VERSION 5.7 ;
  NOWIREEXTENSIONATPIN ON ;
  DIVIDERCHAR "/" ;
  BUSBITCHARS "[]" ;
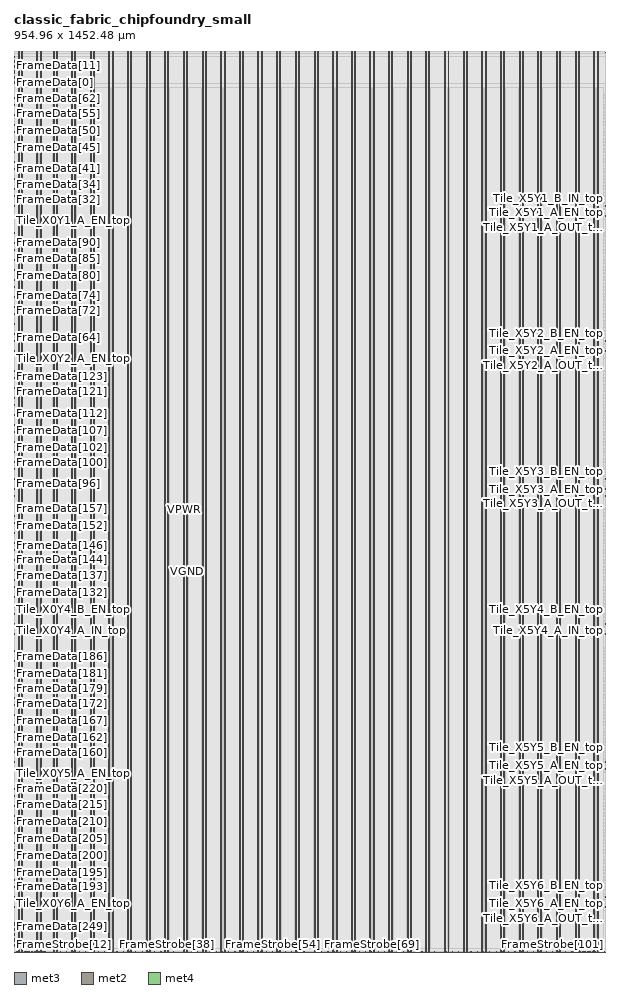
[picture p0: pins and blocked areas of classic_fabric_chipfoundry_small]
MACRO classic_fabric_chipfoundry_small
  CLASS BLOCK ;
  FOREIGN classic_fabric_chipfoundry_small ;
  ORIGIN 0.000 0.000 ;
  SIZE 954.960 BY 1452.480 ;
  PIN FrameData[0]
    DIRECTION INPUT ;
    USE SIGNAL ;
    ANTENNAGATEAREA 0.593700 ;
    ANTENNADIFFAREA 0.434700 ;
    PORT
      LAYER met3 ;
        RECT 0.000 1402.200 0.600 1402.800 ;
    END
  END FrameData[0]
  PIN FrameData[100]
    DIRECTION INPUT ;
    USE SIGNAL ;
    ANTENNAGATEAREA 0.795000 ;
    PORT
      LAYER met3 ;
        RECT 0.000 790.200 0.600 790.800 ;
    END
  END FrameData[100]
  PIN FrameData[101]
    DIRECTION INPUT ;
    USE SIGNAL ;
    ANTENNAGATEAREA 0.795000 ;
    PORT
      LAYER met3 ;
        RECT 0.000 795.640 0.600 796.240 ;
    END
  END FrameData[101]
  PIN FrameData[102]
    DIRECTION INPUT ;
    USE SIGNAL ;
    ANTENNAGATEAREA 0.795000 ;
    PORT
      LAYER met3 ;
        RECT 0.000 801.080 0.600 801.680 ;
    END
  END FrameData[102]
  PIN FrameData[103]
    DIRECTION INPUT ;
    USE SIGNAL ;
    ANTENNAGATEAREA 0.795000 ;
    PORT
      LAYER met3 ;
        RECT 0.000 806.520 0.600 807.120 ;
    END
  END FrameData[103]
  PIN FrameData[104]
    DIRECTION INPUT ;
    USE SIGNAL ;
    ANTENNAGATEAREA 0.795000 ;
    PORT
      LAYER met3 ;
        RECT 0.000 811.960 0.600 812.560 ;
    END
  END FrameData[104]
  PIN FrameData[105]
    DIRECTION INPUT ;
    USE SIGNAL ;
    ANTENNAGATEAREA 0.795000 ;
    PORT
      LAYER met3 ;
        RECT 0.000 817.400 0.600 818.000 ;
    END
  END FrameData[105]
  PIN FrameData[106]
    DIRECTION INPUT ;
    USE SIGNAL ;
    ANTENNAGATEAREA 0.795000 ;
    PORT
      LAYER met3 ;
        RECT 0.000 822.840 0.600 823.440 ;
    END
  END FrameData[106]
  PIN FrameData[107]
    DIRECTION INPUT ;
    USE SIGNAL ;
    ANTENNAGATEAREA 0.795000 ;
    PORT
      LAYER met3 ;
        RECT 0.000 828.280 0.600 828.880 ;
    END
  END FrameData[107]
  PIN FrameData[108]
    DIRECTION INPUT ;
    USE SIGNAL ;
    ANTENNAGATEAREA 0.795000 ;
    PORT
      LAYER met3 ;
        RECT 0.000 833.720 0.600 834.320 ;
    END
  END FrameData[108]
  PIN FrameData[109]
    DIRECTION INPUT ;
    USE SIGNAL ;
    ANTENNAGATEAREA 0.795000 ;
    PORT
      LAYER met3 ;
        RECT 0.000 839.160 0.600 839.760 ;
    END
  END FrameData[109]
  PIN FrameData[10]
    DIRECTION INPUT ;
    USE SIGNAL ;
    ANTENNAGATEAREA 0.159000 ;
    PORT
      LAYER met3 ;
        RECT 0.000 1415.800 0.600 1416.400 ;
    END
  END FrameData[10]
  PIN FrameData[110]
    DIRECTION INPUT ;
    USE SIGNAL ;
    ANTENNAGATEAREA 0.795000 ;
    PORT
      LAYER met3 ;
        RECT 0.000 844.600 0.600 845.200 ;
    END
  END FrameData[110]
  PIN FrameData[111]
    DIRECTION INPUT ;
    USE SIGNAL ;
    ANTENNAGATEAREA 0.795000 ;
    PORT
      LAYER met3 ;
        RECT 0.000 850.040 0.600 850.640 ;
    END
  END FrameData[111]
  PIN FrameData[112]
    DIRECTION INPUT ;
    USE SIGNAL ;
    ANTENNAGATEAREA 0.795000 ;
    PORT
      LAYER met3 ;
        RECT 0.000 855.480 0.600 856.080 ;
    END
  END FrameData[112]
  PIN FrameData[113]
    DIRECTION INPUT ;
    USE SIGNAL ;
    ANTENNAGATEAREA 0.795000 ;
    PORT
      LAYER met3 ;
        RECT 0.000 860.920 0.600 861.520 ;
    END
  END FrameData[113]
  PIN FrameData[114]
    DIRECTION INPUT ;
    USE SIGNAL ;
    ANTENNAGATEAREA 1.229700 ;
    ANTENNADIFFAREA 0.434700 ;
    PORT
      LAYER met3 ;
        RECT 0.000 866.360 0.600 866.960 ;
    END
  END FrameData[114]
  PIN FrameData[115]
    DIRECTION INPUT ;
    USE SIGNAL ;
    ANTENNAGATEAREA 0.795000 ;
    PORT
      LAYER met3 ;
        RECT 0.000 871.800 0.600 872.400 ;
    END
  END FrameData[115]
  PIN FrameData[116]
    DIRECTION INPUT ;
    USE SIGNAL ;
    ANTENNAGATEAREA 0.795000 ;
    PORT
      LAYER met3 ;
        RECT 0.000 877.240 0.600 877.840 ;
    END
  END FrameData[116]
  PIN FrameData[117]
    DIRECTION INPUT ;
    USE SIGNAL ;
    ANTENNAGATEAREA 0.795000 ;
    PORT
      LAYER met3 ;
        RECT 0.000 882.680 0.600 883.280 ;
    END
  END FrameData[117]
  PIN FrameData[118]
    DIRECTION INPUT ;
    USE SIGNAL ;
    ANTENNAGATEAREA 1.229700 ;
    ANTENNADIFFAREA 0.434700 ;
    PORT
      LAYER met3 ;
        RECT 0.000 888.120 0.600 888.720 ;
    END
  END FrameData[118]
  PIN FrameData[119]
    DIRECTION INPUT ;
    USE SIGNAL ;
    ANTENNAGATEAREA 0.795000 ;
    PORT
      LAYER met3 ;
        RECT 0.000 893.560 0.600 894.160 ;
    END
  END FrameData[119]
  PIN FrameData[11]
    DIRECTION INPUT ;
    USE SIGNAL ;
    ANTENNAGATEAREA 0.159000 ;
    PORT
      LAYER met3 ;
        RECT 0.000 1417.160 0.600 1417.760 ;
    END
  END FrameData[11]
  PIN FrameData[120]
    DIRECTION INPUT ;
    USE SIGNAL ;
    ANTENNAGATEAREA 0.795000 ;
    PORT
      LAYER met3 ;
        RECT 0.000 899.000 0.600 899.600 ;
    END
  END FrameData[120]
  PIN FrameData[121]
    DIRECTION INPUT ;
    USE SIGNAL ;
    ANTENNAGATEAREA 0.795000 ;
    PORT
      LAYER met3 ;
        RECT 0.000 904.440 0.600 905.040 ;
    END
  END FrameData[121]
  PIN FrameData[122]
    DIRECTION INPUT ;
    USE SIGNAL ;
    ANTENNAGATEAREA 0.795000 ;
    PORT
      LAYER met3 ;
        RECT 0.000 909.880 0.600 910.480 ;
    END
  END FrameData[122]
  PIN FrameData[123]
    DIRECTION INPUT ;
    USE SIGNAL ;
    ANTENNAGATEAREA 0.795000 ;
    PORT
      LAYER met3 ;
        RECT 0.000 915.320 0.600 915.920 ;
    END
  END FrameData[123]
  PIN FrameData[124]
    DIRECTION INPUT ;
    USE SIGNAL ;
    ANTENNAGATEAREA 0.795000 ;
    PORT
      LAYER met3 ;
        RECT 0.000 920.760 0.600 921.360 ;
    END
  END FrameData[124]
  PIN FrameData[125]
    DIRECTION INPUT ;
    USE SIGNAL ;
    ANTENNAGATEAREA 0.795000 ;
    PORT
      LAYER met3 ;
        RECT 0.000 926.200 0.600 926.800 ;
    END
  END FrameData[125]
  PIN FrameData[126]
    DIRECTION INPUT ;
    USE SIGNAL ;
    ANTENNAGATEAREA 0.795000 ;
    PORT
      LAYER met3 ;
        RECT 0.000 931.640 0.600 932.240 ;
    END
  END FrameData[126]
  PIN FrameData[127]
    DIRECTION INPUT ;
    USE SIGNAL ;
    ANTENNAGATEAREA 0.795000 ;
    PORT
      LAYER met3 ;
        RECT 0.000 937.080 0.600 937.680 ;
    END
  END FrameData[127]
  PIN FrameData[128]
    DIRECTION INPUT ;
    USE SIGNAL ;
    ANTENNAGATEAREA 0.636000 ;
    PORT
      LAYER met3 ;
        RECT 0.000 545.400 0.600 546.000 ;
    END
  END FrameData[128]
  PIN FrameData[129]
    DIRECTION INPUT ;
    USE SIGNAL ;
    ANTENNAGATEAREA 0.636000 ;
    PORT
      LAYER met3 ;
        RECT 0.000 550.840 0.600 551.440 ;
    END
  END FrameData[129]
  PIN FrameData[12]
    DIRECTION INPUT ;
    USE SIGNAL ;
    ANTENNAGATEAREA 0.593700 ;
    ANTENNADIFFAREA 0.434700 ;
    PORT
      LAYER met3 ;
        RECT 0.000 1418.520 0.600 1419.120 ;
    END
  END FrameData[12]
  PIN FrameData[130]
    DIRECTION INPUT ;
    USE SIGNAL ;
    ANTENNAGATEAREA 0.795000 ;
    PORT
      LAYER met3 ;
        RECT 0.000 556.280 0.600 556.880 ;
    END
  END FrameData[130]
  PIN FrameData[131]
    DIRECTION INPUT ;
    USE SIGNAL ;
    ANTENNAGATEAREA 0.795000 ;
    PORT
      LAYER met3 ;
        RECT 0.000 561.720 0.600 562.320 ;
    END
  END FrameData[131]
  PIN FrameData[132]
    DIRECTION INPUT ;
    USE SIGNAL ;
    ANTENNAGATEAREA 0.795000 ;
    PORT
      LAYER met3 ;
        RECT 0.000 567.160 0.600 567.760 ;
    END
  END FrameData[132]
  PIN FrameData[133]
    DIRECTION INPUT ;
    USE SIGNAL ;
    ANTENNAGATEAREA 0.795000 ;
    PORT
      LAYER met3 ;
        RECT 0.000 572.600 0.600 573.200 ;
    END
  END FrameData[133]
  PIN FrameData[134]
    DIRECTION INPUT ;
    USE SIGNAL ;
    ANTENNAGATEAREA 0.795000 ;
    PORT
      LAYER met3 ;
        RECT 0.000 578.040 0.600 578.640 ;
    END
  END FrameData[134]
  PIN FrameData[135]
    DIRECTION INPUT ;
    USE SIGNAL ;
    ANTENNAGATEAREA 0.795000 ;
    PORT
      LAYER met3 ;
        RECT 0.000 583.480 0.600 584.080 ;
    END
  END FrameData[135]
  PIN FrameData[136]
    DIRECTION INPUT ;
    USE SIGNAL ;
    ANTENNAGATEAREA 0.795000 ;
    PORT
      LAYER met3 ;
        RECT 0.000 588.920 0.600 589.520 ;
    END
  END FrameData[136]
  PIN FrameData[137]
    DIRECTION INPUT ;
    USE SIGNAL ;
    ANTENNAGATEAREA 0.795000 ;
    PORT
      LAYER met3 ;
        RECT 0.000 594.360 0.600 594.960 ;
    END
  END FrameData[137]
  PIN FrameData[138]
    DIRECTION INPUT ;
    USE SIGNAL ;
    ANTENNAGATEAREA 0.795000 ;
    PORT
      LAYER met3 ;
        RECT 0.000 599.800 0.600 600.400 ;
    END
  END FrameData[138]
  PIN FrameData[139]
    DIRECTION INPUT ;
    USE SIGNAL ;
    ANTENNAGATEAREA 0.795000 ;
    PORT
      LAYER met3 ;
        RECT 0.000 605.240 0.600 605.840 ;
    END
  END FrameData[139]
  PIN FrameData[13]
    DIRECTION INPUT ;
    USE SIGNAL ;
    ANTENNAGATEAREA 0.593700 ;
    ANTENNADIFFAREA 0.434700 ;
    PORT
      LAYER met3 ;
        RECT 0.000 1419.880 0.600 1420.480 ;
    END
  END FrameData[13]
  PIN FrameData[140]
    DIRECTION INPUT ;
    USE SIGNAL ;
    ANTENNAGATEAREA 0.795000 ;
    PORT
      LAYER met3 ;
        RECT 0.000 610.680 0.600 611.280 ;
    END
  END FrameData[140]
  PIN FrameData[141]
    DIRECTION INPUT ;
    USE SIGNAL ;
    ANTENNAGATEAREA 0.795000 ;
    PORT
      LAYER met3 ;
        RECT 0.000 616.120 0.600 616.720 ;
    END
  END FrameData[141]
  PIN FrameData[142]
    DIRECTION INPUT ;
    USE SIGNAL ;
    ANTENNAGATEAREA 0.795000 ;
    PORT
      LAYER met3 ;
        RECT 0.000 621.560 0.600 622.160 ;
    END
  END FrameData[142]
  PIN FrameData[143]
    DIRECTION INPUT ;
    USE SIGNAL ;
    ANTENNAGATEAREA 0.795000 ;
    PORT
      LAYER met3 ;
        RECT 0.000 627.000 0.600 627.600 ;
    END
  END FrameData[143]
  PIN FrameData[144]
    DIRECTION INPUT ;
    USE SIGNAL ;
    ANTENNAGATEAREA 0.795000 ;
    PORT
      LAYER met3 ;
        RECT 0.000 632.440 0.600 633.040 ;
    END
  END FrameData[144]
  PIN FrameData[145]
    DIRECTION INPUT ;
    USE SIGNAL ;
    ANTENNAGATEAREA 0.795000 ;
    PORT
      LAYER met3 ;
        RECT 0.000 637.880 0.600 638.480 ;
    END
  END FrameData[145]
  PIN FrameData[146]
    DIRECTION INPUT ;
    USE SIGNAL ;
    ANTENNAGATEAREA 1.229700 ;
    ANTENNADIFFAREA 0.434700 ;
    PORT
      LAYER met3 ;
        RECT 0.000 643.320 0.600 643.920 ;
    END
  END FrameData[146]
  PIN FrameData[147]
    DIRECTION INPUT ;
    USE SIGNAL ;
    ANTENNAGATEAREA 0.795000 ;
    PORT
      LAYER met3 ;
        RECT 0.000 648.760 0.600 649.360 ;
    END
  END FrameData[147]
  PIN FrameData[148]
    DIRECTION INPUT ;
    USE SIGNAL ;
    ANTENNAGATEAREA 0.795000 ;
    PORT
      LAYER met3 ;
        RECT 0.000 654.200 0.600 654.800 ;
    END
  END FrameData[148]
  PIN FrameData[149]
    DIRECTION INPUT ;
    USE SIGNAL ;
    ANTENNAGATEAREA 0.795000 ;
    PORT
      LAYER met3 ;
        RECT 0.000 659.640 0.600 660.240 ;
    END
  END FrameData[149]
  PIN FrameData[14]
    DIRECTION INPUT ;
    USE SIGNAL ;
    ANTENNAGATEAREA 0.593700 ;
    ANTENNADIFFAREA 0.434700 ;
    PORT
      LAYER met3 ;
        RECT 0.000 1421.240 0.600 1421.840 ;
    END
  END FrameData[14]
  PIN FrameData[150]
    DIRECTION INPUT ;
    USE SIGNAL ;
    ANTENNAGATEAREA 1.229700 ;
    ANTENNADIFFAREA 0.434700 ;
    PORT
      LAYER met3 ;
        RECT 0.000 665.080 0.600 665.680 ;
    END
  END FrameData[150]
  PIN FrameData[151]
    DIRECTION INPUT ;
    USE SIGNAL ;
    ANTENNAGATEAREA 0.795000 ;
    PORT
      LAYER met3 ;
        RECT 0.000 670.520 0.600 671.120 ;
    END
  END FrameData[151]
  PIN FrameData[152]
    DIRECTION INPUT ;
    USE SIGNAL ;
    ANTENNAGATEAREA 0.795000 ;
    PORT
      LAYER met3 ;
        RECT 0.000 675.960 0.600 676.560 ;
    END
  END FrameData[152]
  PIN FrameData[153]
    DIRECTION INPUT ;
    USE SIGNAL ;
    ANTENNAGATEAREA 0.795000 ;
    PORT
      LAYER met3 ;
        RECT 0.000 681.400 0.600 682.000 ;
    END
  END FrameData[153]
  PIN FrameData[154]
    DIRECTION INPUT ;
    USE SIGNAL ;
    ANTENNAGATEAREA 0.795000 ;
    PORT
      LAYER met3 ;
        RECT 0.000 686.840 0.600 687.440 ;
    END
  END FrameData[154]
  PIN FrameData[155]
    DIRECTION INPUT ;
    USE SIGNAL ;
    ANTENNAGATEAREA 0.795000 ;
    PORT
      LAYER met3 ;
        RECT 0.000 692.280 0.600 692.880 ;
    END
  END FrameData[155]
  PIN FrameData[156]
    DIRECTION INPUT ;
    USE SIGNAL ;
    ANTENNAGATEAREA 0.795000 ;
    PORT
      LAYER met3 ;
        RECT 0.000 697.720 0.600 698.320 ;
    END
  END FrameData[156]
  PIN FrameData[157]
    DIRECTION INPUT ;
    USE SIGNAL ;
    ANTENNAGATEAREA 0.795000 ;
    PORT
      LAYER met3 ;
        RECT 0.000 703.160 0.600 703.760 ;
    END
  END FrameData[157]
  PIN FrameData[158]
    DIRECTION INPUT ;
    USE SIGNAL ;
    ANTENNAGATEAREA 0.795000 ;
    PORT
      LAYER met3 ;
        RECT 0.000 708.600 0.600 709.200 ;
    END
  END FrameData[158]
  PIN FrameData[159]
    DIRECTION INPUT ;
    USE SIGNAL ;
    ANTENNAGATEAREA 0.795000 ;
    PORT
      LAYER met3 ;
        RECT 0.000 714.040 0.600 714.640 ;
    END
  END FrameData[159]
  PIN FrameData[15]
    DIRECTION INPUT ;
    USE SIGNAL ;
    ANTENNAGATEAREA 0.159000 ;
    PORT
      LAYER met3 ;
        RECT 0.000 1422.600 0.600 1423.200 ;
    END
  END FrameData[15]
  PIN FrameData[160]
    DIRECTION INPUT ;
    USE SIGNAL ;
    ANTENNAGATEAREA 0.636000 ;
    PORT
      LAYER met3 ;
        RECT 0.000 322.360 0.600 322.960 ;
    END
  END FrameData[160]
  PIN FrameData[161]
    DIRECTION INPUT ;
    USE SIGNAL ;
    ANTENNAGATEAREA 0.636000 ;
    PORT
      LAYER met3 ;
        RECT 0.000 327.800 0.600 328.400 ;
    END
  END FrameData[161]
  PIN FrameData[162]
    DIRECTION INPUT ;
    USE SIGNAL ;
    ANTENNAGATEAREA 0.795000 ;
    PORT
      LAYER met3 ;
        RECT 0.000 333.240 0.600 333.840 ;
    END
  END FrameData[162]
  PIN FrameData[163]
    DIRECTION INPUT ;
    USE SIGNAL ;
    ANTENNAGATEAREA 0.795000 ;
    PORT
      LAYER met3 ;
        RECT 0.000 338.680 0.600 339.280 ;
    END
  END FrameData[163]
  PIN FrameData[164]
    DIRECTION INPUT ;
    USE SIGNAL ;
    ANTENNAGATEAREA 0.795000 ;
    PORT
      LAYER met3 ;
        RECT 0.000 344.120 0.600 344.720 ;
    END
  END FrameData[164]
  PIN FrameData[165]
    DIRECTION INPUT ;
    USE SIGNAL ;
    ANTENNAGATEAREA 0.795000 ;
    PORT
      LAYER met3 ;
        RECT 0.000 349.560 0.600 350.160 ;
    END
  END FrameData[165]
  PIN FrameData[166]
    DIRECTION INPUT ;
    USE SIGNAL ;
    ANTENNAGATEAREA 0.795000 ;
    PORT
      LAYER met3 ;
        RECT 0.000 355.000 0.600 355.600 ;
    END
  END FrameData[166]
  PIN FrameData[167]
    DIRECTION INPUT ;
    USE SIGNAL ;
    ANTENNAGATEAREA 0.795000 ;
    PORT
      LAYER met3 ;
        RECT 0.000 360.440 0.600 361.040 ;
    END
  END FrameData[167]
  PIN FrameData[168]
    DIRECTION INPUT ;
    USE SIGNAL ;
    ANTENNAGATEAREA 0.795000 ;
    PORT
      LAYER met3 ;
        RECT 0.000 365.880 0.600 366.480 ;
    END
  END FrameData[168]
  PIN FrameData[169]
    DIRECTION INPUT ;
    USE SIGNAL ;
    ANTENNAGATEAREA 0.795000 ;
    PORT
      LAYER met3 ;
        RECT 0.000 371.320 0.600 371.920 ;
    END
  END FrameData[169]
  PIN FrameData[16]
    DIRECTION INPUT ;
    USE SIGNAL ;
    ANTENNAGATEAREA 0.159000 ;
    PORT
      LAYER met3 ;
        RECT 0.000 1423.960 0.600 1424.560 ;
    END
  END FrameData[16]
  PIN FrameData[170]
    DIRECTION INPUT ;
    USE SIGNAL ;
    ANTENNAGATEAREA 0.795000 ;
    PORT
      LAYER met3 ;
        RECT 0.000 376.760 0.600 377.360 ;
    END
  END FrameData[170]
  PIN FrameData[171]
    DIRECTION INPUT ;
    USE SIGNAL ;
    ANTENNAGATEAREA 0.795000 ;
    PORT
      LAYER met3 ;
        RECT 0.000 382.200 0.600 382.800 ;
    END
  END FrameData[171]
  PIN FrameData[172]
    DIRECTION INPUT ;
    USE SIGNAL ;
    ANTENNAGATEAREA 0.795000 ;
    PORT
      LAYER met3 ;
        RECT 0.000 387.640 0.600 388.240 ;
    END
  END FrameData[172]
  PIN FrameData[173]
    DIRECTION INPUT ;
    USE SIGNAL ;
    ANTENNAGATEAREA 0.795000 ;
    PORT
      LAYER met3 ;
        RECT 0.000 393.080 0.600 393.680 ;
    END
  END FrameData[173]
  PIN FrameData[174]
    DIRECTION INPUT ;
    USE SIGNAL ;
    ANTENNAGATEAREA 0.795000 ;
    PORT
      LAYER met3 ;
        RECT 0.000 398.520 0.600 399.120 ;
    END
  END FrameData[174]
  PIN FrameData[175]
    DIRECTION INPUT ;
    USE SIGNAL ;
    ANTENNAGATEAREA 0.795000 ;
    PORT
      LAYER met3 ;
        RECT 0.000 403.960 0.600 404.560 ;
    END
  END FrameData[175]
  PIN FrameData[176]
    DIRECTION INPUT ;
    USE SIGNAL ;
    ANTENNAGATEAREA 0.795000 ;
    PORT
      LAYER met3 ;
        RECT 0.000 409.400 0.600 410.000 ;
    END
  END FrameData[176]
  PIN FrameData[177]
    DIRECTION INPUT ;
    USE SIGNAL ;
    ANTENNAGATEAREA 0.795000 ;
    PORT
      LAYER met3 ;
        RECT 0.000 414.840 0.600 415.440 ;
    END
  END FrameData[177]
  PIN FrameData[178]
    DIRECTION INPUT ;
    USE SIGNAL ;
    ANTENNAGATEAREA 1.229700 ;
    ANTENNADIFFAREA 0.434700 ;
    PORT
      LAYER met3 ;
        RECT 0.000 420.280 0.600 420.880 ;
    END
  END FrameData[178]
  PIN FrameData[179]
    DIRECTION INPUT ;
    USE SIGNAL ;
    ANTENNAGATEAREA 0.795000 ;
    PORT
      LAYER met3 ;
        RECT 0.000 425.720 0.600 426.320 ;
    END
  END FrameData[179]
  PIN FrameData[17]
    DIRECTION INPUT ;
    USE SIGNAL ;
    ANTENNAGATEAREA 0.159000 ;
    PORT
      LAYER met3 ;
        RECT 0.000 1425.320 0.600 1425.920 ;
    END
  END FrameData[17]
  PIN FrameData[180]
    DIRECTION INPUT ;
    USE SIGNAL ;
    ANTENNAGATEAREA 0.795000 ;
    PORT
      LAYER met3 ;
        RECT 0.000 431.160 0.600 431.760 ;
    END
  END FrameData[180]
  PIN FrameData[181]
    DIRECTION INPUT ;
    USE SIGNAL ;
    ANTENNAGATEAREA 0.795000 ;
    PORT
      LAYER met3 ;
        RECT 0.000 436.600 0.600 437.200 ;
    END
  END FrameData[181]
  PIN FrameData[182]
    DIRECTION INPUT ;
    USE SIGNAL ;
    ANTENNAGATEAREA 1.229700 ;
    ANTENNADIFFAREA 0.434700 ;
    PORT
      LAYER met3 ;
        RECT 0.000 442.040 0.600 442.640 ;
    END
  END FrameData[182]
  PIN FrameData[183]
    DIRECTION INPUT ;
    USE SIGNAL ;
    ANTENNAGATEAREA 0.795000 ;
    PORT
      LAYER met3 ;
        RECT 0.000 447.480 0.600 448.080 ;
    END
  END FrameData[183]
  PIN FrameData[184]
    DIRECTION INPUT ;
    USE SIGNAL ;
    ANTENNAGATEAREA 0.795000 ;
    PORT
      LAYER met3 ;
        RECT 0.000 452.920 0.600 453.520 ;
    END
  END FrameData[184]
  PIN FrameData[185]
    DIRECTION INPUT ;
    USE SIGNAL ;
    ANTENNAGATEAREA 0.795000 ;
    PORT
      LAYER met3 ;
        RECT 0.000 458.360 0.600 458.960 ;
    END
  END FrameData[185]
  PIN FrameData[186]
    DIRECTION INPUT ;
    USE SIGNAL ;
    ANTENNAGATEAREA 0.795000 ;
    PORT
      LAYER met3 ;
        RECT 0.000 463.800 0.600 464.400 ;
    END
  END FrameData[186]
  PIN FrameData[187]
    DIRECTION INPUT ;
    USE SIGNAL ;
    ANTENNAGATEAREA 0.795000 ;
    PORT
      LAYER met3 ;
        RECT 0.000 469.240 0.600 469.840 ;
    END
  END FrameData[187]
  PIN FrameData[188]
    DIRECTION INPUT ;
    USE SIGNAL ;
    ANTENNAGATEAREA 0.795000 ;
    PORT
      LAYER met3 ;
        RECT 0.000 474.680 0.600 475.280 ;
    END
  END FrameData[188]
  PIN FrameData[189]
    DIRECTION INPUT ;
    USE SIGNAL ;
    ANTENNAGATEAREA 0.795000 ;
    PORT
      LAYER met3 ;
        RECT 0.000 480.120 0.600 480.720 ;
    END
  END FrameData[189]
  PIN FrameData[18]
    DIRECTION INPUT ;
    USE SIGNAL ;
    ANTENNAGATEAREA 0.159000 ;
    PORT
      LAYER met3 ;
        RECT 0.000 1426.680 0.600 1427.280 ;
    END
  END FrameData[18]
  PIN FrameData[190]
    DIRECTION INPUT ;
    USE SIGNAL ;
    ANTENNAGATEAREA 0.795000 ;
    PORT
      LAYER met3 ;
        RECT 0.000 485.560 0.600 486.160 ;
    END
  END FrameData[190]
  PIN FrameData[191]
    DIRECTION INPUT ;
    USE SIGNAL ;
    ANTENNAGATEAREA 0.795000 ;
    PORT
      LAYER met3 ;
        RECT 0.000 491.000 0.600 491.600 ;
    END
  END FrameData[191]
  PIN FrameData[192]
    DIRECTION INPUT ;
    USE SIGNAL ;
    ANTENNAGATEAREA 0.636000 ;
    PORT
      LAYER met3 ;
        RECT 0.000 99.320 0.600 99.920 ;
    END
  END FrameData[192]
  PIN FrameData[193]
    DIRECTION INPUT ;
    USE SIGNAL ;
    ANTENNAGATEAREA 0.636000 ;
    PORT
      LAYER met3 ;
        RECT 0.000 104.760 0.600 105.360 ;
    END
  END FrameData[193]
  PIN FrameData[194]
    DIRECTION INPUT ;
    USE SIGNAL ;
    ANTENNAGATEAREA 0.795000 ;
    PORT
      LAYER met3 ;
        RECT 0.000 110.200 0.600 110.800 ;
    END
  END FrameData[194]
  PIN FrameData[195]
    DIRECTION INPUT ;
    USE SIGNAL ;
    ANTENNAGATEAREA 0.795000 ;
    PORT
      LAYER met3 ;
        RECT 0.000 115.640 0.600 116.240 ;
    END
  END FrameData[195]
  PIN FrameData[196]
    DIRECTION INPUT ;
    USE SIGNAL ;
    ANTENNAGATEAREA 0.795000 ;
    PORT
      LAYER met3 ;
        RECT 0.000 121.080 0.600 121.680 ;
    END
  END FrameData[196]
  PIN FrameData[197]
    DIRECTION INPUT ;
    USE SIGNAL ;
    ANTENNAGATEAREA 0.795000 ;
    PORT
      LAYER met3 ;
        RECT 0.000 126.520 0.600 127.120 ;
    END
  END FrameData[197]
  PIN FrameData[198]
    DIRECTION INPUT ;
    USE SIGNAL ;
    ANTENNAGATEAREA 0.795000 ;
    PORT
      LAYER met3 ;
        RECT 0.000 131.960 0.600 132.560 ;
    END
  END FrameData[198]
  PIN FrameData[199]
    DIRECTION INPUT ;
    USE SIGNAL ;
    ANTENNAGATEAREA 0.795000 ;
    PORT
      LAYER met3 ;
        RECT 0.000 137.400 0.600 138.000 ;
    END
  END FrameData[199]
  PIN FrameData[19]
    DIRECTION INPUT ;
    USE SIGNAL ;
    ANTENNAGATEAREA 0.159000 ;
    PORT
      LAYER met3 ;
        RECT 0.000 1428.040 0.600 1428.640 ;
    END
  END FrameData[19]
  PIN FrameData[1]
    DIRECTION INPUT ;
    USE SIGNAL ;
    ANTENNAGATEAREA 0.593700 ;
    ANTENNADIFFAREA 0.434700 ;
    PORT
      LAYER met3 ;
        RECT 0.000 1403.560 0.600 1404.160 ;
    END
  END FrameData[1]
  PIN FrameData[200]
    DIRECTION INPUT ;
    USE SIGNAL ;
    ANTENNAGATEAREA 0.795000 ;
    PORT
      LAYER met3 ;
        RECT 0.000 142.840 0.600 143.440 ;
    END
  END FrameData[200]
  PIN FrameData[201]
    DIRECTION INPUT ;
    USE SIGNAL ;
    ANTENNAGATEAREA 0.795000 ;
    PORT
      LAYER met3 ;
        RECT 0.000 148.280 0.600 148.880 ;
    END
  END FrameData[201]
  PIN FrameData[202]
    DIRECTION INPUT ;
    USE SIGNAL ;
    ANTENNAGATEAREA 0.795000 ;
    PORT
      LAYER met3 ;
        RECT 0.000 153.720 0.600 154.320 ;
    END
  END FrameData[202]
  PIN FrameData[203]
    DIRECTION INPUT ;
    USE SIGNAL ;
    ANTENNAGATEAREA 0.795000 ;
    PORT
      LAYER met3 ;
        RECT 0.000 159.160 0.600 159.760 ;
    END
  END FrameData[203]
  PIN FrameData[204]
    DIRECTION INPUT ;
    USE SIGNAL ;
    ANTENNAGATEAREA 0.795000 ;
    PORT
      LAYER met3 ;
        RECT 0.000 164.600 0.600 165.200 ;
    END
  END FrameData[204]
  PIN FrameData[205]
    DIRECTION INPUT ;
    USE SIGNAL ;
    ANTENNAGATEAREA 0.795000 ;
    PORT
      LAYER met3 ;
        RECT 0.000 170.040 0.600 170.640 ;
    END
  END FrameData[205]
  PIN FrameData[206]
    DIRECTION INPUT ;
    USE SIGNAL ;
    ANTENNAGATEAREA 0.795000 ;
    PORT
      LAYER met3 ;
        RECT 0.000 175.480 0.600 176.080 ;
    END
  END FrameData[206]
  PIN FrameData[207]
    DIRECTION INPUT ;
    USE SIGNAL ;
    ANTENNAGATEAREA 0.795000 ;
    PORT
      LAYER met3 ;
        RECT 0.000 180.920 0.600 181.520 ;
    END
  END FrameData[207]
  PIN FrameData[208]
    DIRECTION INPUT ;
    USE SIGNAL ;
    ANTENNAGATEAREA 0.795000 ;
    PORT
      LAYER met3 ;
        RECT 0.000 186.360 0.600 186.960 ;
    END
  END FrameData[208]
  PIN FrameData[209]
    DIRECTION INPUT ;
    USE SIGNAL ;
    ANTENNAGATEAREA 0.795000 ;
    PORT
      LAYER met3 ;
        RECT 0.000 191.800 0.600 192.400 ;
    END
  END FrameData[209]
  PIN FrameData[20]
    DIRECTION INPUT ;
    USE SIGNAL ;
    ANTENNAGATEAREA 0.159000 ;
    PORT
      LAYER met3 ;
        RECT 0.000 1429.400 0.600 1430.000 ;
    END
  END FrameData[20]
  PIN FrameData[210]
    DIRECTION INPUT ;
    USE SIGNAL ;
    ANTENNAGATEAREA 1.229700 ;
    ANTENNADIFFAREA 0.434700 ;
    PORT
      LAYER met3 ;
        RECT 0.000 197.240 0.600 197.840 ;
    END
  END FrameData[210]
  PIN FrameData[211]
    DIRECTION INPUT ;
    USE SIGNAL ;
    ANTENNAGATEAREA 0.795000 ;
    PORT
      LAYER met3 ;
        RECT 0.000 202.680 0.600 203.280 ;
    END
  END FrameData[211]
  PIN FrameData[212]
    DIRECTION INPUT ;
    USE SIGNAL ;
    ANTENNAGATEAREA 0.795000 ;
    PORT
      LAYER met3 ;
        RECT 0.000 208.120 0.600 208.720 ;
    END
  END FrameData[212]
  PIN FrameData[213]
    DIRECTION INPUT ;
    USE SIGNAL ;
    ANTENNAGATEAREA 0.795000 ;
    PORT
      LAYER met3 ;
        RECT 0.000 213.560 0.600 214.160 ;
    END
  END FrameData[213]
  PIN FrameData[214]
    DIRECTION INPUT ;
    USE SIGNAL ;
    ANTENNAGATEAREA 1.229700 ;
    ANTENNADIFFAREA 0.434700 ;
    PORT
      LAYER met3 ;
        RECT 0.000 219.000 0.600 219.600 ;
    END
  END FrameData[214]
  PIN FrameData[215]
    DIRECTION INPUT ;
    USE SIGNAL ;
    ANTENNAGATEAREA 0.795000 ;
    PORT
      LAYER met3 ;
        RECT 0.000 224.440 0.600 225.040 ;
    END
  END FrameData[215]
  PIN FrameData[216]
    DIRECTION INPUT ;
    USE SIGNAL ;
    ANTENNAGATEAREA 0.795000 ;
    PORT
      LAYER met3 ;
        RECT 0.000 229.880 0.600 230.480 ;
    END
  END FrameData[216]
  PIN FrameData[217]
    DIRECTION INPUT ;
    USE SIGNAL ;
    ANTENNAGATEAREA 0.795000 ;
    PORT
      LAYER met3 ;
        RECT 0.000 235.320 0.600 235.920 ;
    END
  END FrameData[217]
  PIN FrameData[218]
    DIRECTION INPUT ;
    USE SIGNAL ;
    ANTENNAGATEAREA 0.795000 ;
    PORT
      LAYER met3 ;
        RECT 0.000 240.760 0.600 241.360 ;
    END
  END FrameData[218]
  PIN FrameData[219]
    DIRECTION INPUT ;
    USE SIGNAL ;
    ANTENNAGATEAREA 0.795000 ;
    PORT
      LAYER met3 ;
        RECT 0.000 246.200 0.600 246.800 ;
    END
  END FrameData[219]
  PIN FrameData[21]
    DIRECTION INPUT ;
    USE SIGNAL ;
    ANTENNAGATEAREA 0.159000 ;
    PORT
      LAYER met3 ;
        RECT 0.000 1430.760 0.600 1431.360 ;
    END
  END FrameData[21]
  PIN FrameData[220]
    DIRECTION INPUT ;
    USE SIGNAL ;
    ANTENNAGATEAREA 0.795000 ;
    PORT
      LAYER met3 ;
        RECT 0.000 251.640 0.600 252.240 ;
    END
  END FrameData[220]
  PIN FrameData[221]
    DIRECTION INPUT ;
    USE SIGNAL ;
    ANTENNAGATEAREA 0.795000 ;
    PORT
      LAYER met3 ;
        RECT 0.000 257.080 0.600 257.680 ;
    END
  END FrameData[221]
  PIN FrameData[222]
    DIRECTION INPUT ;
    USE SIGNAL ;
    ANTENNAGATEAREA 0.795000 ;
    PORT
      LAYER met3 ;
        RECT 0.000 262.520 0.600 263.120 ;
    END
  END FrameData[222]
  PIN FrameData[223]
    DIRECTION INPUT ;
    USE SIGNAL ;
    ANTENNAGATEAREA 0.795000 ;
    PORT
      LAYER met3 ;
        RECT 0.000 267.960 0.600 268.560 ;
    END
  END FrameData[223]
  PIN FrameData[224]
    DIRECTION INPUT ;
    USE SIGNAL ;
    ANTENNAGATEAREA 0.159000 ;
    PORT
      LAYER met3 ;
        RECT 0.000 6.840 0.600 7.440 ;
    END
  END FrameData[224]
  PIN FrameData[225]
    DIRECTION INPUT ;
    USE SIGNAL ;
    ANTENNAGATEAREA 0.159000 ;
    PORT
      LAYER met3 ;
        RECT 0.000 8.200 0.600 8.800 ;
    END
  END FrameData[225]
  PIN FrameData[226]
    DIRECTION INPUT ;
    USE SIGNAL ;
    ANTENNAGATEAREA 0.159000 ;
    PORT
      LAYER met3 ;
        RECT 0.000 9.560 0.600 10.160 ;
    END
  END FrameData[226]
  PIN FrameData[227]
    DIRECTION INPUT ;
    USE SIGNAL ;
    ANTENNAGATEAREA 0.159000 ;
    PORT
      LAYER met3 ;
        RECT 0.000 10.920 0.600 11.520 ;
    END
  END FrameData[227]
  PIN FrameData[228]
    DIRECTION INPUT ;
    USE SIGNAL ;
    ANTENNAGATEAREA 0.159000 ;
    PORT
      LAYER met3 ;
        RECT 0.000 12.280 0.600 12.880 ;
    END
  END FrameData[228]
  PIN FrameData[229]
    DIRECTION INPUT ;
    USE SIGNAL ;
    ANTENNAGATEAREA 0.159000 ;
    PORT
      LAYER met3 ;
        RECT 0.000 13.640 0.600 14.240 ;
    END
  END FrameData[229]
  PIN FrameData[22]
    DIRECTION INPUT ;
    USE SIGNAL ;
    ANTENNAGATEAREA 0.159000 ;
    PORT
      LAYER met3 ;
        RECT 0.000 1432.120 0.600 1432.720 ;
    END
  END FrameData[22]
  PIN FrameData[230]
    DIRECTION INPUT ;
    USE SIGNAL ;
    ANTENNAGATEAREA 0.159000 ;
    PORT
      LAYER met3 ;
        RECT 0.000 15.000 0.600 15.600 ;
    END
  END FrameData[230]
  PIN FrameData[231]
    DIRECTION INPUT ;
    USE SIGNAL ;
    ANTENNAGATEAREA 0.159000 ;
    PORT
      LAYER met3 ;
        RECT 0.000 16.360 0.600 16.960 ;
    END
  END FrameData[231]
  PIN FrameData[232]
    DIRECTION INPUT ;
    USE SIGNAL ;
    ANTENNAGATEAREA 0.159000 ;
    PORT
      LAYER met3 ;
        RECT 0.000 17.720 0.600 18.320 ;
    END
  END FrameData[232]
  PIN FrameData[233]
    DIRECTION INPUT ;
    USE SIGNAL ;
    ANTENNAGATEAREA 0.159000 ;
    PORT
      LAYER met3 ;
        RECT 0.000 19.080 0.600 19.680 ;
    END
  END FrameData[233]
  PIN FrameData[234]
    DIRECTION INPUT ;
    USE SIGNAL ;
    ANTENNAGATEAREA 0.159000 ;
    PORT
      LAYER met3 ;
        RECT 0.000 20.440 0.600 21.040 ;
    END
  END FrameData[234]
  PIN FrameData[235]
    DIRECTION INPUT ;
    USE SIGNAL ;
    ANTENNAGATEAREA 0.159000 ;
    PORT
      LAYER met3 ;
        RECT 0.000 21.800 0.600 22.400 ;
    END
  END FrameData[235]
  PIN FrameData[236]
    DIRECTION INPUT ;
    USE SIGNAL ;
    ANTENNAGATEAREA 0.318000 ;
    PORT
      LAYER met3 ;
        RECT 0.000 23.160 0.600 23.760 ;
    END
  END FrameData[236]
  PIN FrameData[237]
    DIRECTION INPUT ;
    USE SIGNAL ;
    ANTENNAGATEAREA 0.318000 ;
    PORT
      LAYER met3 ;
        RECT 0.000 24.520 0.600 25.120 ;
    END
  END FrameData[237]
  PIN FrameData[238]
    DIRECTION INPUT ;
    USE SIGNAL ;
    ANTENNAGATEAREA 0.318000 ;
    PORT
      LAYER met3 ;
        RECT 0.000 25.880 0.600 26.480 ;
    END
  END FrameData[238]
  PIN FrameData[239]
    DIRECTION INPUT ;
    USE SIGNAL ;
    ANTENNAGATEAREA 0.318000 ;
    PORT
      LAYER met3 ;
        RECT 0.000 27.240 0.600 27.840 ;
    END
  END FrameData[239]
  PIN FrameData[23]
    DIRECTION INPUT ;
    USE SIGNAL ;
    ANTENNAGATEAREA 0.159000 ;
    PORT
      LAYER met3 ;
        RECT 0.000 1433.480 0.600 1434.080 ;
    END
  END FrameData[23]
  PIN FrameData[240]
    DIRECTION INPUT ;
    USE SIGNAL ;
    ANTENNAGATEAREA 0.318000 ;
    PORT
      LAYER met3 ;
        RECT 0.000 28.600 0.600 29.200 ;
    END
  END FrameData[240]
  PIN FrameData[241]
    DIRECTION INPUT ;
    USE SIGNAL ;
    ANTENNAGATEAREA 0.318000 ;
    PORT
      LAYER met3 ;
        RECT 0.000 29.960 0.600 30.560 ;
    END
  END FrameData[241]
  PIN FrameData[242]
    DIRECTION INPUT ;
    USE SIGNAL ;
    ANTENNAGATEAREA 0.318000 ;
    PORT
      LAYER met3 ;
        RECT 0.000 31.320 0.600 31.920 ;
    END
  END FrameData[242]
  PIN FrameData[243]
    DIRECTION INPUT ;
    USE SIGNAL ;
    ANTENNAGATEAREA 0.318000 ;
    PORT
      LAYER met3 ;
        RECT 0.000 32.680 0.600 33.280 ;
    END
  END FrameData[243]
  PIN FrameData[244]
    DIRECTION INPUT ;
    USE SIGNAL ;
    ANTENNAGATEAREA 0.318000 ;
    PORT
      LAYER met3 ;
        RECT 0.000 34.040 0.600 34.640 ;
    END
  END FrameData[244]
  PIN FrameData[245]
    DIRECTION INPUT ;
    USE SIGNAL ;
    ANTENNAGATEAREA 0.318000 ;
    PORT
      LAYER met3 ;
        RECT 0.000 35.400 0.600 36.000 ;
    END
  END FrameData[245]
  PIN FrameData[246]
    DIRECTION INPUT ;
    USE SIGNAL ;
    ANTENNAGATEAREA 0.318000 ;
    PORT
      LAYER met3 ;
        RECT 0.000 36.760 0.600 37.360 ;
    END
  END FrameData[246]
  PIN FrameData[247]
    DIRECTION INPUT ;
    USE SIGNAL ;
    ANTENNAGATEAREA 0.318000 ;
    PORT
      LAYER met3 ;
        RECT 0.000 38.120 0.600 38.720 ;
    END
  END FrameData[247]
  PIN FrameData[248]
    DIRECTION INPUT ;
    USE SIGNAL ;
    ANTENNAGATEAREA 0.318000 ;
    PORT
      LAYER met3 ;
        RECT 0.000 39.480 0.600 40.080 ;
    END
  END FrameData[248]
  PIN FrameData[249]
    DIRECTION INPUT ;
    USE SIGNAL ;
    ANTENNAGATEAREA 0.318000 ;
    PORT
      LAYER met3 ;
        RECT 0.000 40.840 0.600 41.440 ;
    END
  END FrameData[249]
  PIN FrameData[24]
    DIRECTION INPUT ;
    USE SIGNAL ;
    ANTENNAGATEAREA 0.159000 ;
    PORT
      LAYER met3 ;
        RECT 0.000 1434.840 0.600 1435.440 ;
    END
  END FrameData[24]
  PIN FrameData[250]
    DIRECTION INPUT ;
    USE SIGNAL ;
    ANTENNAGATEAREA 0.318000 ;
    PORT
      LAYER met3 ;
        RECT 0.000 42.200 0.600 42.800 ;
    END
  END FrameData[250]
  PIN FrameData[251]
    DIRECTION INPUT ;
    USE SIGNAL ;
    ANTENNAGATEAREA 0.318000 ;
    PORT
      LAYER met3 ;
        RECT 0.000 43.560 0.600 44.160 ;
    END
  END FrameData[251]
  PIN FrameData[252]
    DIRECTION INPUT ;
    USE SIGNAL ;
    ANTENNAGATEAREA 0.318000 ;
    PORT
      LAYER met3 ;
        RECT 0.000 44.920 0.600 45.520 ;
    END
  END FrameData[252]
  PIN FrameData[253]
    DIRECTION INPUT ;
    USE SIGNAL ;
    ANTENNAGATEAREA 0.318000 ;
    PORT
      LAYER met3 ;
        RECT 0.000 46.280 0.600 46.880 ;
    END
  END FrameData[253]
  PIN FrameData[254]
    DIRECTION INPUT ;
    USE SIGNAL ;
    ANTENNAGATEAREA 0.318000 ;
    PORT
      LAYER met3 ;
        RECT 0.000 47.640 0.600 48.240 ;
    END
  END FrameData[254]
  PIN FrameData[255]
    DIRECTION INPUT ;
    USE SIGNAL ;
    ANTENNAGATEAREA 0.318000 ;
    PORT
      LAYER met3 ;
        RECT 0.000 49.000 0.600 49.600 ;
    END
  END FrameData[255]
  PIN FrameData[25]
    DIRECTION INPUT ;
    USE SIGNAL ;
    ANTENNAGATEAREA 0.159000 ;
    PORT
      LAYER met3 ;
        RECT 0.000 1436.200 0.600 1436.800 ;
    END
  END FrameData[25]
  PIN FrameData[26]
    DIRECTION INPUT ;
    USE SIGNAL ;
    ANTENNAGATEAREA 0.159000 ;
    PORT
      LAYER met3 ;
        RECT 0.000 1437.560 0.600 1438.160 ;
    END
  END FrameData[26]
  PIN FrameData[27]
    DIRECTION INPUT ;
    USE SIGNAL ;
    ANTENNAGATEAREA 0.159000 ;
    PORT
      LAYER met3 ;
        RECT 0.000 1438.920 0.600 1439.520 ;
    END
  END FrameData[27]
  PIN FrameData[28]
    DIRECTION INPUT ;
    USE SIGNAL ;
    ANTENNAGATEAREA 0.318000 ;
    PORT
      LAYER met3 ;
        RECT 0.000 1440.280 0.600 1440.880 ;
    END
  END FrameData[28]
  PIN FrameData[29]
    DIRECTION INPUT ;
    USE SIGNAL ;
    ANTENNAGATEAREA 0.318000 ;
    PORT
      LAYER met3 ;
        RECT 0.000 1441.640 0.600 1442.240 ;
    END
  END FrameData[29]
  PIN FrameData[2]
    DIRECTION INPUT ;
    USE SIGNAL ;
    ANTENNAGATEAREA 0.593700 ;
    ANTENNADIFFAREA 0.434700 ;
    PORT
      LAYER met3 ;
        RECT 0.000 1404.920 0.600 1405.520 ;
    END
  END FrameData[2]
  PIN FrameData[30]
    DIRECTION INPUT ;
    USE SIGNAL ;
    ANTENNAGATEAREA 0.318000 ;
    PORT
      LAYER met3 ;
        RECT 0.000 1443.000 0.600 1443.600 ;
    END
  END FrameData[30]
  PIN FrameData[31]
    DIRECTION INPUT ;
    USE SIGNAL ;
    ANTENNAGATEAREA 0.318000 ;
    PORT
      LAYER met3 ;
        RECT 0.000 1444.360 0.600 1444.960 ;
    END
  END FrameData[31]
  PIN FrameData[32]
    DIRECTION INPUT ;
    USE SIGNAL ;
    ANTENNAGATEAREA 0.636000 ;
    PORT
      LAYER met3 ;
        RECT 0.000 1214.520 0.600 1215.120 ;
    END
  END FrameData[32]
  PIN FrameData[33]
    DIRECTION INPUT ;
    USE SIGNAL ;
    ANTENNAGATEAREA 0.636000 ;
    PORT
      LAYER met3 ;
        RECT 0.000 1219.960 0.600 1220.560 ;
    END
  END FrameData[33]
  PIN FrameData[34]
    DIRECTION INPUT ;
    USE SIGNAL ;
    ANTENNAGATEAREA 0.795000 ;
    PORT
      LAYER met3 ;
        RECT 0.000 1225.400 0.600 1226.000 ;
    END
  END FrameData[34]
  PIN FrameData[35]
    DIRECTION INPUT ;
    USE SIGNAL ;
    ANTENNAGATEAREA 0.795000 ;
    PORT
      LAYER met3 ;
        RECT 0.000 1230.840 0.600 1231.440 ;
    END
  END FrameData[35]
  PIN FrameData[36]
    DIRECTION INPUT ;
    USE SIGNAL ;
    ANTENNAGATEAREA 0.795000 ;
    PORT
      LAYER met3 ;
        RECT 0.000 1236.280 0.600 1236.880 ;
    END
  END FrameData[36]
  PIN FrameData[37]
    DIRECTION INPUT ;
    USE SIGNAL ;
    ANTENNAGATEAREA 0.795000 ;
    PORT
      LAYER met3 ;
        RECT 0.000 1241.720 0.600 1242.320 ;
    END
  END FrameData[37]
  PIN FrameData[38]
    DIRECTION INPUT ;
    USE SIGNAL ;
    ANTENNAGATEAREA 0.795000 ;
    PORT
      LAYER met3 ;
        RECT 0.000 1247.160 0.600 1247.760 ;
    END
  END FrameData[38]
  PIN FrameData[39]
    DIRECTION INPUT ;
    USE SIGNAL ;
    ANTENNAGATEAREA 0.795000 ;
    PORT
      LAYER met3 ;
        RECT 0.000 1252.600 0.600 1253.200 ;
    END
  END FrameData[39]
  PIN FrameData[3]
    DIRECTION INPUT ;
    USE SIGNAL ;
    ANTENNAGATEAREA 0.593700 ;
    ANTENNADIFFAREA 0.434700 ;
    PORT
      LAYER met3 ;
        RECT 0.000 1406.280 0.600 1406.880 ;
    END
  END FrameData[3]
  PIN FrameData[40]
    DIRECTION INPUT ;
    USE SIGNAL ;
    ANTENNAGATEAREA 0.795000 ;
    PORT
      LAYER met3 ;
        RECT 0.000 1258.040 0.600 1258.640 ;
    END
  END FrameData[40]
  PIN FrameData[41]
    DIRECTION INPUT ;
    USE SIGNAL ;
    ANTENNAGATEAREA 0.795000 ;
    PORT
      LAYER met3 ;
        RECT 0.000 1263.480 0.600 1264.080 ;
    END
  END FrameData[41]
  PIN FrameData[42]
    DIRECTION INPUT ;
    USE SIGNAL ;
    ANTENNAGATEAREA 0.795000 ;
    PORT
      LAYER met3 ;
        RECT 0.000 1268.920 0.600 1269.520 ;
    END
  END FrameData[42]
  PIN FrameData[43]
    DIRECTION INPUT ;
    USE SIGNAL ;
    ANTENNAGATEAREA 0.795000 ;
    PORT
      LAYER met3 ;
        RECT 0.000 1274.360 0.600 1274.960 ;
    END
  END FrameData[43]
  PIN FrameData[44]
    DIRECTION INPUT ;
    USE SIGNAL ;
    ANTENNAGATEAREA 0.795000 ;
    PORT
      LAYER met3 ;
        RECT 0.000 1279.800 0.600 1280.400 ;
    END
  END FrameData[44]
  PIN FrameData[45]
    DIRECTION INPUT ;
    USE SIGNAL ;
    ANTENNAGATEAREA 0.795000 ;
    PORT
      LAYER met3 ;
        RECT 0.000 1285.240 0.600 1285.840 ;
    END
  END FrameData[45]
  PIN FrameData[46]
    DIRECTION INPUT ;
    USE SIGNAL ;
    ANTENNAGATEAREA 0.795000 ;
    PORT
      LAYER met3 ;
        RECT 0.000 1290.680 0.600 1291.280 ;
    END
  END FrameData[46]
  PIN FrameData[47]
    DIRECTION INPUT ;
    USE SIGNAL ;
    ANTENNAGATEAREA 0.795000 ;
    PORT
      LAYER met3 ;
        RECT 0.000 1296.120 0.600 1296.720 ;
    END
  END FrameData[47]
  PIN FrameData[48]
    DIRECTION INPUT ;
    USE SIGNAL ;
    ANTENNAGATEAREA 0.795000 ;
    PORT
      LAYER met3 ;
        RECT 0.000 1301.560 0.600 1302.160 ;
    END
  END FrameData[48]
  PIN FrameData[49]
    DIRECTION INPUT ;
    USE SIGNAL ;
    ANTENNAGATEAREA 0.795000 ;
    PORT
      LAYER met3 ;
        RECT 0.000 1307.000 0.600 1307.600 ;
    END
  END FrameData[49]
  PIN FrameData[4]
    DIRECTION INPUT ;
    USE SIGNAL ;
    ANTENNAGATEAREA 0.159000 ;
    PORT
      LAYER met3 ;
        RECT 0.000 1407.640 0.600 1408.240 ;
    END
  END FrameData[4]
  PIN FrameData[50]
    DIRECTION INPUT ;
    USE SIGNAL ;
    ANTENNAGATEAREA 1.229700 ;
    ANTENNADIFFAREA 0.434700 ;
    PORT
      LAYER met3 ;
        RECT 0.000 1312.440 0.600 1313.040 ;
    END
  END FrameData[50]
  PIN FrameData[51]
    DIRECTION INPUT ;
    USE SIGNAL ;
    ANTENNAGATEAREA 0.795000 ;
    PORT
      LAYER met3 ;
        RECT 0.000 1317.880 0.600 1318.480 ;
    END
  END FrameData[51]
  PIN FrameData[52]
    DIRECTION INPUT ;
    USE SIGNAL ;
    ANTENNAGATEAREA 0.795000 ;
    PORT
      LAYER met3 ;
        RECT 0.000 1323.320 0.600 1323.920 ;
    END
  END FrameData[52]
  PIN FrameData[53]
    DIRECTION INPUT ;
    USE SIGNAL ;
    ANTENNAGATEAREA 0.795000 ;
    PORT
      LAYER met3 ;
        RECT 0.000 1328.760 0.600 1329.360 ;
    END
  END FrameData[53]
  PIN FrameData[54]
    DIRECTION INPUT ;
    USE SIGNAL ;
    ANTENNAGATEAREA 1.229700 ;
    ANTENNADIFFAREA 0.434700 ;
    PORT
      LAYER met3 ;
        RECT 0.000 1334.200 0.600 1334.800 ;
    END
  END FrameData[54]
  PIN FrameData[55]
    DIRECTION INPUT ;
    USE SIGNAL ;
    ANTENNAGATEAREA 0.795000 ;
    PORT
      LAYER met3 ;
        RECT 0.000 1339.640 0.600 1340.240 ;
    END
  END FrameData[55]
  PIN FrameData[56]
    DIRECTION INPUT ;
    USE SIGNAL ;
    ANTENNAGATEAREA 0.795000 ;
    PORT
      LAYER met3 ;
        RECT 0.000 1345.080 0.600 1345.680 ;
    END
  END FrameData[56]
  PIN FrameData[57]
    DIRECTION INPUT ;
    USE SIGNAL ;
    ANTENNAGATEAREA 0.795000 ;
    PORT
      LAYER met3 ;
        RECT 0.000 1350.520 0.600 1351.120 ;
    END
  END FrameData[57]
  PIN FrameData[58]
    DIRECTION INPUT ;
    USE SIGNAL ;
    ANTENNAGATEAREA 0.795000 ;
    PORT
      LAYER met3 ;
        RECT 0.000 1355.960 0.600 1356.560 ;
    END
  END FrameData[58]
  PIN FrameData[59]
    DIRECTION INPUT ;
    USE SIGNAL ;
    ANTENNAGATEAREA 0.795000 ;
    PORT
      LAYER met3 ;
        RECT 0.000 1361.400 0.600 1362.000 ;
    END
  END FrameData[59]
  PIN FrameData[5]
    DIRECTION INPUT ;
    USE SIGNAL ;
    ANTENNAGATEAREA 0.593700 ;
    ANTENNADIFFAREA 0.434700 ;
    PORT
      LAYER met3 ;
        RECT 0.000 1409.000 0.600 1409.600 ;
    END
  END FrameData[5]
  PIN FrameData[60]
    DIRECTION INPUT ;
    USE SIGNAL ;
    ANTENNAGATEAREA 0.795000 ;
    PORT
      LAYER met3 ;
        RECT 0.000 1366.840 0.600 1367.440 ;
    END
  END FrameData[60]
  PIN FrameData[61]
    DIRECTION INPUT ;
    USE SIGNAL ;
    ANTENNAGATEAREA 0.795000 ;
    PORT
      LAYER met3 ;
        RECT 0.000 1372.280 0.600 1372.880 ;
    END
  END FrameData[61]
  PIN FrameData[62]
    DIRECTION INPUT ;
    USE SIGNAL ;
    ANTENNAGATEAREA 0.795000 ;
    PORT
      LAYER met3 ;
        RECT 0.000 1377.720 0.600 1378.320 ;
    END
  END FrameData[62]
  PIN FrameData[63]
    DIRECTION INPUT ;
    USE SIGNAL ;
    ANTENNAGATEAREA 0.795000 ;
    PORT
      LAYER met3 ;
        RECT 0.000 1383.160 0.600 1383.760 ;
    END
  END FrameData[63]
  PIN FrameData[64]
    DIRECTION INPUT ;
    USE SIGNAL ;
    ANTENNAGATEAREA 0.636000 ;
    PORT
      LAYER met3 ;
        RECT 0.000 991.480 0.600 992.080 ;
    END
  END FrameData[64]
  PIN FrameData[65]
    DIRECTION INPUT ;
    USE SIGNAL ;
    ANTENNAGATEAREA 0.636000 ;
    PORT
      LAYER met3 ;
        RECT 0.000 996.920 0.600 997.520 ;
    END
  END FrameData[65]
  PIN FrameData[66]
    DIRECTION INPUT ;
    USE SIGNAL ;
    ANTENNAGATEAREA 0.795000 ;
    PORT
      LAYER met3 ;
        RECT 0.000 1002.360 0.600 1002.960 ;
    END
  END FrameData[66]
  PIN FrameData[67]
    DIRECTION INPUT ;
    USE SIGNAL ;
    ANTENNAGATEAREA 0.795000 ;
    PORT
      LAYER met3 ;
        RECT 0.000 1007.800 0.600 1008.400 ;
    END
  END FrameData[67]
  PIN FrameData[68]
    DIRECTION INPUT ;
    USE SIGNAL ;
    ANTENNAGATEAREA 0.795000 ;
    PORT
      LAYER met3 ;
        RECT 0.000 1013.240 0.600 1013.840 ;
    END
  END FrameData[68]
  PIN FrameData[69]
    DIRECTION INPUT ;
    USE SIGNAL ;
    ANTENNAGATEAREA 0.795000 ;
    PORT
      LAYER met3 ;
        RECT 0.000 1018.680 0.600 1019.280 ;
    END
  END FrameData[69]
  PIN FrameData[6]
    DIRECTION INPUT ;
    USE SIGNAL ;
    ANTENNAGATEAREA 0.159000 ;
    PORT
      LAYER met3 ;
        RECT 0.000 1410.360 0.600 1410.960 ;
    END
  END FrameData[6]
  PIN FrameData[70]
    DIRECTION INPUT ;
    USE SIGNAL ;
    ANTENNAGATEAREA 0.795000 ;
    PORT
      LAYER met3 ;
        RECT 0.000 1024.120 0.600 1024.720 ;
    END
  END FrameData[70]
  PIN FrameData[71]
    DIRECTION INPUT ;
    USE SIGNAL ;
    ANTENNAGATEAREA 0.795000 ;
    PORT
      LAYER met3 ;
        RECT 0.000 1029.560 0.600 1030.160 ;
    END
  END FrameData[71]
  PIN FrameData[72]
    DIRECTION INPUT ;
    USE SIGNAL ;
    ANTENNAGATEAREA 0.795000 ;
    PORT
      LAYER met3 ;
        RECT 0.000 1035.000 0.600 1035.600 ;
    END
  END FrameData[72]
  PIN FrameData[73]
    DIRECTION INPUT ;
    USE SIGNAL ;
    ANTENNAGATEAREA 0.795000 ;
    PORT
      LAYER met3 ;
        RECT 0.000 1040.440 0.600 1041.040 ;
    END
  END FrameData[73]
  PIN FrameData[74]
    DIRECTION INPUT ;
    USE SIGNAL ;
    ANTENNAGATEAREA 0.795000 ;
    PORT
      LAYER met3 ;
        RECT 0.000 1045.880 0.600 1046.480 ;
    END
  END FrameData[74]
  PIN FrameData[75]
    DIRECTION INPUT ;
    USE SIGNAL ;
    ANTENNAGATEAREA 0.795000 ;
    PORT
      LAYER met3 ;
        RECT 0.000 1051.320 0.600 1051.920 ;
    END
  END FrameData[75]
  PIN FrameData[76]
    DIRECTION INPUT ;
    USE SIGNAL ;
    ANTENNAGATEAREA 0.795000 ;
    PORT
      LAYER met3 ;
        RECT 0.000 1056.760 0.600 1057.360 ;
    END
  END FrameData[76]
  PIN FrameData[77]
    DIRECTION INPUT ;
    USE SIGNAL ;
    ANTENNAGATEAREA 0.795000 ;
    PORT
      LAYER met3 ;
        RECT 0.000 1062.200 0.600 1062.800 ;
    END
  END FrameData[77]
  PIN FrameData[78]
    DIRECTION INPUT ;
    USE SIGNAL ;
    ANTENNAGATEAREA 0.795000 ;
    PORT
      LAYER met3 ;
        RECT 0.000 1067.640 0.600 1068.240 ;
    END
  END FrameData[78]
  PIN FrameData[79]
    DIRECTION INPUT ;
    USE SIGNAL ;
    ANTENNAGATEAREA 0.795000 ;
    PORT
      LAYER met3 ;
        RECT 0.000 1073.080 0.600 1073.680 ;
    END
  END FrameData[79]
  PIN FrameData[7]
    DIRECTION INPUT ;
    USE SIGNAL ;
    ANTENNAGATEAREA 0.159000 ;
    PORT
      LAYER met3 ;
        RECT 0.000 1411.720 0.600 1412.320 ;
    END
  END FrameData[7]
  PIN FrameData[80]
    DIRECTION INPUT ;
    USE SIGNAL ;
    ANTENNAGATEAREA 0.795000 ;
    PORT
      LAYER met3 ;
        RECT 0.000 1078.520 0.600 1079.120 ;
    END
  END FrameData[80]
  PIN FrameData[81]
    DIRECTION INPUT ;
    USE SIGNAL ;
    ANTENNAGATEAREA 0.795000 ;
    PORT
      LAYER met3 ;
        RECT 0.000 1083.960 0.600 1084.560 ;
    END
  END FrameData[81]
  PIN FrameData[82]
    DIRECTION INPUT ;
    USE SIGNAL ;
    ANTENNAGATEAREA 1.229700 ;
    ANTENNADIFFAREA 0.434700 ;
    PORT
      LAYER met3 ;
        RECT 0.000 1089.400 0.600 1090.000 ;
    END
  END FrameData[82]
  PIN FrameData[83]
    DIRECTION INPUT ;
    USE SIGNAL ;
    ANTENNAGATEAREA 0.795000 ;
    PORT
      LAYER met3 ;
        RECT 0.000 1094.840 0.600 1095.440 ;
    END
  END FrameData[83]
  PIN FrameData[84]
    DIRECTION INPUT ;
    USE SIGNAL ;
    ANTENNAGATEAREA 0.795000 ;
    PORT
      LAYER met3 ;
        RECT 0.000 1100.280 0.600 1100.880 ;
    END
  END FrameData[84]
  PIN FrameData[85]
    DIRECTION INPUT ;
    USE SIGNAL ;
    ANTENNAGATEAREA 0.795000 ;
    PORT
      LAYER met3 ;
        RECT 0.000 1105.720 0.600 1106.320 ;
    END
  END FrameData[85]
  PIN FrameData[86]
    DIRECTION INPUT ;
    USE SIGNAL ;
    ANTENNAGATEAREA 1.229700 ;
    ANTENNADIFFAREA 0.434700 ;
    PORT
      LAYER met3 ;
        RECT 0.000 1111.160 0.600 1111.760 ;
    END
  END FrameData[86]
  PIN FrameData[87]
    DIRECTION INPUT ;
    USE SIGNAL ;
    ANTENNAGATEAREA 0.795000 ;
    PORT
      LAYER met3 ;
        RECT 0.000 1116.600 0.600 1117.200 ;
    END
  END FrameData[87]
  PIN FrameData[88]
    DIRECTION INPUT ;
    USE SIGNAL ;
    ANTENNAGATEAREA 0.795000 ;
    PORT
      LAYER met3 ;
        RECT 0.000 1122.040 0.600 1122.640 ;
    END
  END FrameData[88]
  PIN FrameData[89]
    DIRECTION INPUT ;
    USE SIGNAL ;
    ANTENNAGATEAREA 0.795000 ;
    PORT
      LAYER met3 ;
        RECT 0.000 1127.480 0.600 1128.080 ;
    END
  END FrameData[89]
  PIN FrameData[8]
    DIRECTION INPUT ;
    USE SIGNAL ;
    ANTENNAGATEAREA 0.159000 ;
    PORT
      LAYER met3 ;
        RECT 0.000 1413.080 0.600 1413.680 ;
    END
  END FrameData[8]
  PIN FrameData[90]
    DIRECTION INPUT ;
    USE SIGNAL ;
    ANTENNAGATEAREA 0.795000 ;
    PORT
      LAYER met3 ;
        RECT 0.000 1132.920 0.600 1133.520 ;
    END
  END FrameData[90]
  PIN FrameData[91]
    DIRECTION INPUT ;
    USE SIGNAL ;
    ANTENNAGATEAREA 0.795000 ;
    PORT
      LAYER met3 ;
        RECT 0.000 1138.360 0.600 1138.960 ;
    END
  END FrameData[91]
  PIN FrameData[92]
    DIRECTION INPUT ;
    USE SIGNAL ;
    ANTENNAGATEAREA 0.795000 ;
    PORT
      LAYER met3 ;
        RECT 0.000 1143.800 0.600 1144.400 ;
    END
  END FrameData[92]
  PIN FrameData[93]
    DIRECTION INPUT ;
    USE SIGNAL ;
    ANTENNAGATEAREA 0.795000 ;
    PORT
      LAYER met3 ;
        RECT 0.000 1149.240 0.600 1149.840 ;
    END
  END FrameData[93]
  PIN FrameData[94]
    DIRECTION INPUT ;
    USE SIGNAL ;
    ANTENNAGATEAREA 0.795000 ;
    PORT
      LAYER met3 ;
        RECT 0.000 1154.680 0.600 1155.280 ;
    END
  END FrameData[94]
  PIN FrameData[95]
    DIRECTION INPUT ;
    USE SIGNAL ;
    ANTENNAGATEAREA 0.795000 ;
    PORT
      LAYER met3 ;
        RECT 0.000 1160.120 0.600 1160.720 ;
    END
  END FrameData[95]
  PIN FrameData[96]
    DIRECTION INPUT ;
    USE SIGNAL ;
    ANTENNAGATEAREA 0.636000 ;
    PORT
      LAYER met3 ;
        RECT 0.000 768.440 0.600 769.040 ;
    END
  END FrameData[96]
  PIN FrameData[97]
    DIRECTION INPUT ;
    USE SIGNAL ;
    ANTENNAGATEAREA 0.636000 ;
    PORT
      LAYER met3 ;
        RECT 0.000 773.880 0.600 774.480 ;
    END
  END FrameData[97]
  PIN FrameData[98]
    DIRECTION INPUT ;
    USE SIGNAL ;
    ANTENNAGATEAREA 0.795000 ;
    PORT
      LAYER met3 ;
        RECT 0.000 779.320 0.600 779.920 ;
    END
  END FrameData[98]
  PIN FrameData[99]
    DIRECTION INPUT ;
    USE SIGNAL ;
    ANTENNAGATEAREA 0.795000 ;
    PORT
      LAYER met3 ;
        RECT 0.000 784.760 0.600 785.360 ;
    END
  END FrameData[99]
  PIN FrameData[9]
    DIRECTION INPUT ;
    USE SIGNAL ;
    ANTENNAGATEAREA 0.159000 ;
    PORT
      LAYER met3 ;
        RECT 0.000 1414.440 0.600 1415.040 ;
    END
  END FrameData[9]
  PIN FrameStrobe[0]
    DIRECTION INPUT ;
    USE SIGNAL ;
    ANTENNAGATEAREA 3.339000 ;
    PORT
      LAYER met2 ;
        RECT 6.990 0.000 7.270 0.280 ;
    END
  END FrameStrobe[0]
  PIN FrameStrobe[100]
    DIRECTION INPUT ;
    USE SIGNAL ;
    ANTENNAGATEAREA 0.795000 ;
    PORT
      LAYER met2 ;
        RECT 900.310 0.000 900.590 0.280 ;
    END
  END FrameStrobe[100]
  PIN FrameStrobe[101]
    DIRECTION INPUT ;
    USE SIGNAL ;
    ANTENNAGATEAREA 0.159000 ;
    PORT
      LAYER met2 ;
        RECT 903.070 0.000 903.350 0.280 ;
    END
  END FrameStrobe[101]
  PIN FrameStrobe[102]
    DIRECTION INPUT ;
    USE SIGNAL ;
    ANTENNAGATEAREA 0.159000 ;
    PORT
      LAYER met2 ;
        RECT 905.830 0.000 906.110 0.280 ;
    END
  END FrameStrobe[102]
  PIN FrameStrobe[103]
    DIRECTION INPUT ;
    USE SIGNAL ;
    ANTENNAGATEAREA 0.159000 ;
    PORT
      LAYER met2 ;
        RECT 908.590 0.000 908.870 0.280 ;
    END
  END FrameStrobe[103]
  PIN FrameStrobe[104]
    DIRECTION INPUT ;
    USE SIGNAL ;
    ANTENNAGATEAREA 0.159000 ;
    PORT
      LAYER met2 ;
        RECT 911.350 0.000 911.630 0.280 ;
    END
  END FrameStrobe[104]
  PIN FrameStrobe[105]
    DIRECTION INPUT ;
    USE SIGNAL ;
    ANTENNAGATEAREA 0.159000 ;
    PORT
      LAYER met2 ;
        RECT 914.110 0.000 914.390 0.280 ;
    END
  END FrameStrobe[105]
  PIN FrameStrobe[106]
    DIRECTION INPUT ;
    USE SIGNAL ;
    ANTENNAGATEAREA 0.159000 ;
    PORT
      LAYER met2 ;
        RECT 916.870 0.000 917.150 0.280 ;
    END
  END FrameStrobe[106]
  PIN FrameStrobe[107]
    DIRECTION INPUT ;
    USE SIGNAL ;
    ANTENNAGATEAREA 0.159000 ;
    PORT
      LAYER met2 ;
        RECT 919.630 0.000 919.910 0.280 ;
    END
  END FrameStrobe[107]
  PIN FrameStrobe[108]
    DIRECTION INPUT ;
    USE SIGNAL ;
    ANTENNAGATEAREA 0.159000 ;
    PORT
      LAYER met2 ;
        RECT 922.390 0.000 922.670 0.280 ;
    END
  END FrameStrobe[108]
  PIN FrameStrobe[109]
    DIRECTION INPUT ;
    USE SIGNAL ;
    ANTENNAGATEAREA 0.159000 ;
    PORT
      LAYER met2 ;
        RECT 925.150 0.000 925.430 0.280 ;
    END
  END FrameStrobe[109]
  PIN FrameStrobe[10]
    DIRECTION INPUT ;
    USE SIGNAL ;
    ANTENNAGATEAREA 0.159000 ;
    PORT
      LAYER met2 ;
        RECT 29.990 0.000 30.270 0.280 ;
    END
  END FrameStrobe[10]
  PIN FrameStrobe[110]
    DIRECTION INPUT ;
    USE SIGNAL ;
    ANTENNAGATEAREA 0.159000 ;
    PORT
      LAYER met2 ;
        RECT 927.910 0.000 928.190 0.280 ;
    END
  END FrameStrobe[110]
  PIN FrameStrobe[111]
    DIRECTION INPUT ;
    USE SIGNAL ;
    ANTENNAGATEAREA 0.159000 ;
    PORT
      LAYER met2 ;
        RECT 930.670 0.000 930.950 0.280 ;
    END
  END FrameStrobe[111]
  PIN FrameStrobe[112]
    DIRECTION INPUT ;
    USE SIGNAL ;
    ANTENNAGATEAREA 0.159000 ;
    PORT
      LAYER met2 ;
        RECT 933.430 0.000 933.710 0.280 ;
    END
  END FrameStrobe[112]
  PIN FrameStrobe[113]
    DIRECTION INPUT ;
    USE SIGNAL ;
    ANTENNAGATEAREA 0.159000 ;
    PORT
      LAYER met2 ;
        RECT 936.190 0.000 936.470 0.280 ;
    END
  END FrameStrobe[113]
  PIN FrameStrobe[114]
    DIRECTION INPUT ;
    USE SIGNAL ;
    ANTENNAGATEAREA 0.159000 ;
    PORT
      LAYER met2 ;
        RECT 938.950 0.000 939.230 0.280 ;
    END
  END FrameStrobe[114]
  PIN FrameStrobe[115]
    DIRECTION INPUT ;
    USE SIGNAL ;
    ANTENNAGATEAREA 0.159000 ;
    PORT
      LAYER met2 ;
        RECT 941.710 0.000 941.990 0.280 ;
    END
  END FrameStrobe[115]
  PIN FrameStrobe[116]
    DIRECTION INPUT ;
    USE SIGNAL ;
    ANTENNAGATEAREA 0.159000 ;
    PORT
      LAYER met2 ;
        RECT 944.470 0.000 944.750 0.280 ;
    END
  END FrameStrobe[116]
  PIN FrameStrobe[117]
    DIRECTION INPUT ;
    USE SIGNAL ;
    ANTENNAGATEAREA 0.159000 ;
    PORT
      LAYER met2 ;
        RECT 947.230 0.000 947.510 0.280 ;
    END
  END FrameStrobe[117]
  PIN FrameStrobe[118]
    DIRECTION INPUT ;
    USE SIGNAL ;
    ANTENNAGATEAREA 0.159000 ;
    PORT
      LAYER met2 ;
        RECT 949.990 0.000 950.270 0.280 ;
    END
  END FrameStrobe[118]
  PIN FrameStrobe[119]
    DIRECTION INPUT ;
    USE SIGNAL ;
    ANTENNAGATEAREA 0.159000 ;
    PORT
      LAYER met2 ;
        RECT 952.750 0.000 953.030 0.280 ;
    END
  END FrameStrobe[119]
  PIN FrameStrobe[11]
    DIRECTION INPUT ;
    USE SIGNAL ;
    ANTENNAGATEAREA 0.159000 ;
    PORT
      LAYER met2 ;
        RECT 32.290 0.000 32.570 0.280 ;
    END
  END FrameStrobe[11]
  PIN FrameStrobe[12]
    DIRECTION INPUT ;
    USE SIGNAL ;
    ANTENNAGATEAREA 0.159000 ;
    PORT
      LAYER met2 ;
        RECT 34.590 0.000 34.870 0.280 ;
    END
  END FrameStrobe[12]
  PIN FrameStrobe[13]
    DIRECTION INPUT ;
    USE SIGNAL ;
    ANTENNAGATEAREA 0.159000 ;
    PORT
      LAYER met2 ;
        RECT 36.890 0.000 37.170 0.280 ;
    END
  END FrameStrobe[13]
  PIN FrameStrobe[14]
    DIRECTION INPUT ;
    USE SIGNAL ;
    ANTENNAGATEAREA 0.159000 ;
    PORT
      LAYER met2 ;
        RECT 39.190 0.000 39.470 0.280 ;
    END
  END FrameStrobe[14]
  PIN FrameStrobe[15]
    DIRECTION INPUT ;
    USE SIGNAL ;
    ANTENNAGATEAREA 0.159000 ;
    PORT
      LAYER met2 ;
        RECT 41.490 0.000 41.770 0.280 ;
    END
  END FrameStrobe[15]
  PIN FrameStrobe[16]
    DIRECTION INPUT ;
    USE SIGNAL ;
    ANTENNAGATEAREA 0.159000 ;
    PORT
      LAYER met2 ;
        RECT 43.790 0.000 44.070 0.280 ;
    END
  END FrameStrobe[16]
  PIN FrameStrobe[17]
    DIRECTION INPUT ;
    USE SIGNAL ;
    ANTENNAGATEAREA 0.159000 ;
    PORT
      LAYER met2 ;
        RECT 46.090 0.000 46.370 0.280 ;
    END
  END FrameStrobe[17]
  PIN FrameStrobe[18]
    DIRECTION INPUT ;
    USE SIGNAL ;
    ANTENNAGATEAREA 0.159000 ;
    PORT
      LAYER met2 ;
        RECT 48.390 0.000 48.670 0.280 ;
    END
  END FrameStrobe[18]
  PIN FrameStrobe[19]
    DIRECTION INPUT ;
    USE SIGNAL ;
    ANTENNAGATEAREA 0.159000 ;
    PORT
      LAYER met2 ;
        RECT 50.690 0.000 50.970 0.280 ;
    END
  END FrameStrobe[19]
  PIN FrameStrobe[1]
    DIRECTION INPUT ;
    USE SIGNAL ;
    ANTENNAGATEAREA 0.159000 ;
    PORT
      LAYER met2 ;
        RECT 9.290 0.000 9.570 0.280 ;
    END
  END FrameStrobe[1]
  PIN FrameStrobe[20]
    DIRECTION INPUT ;
    USE SIGNAL ;
    ANTENNAGATEAREA 1.431000 ;
    PORT
      LAYER met2 ;
        RECT 64.950 0.000 65.230 0.280 ;
    END
  END FrameStrobe[20]
  PIN FrameStrobe[21]
    DIRECTION INPUT ;
    USE SIGNAL ;
    ANTENNAGATEAREA 0.159000 ;
    PORT
      LAYER met2 ;
        RECT 75.070 0.000 75.350 0.280 ;
    END
  END FrameStrobe[21]
  PIN FrameStrobe[22]
    DIRECTION INPUT ;
    USE SIGNAL ;
    ANTENNAGATEAREA 0.159000 ;
    PORT
      LAYER met2 ;
        RECT 85.190 0.000 85.470 0.280 ;
    END
  END FrameStrobe[22]
  PIN FrameStrobe[23]
    DIRECTION INPUT ;
    USE SIGNAL ;
    ANTENNAGATEAREA 0.159000 ;
    PORT
      LAYER met2 ;
        RECT 95.310 0.000 95.590 0.280 ;
    END
  END FrameStrobe[23]
  PIN FrameStrobe[24]
    DIRECTION INPUT ;
    USE SIGNAL ;
    ANTENNAGATEAREA 0.159000 ;
    PORT
      LAYER met2 ;
        RECT 105.430 0.000 105.710 0.280 ;
    END
  END FrameStrobe[24]
  PIN FrameStrobe[25]
    DIRECTION INPUT ;
    USE SIGNAL ;
    ANTENNAGATEAREA 0.159000 ;
    PORT
      LAYER met2 ;
        RECT 115.550 0.000 115.830 0.280 ;
    END
  END FrameStrobe[25]
  PIN FrameStrobe[26]
    DIRECTION INPUT ;
    USE SIGNAL ;
    ANTENNAGATEAREA 0.159000 ;
    PORT
      LAYER met2 ;
        RECT 125.670 0.000 125.950 0.280 ;
    END
  END FrameStrobe[26]
  PIN FrameStrobe[27]
    DIRECTION INPUT ;
    USE SIGNAL ;
    ANTENNAGATEAREA 0.159000 ;
    PORT
      LAYER met2 ;
        RECT 135.790 0.000 136.070 0.280 ;
    END
  END FrameStrobe[27]
  PIN FrameStrobe[28]
    DIRECTION INPUT ;
    USE SIGNAL ;
    ANTENNAGATEAREA 0.159000 ;
    PORT
      LAYER met2 ;
        RECT 145.910 0.000 146.190 0.280 ;
    END
  END FrameStrobe[28]
  PIN FrameStrobe[29]
    DIRECTION INPUT ;
    USE SIGNAL ;
    ANTENNAGATEAREA 0.159000 ;
    PORT
      LAYER met2 ;
        RECT 156.030 0.000 156.310 0.280 ;
    END
  END FrameStrobe[29]
  PIN FrameStrobe[2]
    DIRECTION INPUT ;
    USE SIGNAL ;
    ANTENNAGATEAREA 0.159000 ;
    PORT
      LAYER met2 ;
        RECT 11.590 0.000 11.870 0.280 ;
    END
  END FrameStrobe[2]
  PIN FrameStrobe[30]
    DIRECTION INPUT ;
    USE SIGNAL ;
    ANTENNAGATEAREA 0.159000 ;
    PORT
      LAYER met2 ;
        RECT 166.150 0.000 166.430 0.280 ;
    END
  END FrameStrobe[30]
  PIN FrameStrobe[31]
    DIRECTION INPUT ;
    USE SIGNAL ;
    ANTENNAGATEAREA 0.159000 ;
    PORT
      LAYER met2 ;
        RECT 176.270 0.000 176.550 0.280 ;
    END
  END FrameStrobe[31]
  PIN FrameStrobe[32]
    DIRECTION INPUT ;
    USE SIGNAL ;
    ANTENNAGATEAREA 0.159000 ;
    PORT
      LAYER met2 ;
        RECT 186.390 0.000 186.670 0.280 ;
    END
  END FrameStrobe[32]
  PIN FrameStrobe[33]
    DIRECTION INPUT ;
    USE SIGNAL ;
    ANTENNAGATEAREA 0.159000 ;
    PORT
      LAYER met2 ;
        RECT 196.510 0.000 196.790 0.280 ;
    END
  END FrameStrobe[33]
  PIN FrameStrobe[34]
    DIRECTION INPUT ;
    USE SIGNAL ;
    ANTENNAGATEAREA 0.159000 ;
    PORT
      LAYER met2 ;
        RECT 206.630 0.000 206.910 0.280 ;
    END
  END FrameStrobe[34]
  PIN FrameStrobe[35]
    DIRECTION INPUT ;
    USE SIGNAL ;
    ANTENNAGATEAREA 0.159000 ;
    PORT
      LAYER met2 ;
        RECT 216.750 0.000 217.030 0.280 ;
    END
  END FrameStrobe[35]
  PIN FrameStrobe[36]
    DIRECTION INPUT ;
    USE SIGNAL ;
    ANTENNAGATEAREA 0.159000 ;
    PORT
      LAYER met2 ;
        RECT 226.870 0.000 227.150 0.280 ;
    END
  END FrameStrobe[36]
  PIN FrameStrobe[37]
    DIRECTION INPUT ;
    USE SIGNAL ;
    ANTENNAGATEAREA 0.159000 ;
    PORT
      LAYER met2 ;
        RECT 236.990 0.000 237.270 0.280 ;
    END
  END FrameStrobe[37]
  PIN FrameStrobe[38]
    DIRECTION INPUT ;
    USE SIGNAL ;
    ANTENNAGATEAREA 0.159000 ;
    PORT
      LAYER met2 ;
        RECT 247.110 0.000 247.390 0.280 ;
    END
  END FrameStrobe[38]
  PIN FrameStrobe[39]
    DIRECTION INPUT ;
    USE SIGNAL ;
    ANTENNAGATEAREA 0.159000 ;
    PORT
      LAYER met2 ;
        RECT 257.230 0.000 257.510 0.280 ;
    END
  END FrameStrobe[39]
  PIN FrameStrobe[3]
    DIRECTION INPUT ;
    USE SIGNAL ;
    ANTENNAGATEAREA 0.159000 ;
    PORT
      LAYER met2 ;
        RECT 13.890 0.000 14.170 0.280 ;
    END
  END FrameStrobe[3]
  PIN FrameStrobe[40]
    DIRECTION INPUT ;
    USE SIGNAL ;
    ANTENNAGATEAREA 1.431000 ;
    PORT
      LAYER met2 ;
        RECT 275.630 0.000 275.910 0.280 ;
    END
  END FrameStrobe[40]
  PIN FrameStrobe[41]
    DIRECTION INPUT ;
    USE SIGNAL ;
    ANTENNAGATEAREA 0.159000 ;
    PORT
      LAYER met2 ;
        RECT 285.750 0.000 286.030 0.280 ;
    END
  END FrameStrobe[41]
  PIN FrameStrobe[42]
    DIRECTION INPUT ;
    USE SIGNAL ;
    ANTENNAGATEAREA 0.159000 ;
    PORT
      LAYER met2 ;
        RECT 295.870 0.000 296.150 0.280 ;
    END
  END FrameStrobe[42]
  PIN FrameStrobe[43]
    DIRECTION INPUT ;
    USE SIGNAL ;
    ANTENNAGATEAREA 0.159000 ;
    PORT
      LAYER met2 ;
        RECT 305.990 0.000 306.270 0.280 ;
    END
  END FrameStrobe[43]
  PIN FrameStrobe[44]
    DIRECTION INPUT ;
    USE SIGNAL ;
    ANTENNAGATEAREA 0.159000 ;
    PORT
      LAYER met2 ;
        RECT 316.110 0.000 316.390 0.280 ;
    END
  END FrameStrobe[44]
  PIN FrameStrobe[45]
    DIRECTION INPUT ;
    USE SIGNAL ;
    ANTENNAGATEAREA 0.159000 ;
    PORT
      LAYER met2 ;
        RECT 326.230 0.000 326.510 0.280 ;
    END
  END FrameStrobe[45]
  PIN FrameStrobe[46]
    DIRECTION INPUT ;
    USE SIGNAL ;
    ANTENNAGATEAREA 0.159000 ;
    PORT
      LAYER met2 ;
        RECT 336.350 0.000 336.630 0.280 ;
    END
  END FrameStrobe[46]
  PIN FrameStrobe[47]
    DIRECTION INPUT ;
    USE SIGNAL ;
    ANTENNAGATEAREA 0.159000 ;
    PORT
      LAYER met2 ;
        RECT 346.470 0.000 346.750 0.280 ;
    END
  END FrameStrobe[47]
  PIN FrameStrobe[48]
    DIRECTION INPUT ;
    USE SIGNAL ;
    ANTENNAGATEAREA 0.159000 ;
    PORT
      LAYER met2 ;
        RECT 356.590 0.000 356.870 0.280 ;
    END
  END FrameStrobe[48]
  PIN FrameStrobe[49]
    DIRECTION INPUT ;
    USE SIGNAL ;
    ANTENNAGATEAREA 0.159000 ;
    PORT
      LAYER met2 ;
        RECT 366.710 0.000 366.990 0.280 ;
    END
  END FrameStrobe[49]
  PIN FrameStrobe[4]
    DIRECTION INPUT ;
    USE SIGNAL ;
    ANTENNAGATEAREA 0.159000 ;
    PORT
      LAYER met2 ;
        RECT 16.190 0.000 16.470 0.280 ;
    END
  END FrameStrobe[4]
  PIN FrameStrobe[50]
    DIRECTION INPUT ;
    USE SIGNAL ;
    ANTENNAGATEAREA 0.159000 ;
    PORT
      LAYER met2 ;
        RECT 376.830 0.000 377.110 0.280 ;
    END
  END FrameStrobe[50]
  PIN FrameStrobe[51]
    DIRECTION INPUT ;
    USE SIGNAL ;
    ANTENNAGATEAREA 0.159000 ;
    PORT
      LAYER met2 ;
        RECT 386.950 0.000 387.230 0.280 ;
    END
  END FrameStrobe[51]
  PIN FrameStrobe[52]
    DIRECTION INPUT ;
    USE SIGNAL ;
    ANTENNAGATEAREA 0.159000 ;
    PORT
      LAYER met2 ;
        RECT 397.070 0.000 397.350 0.280 ;
    END
  END FrameStrobe[52]
  PIN FrameStrobe[53]
    DIRECTION INPUT ;
    USE SIGNAL ;
    ANTENNAGATEAREA 0.159000 ;
    PORT
      LAYER met2 ;
        RECT 407.190 0.000 407.470 0.280 ;
    END
  END FrameStrobe[53]
  PIN FrameStrobe[54]
    DIRECTION INPUT ;
    USE SIGNAL ;
    ANTENNAGATEAREA 0.159000 ;
    PORT
      LAYER met2 ;
        RECT 417.310 0.000 417.590 0.280 ;
    END
  END FrameStrobe[54]
  PIN FrameStrobe[55]
    DIRECTION INPUT ;
    USE SIGNAL ;
    ANTENNAGATEAREA 0.159000 ;
    PORT
      LAYER met2 ;
        RECT 427.430 0.000 427.710 0.280 ;
    END
  END FrameStrobe[55]
  PIN FrameStrobe[56]
    DIRECTION INPUT ;
    USE SIGNAL ;
    ANTENNAGATEAREA 0.159000 ;
    PORT
      LAYER met2 ;
        RECT 437.550 0.000 437.830 0.280 ;
    END
  END FrameStrobe[56]
  PIN FrameStrobe[57]
    DIRECTION INPUT ;
    USE SIGNAL ;
    ANTENNAGATEAREA 0.159000 ;
    PORT
      LAYER met2 ;
        RECT 447.670 0.000 447.950 0.280 ;
    END
  END FrameStrobe[57]
  PIN FrameStrobe[58]
    DIRECTION INPUT ;
    USE SIGNAL ;
    ANTENNAGATEAREA 0.159000 ;
    PORT
      LAYER met2 ;
        RECT 457.790 0.000 458.070 0.280 ;
    END
  END FrameStrobe[58]
  PIN FrameStrobe[59]
    DIRECTION INPUT ;
    USE SIGNAL ;
    ANTENNAGATEAREA 0.159000 ;
    PORT
      LAYER met2 ;
        RECT 467.910 0.000 468.190 0.280 ;
    END
  END FrameStrobe[59]
  PIN FrameStrobe[5]
    DIRECTION INPUT ;
    USE SIGNAL ;
    ANTENNAGATEAREA 0.159000 ;
    PORT
      LAYER met2 ;
        RECT 18.490 0.000 18.770 0.280 ;
    END
  END FrameStrobe[5]
  PIN FrameStrobe[60]
    DIRECTION INPUT ;
    USE SIGNAL ;
    ANTENNAGATEAREA 1.431000 ;
    PORT
      LAYER met2 ;
        RECT 486.310 0.000 486.590 0.280 ;
    END
  END FrameStrobe[60]
  PIN FrameStrobe[61]
    DIRECTION INPUT ;
    USE SIGNAL ;
    ANTENNAGATEAREA 0.159000 ;
    PORT
      LAYER met2 ;
        RECT 496.430 0.000 496.710 0.280 ;
    END
  END FrameStrobe[61]
  PIN FrameStrobe[62]
    DIRECTION INPUT ;
    USE SIGNAL ;
    ANTENNAGATEAREA 0.159000 ;
    PORT
      LAYER met2 ;
        RECT 506.550 0.000 506.830 0.280 ;
    END
  END FrameStrobe[62]
  PIN FrameStrobe[63]
    DIRECTION INPUT ;
    USE SIGNAL ;
    ANTENNAGATEAREA 0.159000 ;
    PORT
      LAYER met2 ;
        RECT 516.670 0.000 516.950 0.280 ;
    END
  END FrameStrobe[63]
  PIN FrameStrobe[64]
    DIRECTION INPUT ;
    USE SIGNAL ;
    ANTENNAGATEAREA 0.159000 ;
    PORT
      LAYER met2 ;
        RECT 526.790 0.000 527.070 0.280 ;
    END
  END FrameStrobe[64]
  PIN FrameStrobe[65]
    DIRECTION INPUT ;
    USE SIGNAL ;
    ANTENNAGATEAREA 0.159000 ;
    PORT
      LAYER met2 ;
        RECT 536.910 0.000 537.190 0.280 ;
    END
  END FrameStrobe[65]
  PIN FrameStrobe[66]
    DIRECTION INPUT ;
    USE SIGNAL ;
    ANTENNAGATEAREA 0.159000 ;
    PORT
      LAYER met2 ;
        RECT 547.030 0.000 547.310 0.280 ;
    END
  END FrameStrobe[66]
  PIN FrameStrobe[67]
    DIRECTION INPUT ;
    USE SIGNAL ;
    ANTENNAGATEAREA 0.159000 ;
    PORT
      LAYER met2 ;
        RECT 557.150 0.000 557.430 0.280 ;
    END
  END FrameStrobe[67]
  PIN FrameStrobe[68]
    DIRECTION INPUT ;
    USE SIGNAL ;
    ANTENNAGATEAREA 0.159000 ;
    PORT
      LAYER met2 ;
        RECT 567.270 0.000 567.550 0.280 ;
    END
  END FrameStrobe[68]
  PIN FrameStrobe[69]
    DIRECTION INPUT ;
    USE SIGNAL ;
    ANTENNAGATEAREA 0.159000 ;
    PORT
      LAYER met2 ;
        RECT 577.390 0.000 577.670 0.280 ;
    END
  END FrameStrobe[69]
  PIN FrameStrobe[6]
    DIRECTION INPUT ;
    USE SIGNAL ;
    ANTENNAGATEAREA 0.159000 ;
    PORT
      LAYER met2 ;
        RECT 20.790 0.000 21.070 0.280 ;
    END
  END FrameStrobe[6]
  PIN FrameStrobe[70]
    DIRECTION INPUT ;
    USE SIGNAL ;
    ANTENNAGATEAREA 0.159000 ;
    PORT
      LAYER met2 ;
        RECT 587.510 0.000 587.790 0.280 ;
    END
  END FrameStrobe[70]
  PIN FrameStrobe[71]
    DIRECTION INPUT ;
    USE SIGNAL ;
    ANTENNAGATEAREA 0.159000 ;
    PORT
      LAYER met2 ;
        RECT 597.630 0.000 597.910 0.280 ;
    END
  END FrameStrobe[71]
  PIN FrameStrobe[72]
    DIRECTION INPUT ;
    USE SIGNAL ;
    ANTENNAGATEAREA 0.159000 ;
    PORT
      LAYER met2 ;
        RECT 607.750 0.000 608.030 0.280 ;
    END
  END FrameStrobe[72]
  PIN FrameStrobe[73]
    DIRECTION INPUT ;
    USE SIGNAL ;
    ANTENNAGATEAREA 0.159000 ;
    PORT
      LAYER met2 ;
        RECT 617.870 0.000 618.150 0.280 ;
    END
  END FrameStrobe[73]
  PIN FrameStrobe[74]
    DIRECTION INPUT ;
    USE SIGNAL ;
    ANTENNAGATEAREA 0.159000 ;
    PORT
      LAYER met2 ;
        RECT 627.990 0.000 628.270 0.280 ;
    END
  END FrameStrobe[74]
  PIN FrameStrobe[75]
    DIRECTION INPUT ;
    USE SIGNAL ;
    ANTENNAGATEAREA 0.159000 ;
    PORT
      LAYER met2 ;
        RECT 638.110 0.000 638.390 0.280 ;
    END
  END FrameStrobe[75]
  PIN FrameStrobe[76]
    DIRECTION INPUT ;
    USE SIGNAL ;
    ANTENNAGATEAREA 0.159000 ;
    PORT
      LAYER met2 ;
        RECT 648.230 0.000 648.510 0.280 ;
    END
  END FrameStrobe[76]
  PIN FrameStrobe[77]
    DIRECTION INPUT ;
    USE SIGNAL ;
    ANTENNAGATEAREA 0.159000 ;
    PORT
      LAYER met2 ;
        RECT 658.350 0.000 658.630 0.280 ;
    END
  END FrameStrobe[77]
  PIN FrameStrobe[78]
    DIRECTION INPUT ;
    USE SIGNAL ;
    ANTENNAGATEAREA 0.159000 ;
    PORT
      LAYER met2 ;
        RECT 668.470 0.000 668.750 0.280 ;
    END
  END FrameStrobe[78]
  PIN FrameStrobe[79]
    DIRECTION INPUT ;
    USE SIGNAL ;
    ANTENNAGATEAREA 0.159000 ;
    PORT
      LAYER met2 ;
        RECT 678.590 0.000 678.870 0.280 ;
    END
  END FrameStrobe[79]
  PIN FrameStrobe[7]
    DIRECTION INPUT ;
    USE SIGNAL ;
    ANTENNAGATEAREA 0.159000 ;
    PORT
      LAYER met2 ;
        RECT 23.090 0.000 23.370 0.280 ;
    END
  END FrameStrobe[7]
  PIN FrameStrobe[80]
    DIRECTION INPUT ;
    USE SIGNAL ;
    ANTENNAGATEAREA 1.431000 ;
    PORT
      LAYER met2 ;
        RECT 696.990 0.000 697.270 0.280 ;
    END
  END FrameStrobe[80]
  PIN FrameStrobe[81]
    DIRECTION INPUT ;
    USE SIGNAL ;
    ANTENNAGATEAREA 0.159000 ;
    PORT
      LAYER met2 ;
        RECT 707.110 0.000 707.390 0.280 ;
    END
  END FrameStrobe[81]
  PIN FrameStrobe[82]
    DIRECTION INPUT ;
    USE SIGNAL ;
    ANTENNAGATEAREA 0.159000 ;
    PORT
      LAYER met2 ;
        RECT 717.230 0.000 717.510 0.280 ;
    END
  END FrameStrobe[82]
  PIN FrameStrobe[83]
    DIRECTION INPUT ;
    USE SIGNAL ;
    ANTENNAGATEAREA 0.159000 ;
    PORT
      LAYER met2 ;
        RECT 727.350 0.000 727.630 0.280 ;
    END
  END FrameStrobe[83]
  PIN FrameStrobe[84]
    DIRECTION INPUT ;
    USE SIGNAL ;
    ANTENNAGATEAREA 0.159000 ;
    PORT
      LAYER met2 ;
        RECT 737.470 0.000 737.750 0.280 ;
    END
  END FrameStrobe[84]
  PIN FrameStrobe[85]
    DIRECTION INPUT ;
    USE SIGNAL ;
    ANTENNAGATEAREA 0.159000 ;
    PORT
      LAYER met2 ;
        RECT 747.590 0.000 747.870 0.280 ;
    END
  END FrameStrobe[85]
  PIN FrameStrobe[86]
    DIRECTION INPUT ;
    USE SIGNAL ;
    ANTENNAGATEAREA 0.159000 ;
    PORT
      LAYER met2 ;
        RECT 757.710 0.000 757.990 0.280 ;
    END
  END FrameStrobe[86]
  PIN FrameStrobe[87]
    DIRECTION INPUT ;
    USE SIGNAL ;
    ANTENNAGATEAREA 0.159000 ;
    PORT
      LAYER met2 ;
        RECT 767.830 0.000 768.110 0.280 ;
    END
  END FrameStrobe[87]
  PIN FrameStrobe[88]
    DIRECTION INPUT ;
    USE SIGNAL ;
    ANTENNAGATEAREA 0.159000 ;
    PORT
      LAYER met2 ;
        RECT 777.950 0.000 778.230 0.280 ;
    END
  END FrameStrobe[88]
  PIN FrameStrobe[89]
    DIRECTION INPUT ;
    USE SIGNAL ;
    ANTENNAGATEAREA 0.159000 ;
    PORT
      LAYER met2 ;
        RECT 788.070 0.000 788.350 0.280 ;
    END
  END FrameStrobe[89]
  PIN FrameStrobe[8]
    DIRECTION INPUT ;
    USE SIGNAL ;
    ANTENNAGATEAREA 0.159000 ;
    PORT
      LAYER met2 ;
        RECT 25.390 0.000 25.670 0.280 ;
    END
  END FrameStrobe[8]
  PIN FrameStrobe[90]
    DIRECTION INPUT ;
    USE SIGNAL ;
    ANTENNAGATEAREA 0.159000 ;
    PORT
      LAYER met2 ;
        RECT 798.190 0.000 798.470 0.280 ;
    END
  END FrameStrobe[90]
  PIN FrameStrobe[91]
    DIRECTION INPUT ;
    USE SIGNAL ;
    ANTENNAGATEAREA 0.159000 ;
    PORT
      LAYER met2 ;
        RECT 808.310 0.000 808.590 0.280 ;
    END
  END FrameStrobe[91]
  PIN FrameStrobe[92]
    DIRECTION INPUT ;
    USE SIGNAL ;
    ANTENNAGATEAREA 0.159000 ;
    PORT
      LAYER met2 ;
        RECT 818.430 0.000 818.710 0.280 ;
    END
  END FrameStrobe[92]
  PIN FrameStrobe[93]
    DIRECTION INPUT ;
    USE SIGNAL ;
    ANTENNAGATEAREA 0.159000 ;
    PORT
      LAYER met2 ;
        RECT 828.550 0.000 828.830 0.280 ;
    END
  END FrameStrobe[93]
  PIN FrameStrobe[94]
    DIRECTION INPUT ;
    USE SIGNAL ;
    ANTENNAGATEAREA 0.159000 ;
    PORT
      LAYER met2 ;
        RECT 838.670 0.000 838.950 0.280 ;
    END
  END FrameStrobe[94]
  PIN FrameStrobe[95]
    DIRECTION INPUT ;
    USE SIGNAL ;
    ANTENNAGATEAREA 0.159000 ;
    PORT
      LAYER met2 ;
        RECT 848.790 0.000 849.070 0.280 ;
    END
  END FrameStrobe[95]
  PIN FrameStrobe[96]
    DIRECTION INPUT ;
    USE SIGNAL ;
    ANTENNAGATEAREA 0.159000 ;
    PORT
      LAYER met2 ;
        RECT 858.910 0.000 859.190 0.280 ;
    END
  END FrameStrobe[96]
  PIN FrameStrobe[97]
    DIRECTION INPUT ;
    USE SIGNAL ;
    ANTENNAGATEAREA 0.159000 ;
    PORT
      LAYER met2 ;
        RECT 869.030 0.000 869.310 0.280 ;
    END
  END FrameStrobe[97]
  PIN FrameStrobe[98]
    DIRECTION INPUT ;
    USE SIGNAL ;
    ANTENNAGATEAREA 0.159000 ;
    PORT
      LAYER met2 ;
        RECT 879.150 0.000 879.430 0.280 ;
    END
  END FrameStrobe[98]
  PIN FrameStrobe[99]
    DIRECTION INPUT ;
    USE SIGNAL ;
    ANTENNAGATEAREA 0.159000 ;
    PORT
      LAYER met2 ;
        RECT 889.270 0.000 889.550 0.280 ;
    END
  END FrameStrobe[99]
  PIN FrameStrobe[9]
    DIRECTION INPUT ;
    USE SIGNAL ;
    ANTENNAGATEAREA 0.159000 ;
    PORT
      LAYER met2 ;
        RECT 27.690 0.000 27.970 0.280 ;
    END
  END FrameStrobe[9]
  PIN Tile_X0Y1_A_EN_top
    DIRECTION OUTPUT ;
    USE SIGNAL ;
    ANTENNADIFFAREA 0.702900 ;
    PORT
      LAYER met3 ;
        RECT 0.000 1192.760 0.600 1193.360 ;
    END
  END Tile_X0Y1_A_EN_top
  PIN Tile_X0Y1_A_IN_top
    DIRECTION OUTPUT ;
    USE SIGNAL ;
    ANTENNADIFFAREA 0.702900 ;
    PORT
      LAYER met3 ;
        RECT 0.000 1187.320 0.600 1187.920 ;
    END
  END Tile_X0Y1_A_IN_top
  PIN Tile_X0Y1_A_OUT_top
    DIRECTION INPUT ;
    USE SIGNAL ;
    ANTENNAGATEAREA 0.252000 ;
    PORT
      LAYER met3 ;
        RECT 0.000 1181.880 0.600 1182.480 ;
    END
  END Tile_X0Y1_A_OUT_top
  PIN Tile_X0Y1_B_EN_top
    DIRECTION OUTPUT ;
    USE SIGNAL ;
    ANTENNADIFFAREA 0.702900 ;
    PORT
      LAYER met3 ;
        RECT 0.000 1209.080 0.600 1209.680 ;
    END
  END Tile_X0Y1_B_EN_top
  PIN Tile_X0Y1_B_IN_top
    DIRECTION OUTPUT ;
    USE SIGNAL ;
    ANTENNADIFFAREA 0.702900 ;
    PORT
      LAYER met3 ;
        RECT 0.000 1203.640 0.600 1204.240 ;
    END
  END Tile_X0Y1_B_IN_top
  PIN Tile_X0Y1_B_OUT_top
    DIRECTION INPUT ;
    USE SIGNAL ;
    ANTENNAGATEAREA 0.252000 ;
    PORT
      LAYER met3 ;
        RECT 0.000 1198.200 0.600 1198.800 ;
    END
  END Tile_X0Y1_B_OUT_top
  PIN Tile_X0Y2_A_EN_top
    DIRECTION OUTPUT ;
    USE SIGNAL ;
    ANTENNADIFFAREA 0.702900 ;
    PORT
      LAYER met3 ;
        RECT 0.000 969.720 0.600 970.320 ;
    END
  END Tile_X0Y2_A_EN_top
  PIN Tile_X0Y2_A_IN_top
    DIRECTION OUTPUT ;
    USE SIGNAL ;
    ANTENNADIFFAREA 0.702900 ;
    PORT
      LAYER met3 ;
        RECT 0.000 964.280 0.600 964.880 ;
    END
  END Tile_X0Y2_A_IN_top
  PIN Tile_X0Y2_A_OUT_top
    DIRECTION INPUT ;
    USE SIGNAL ;
    ANTENNAGATEAREA 0.252000 ;
    PORT
      LAYER met3 ;
        RECT 0.000 958.840 0.600 959.440 ;
    END
  END Tile_X0Y2_A_OUT_top
  PIN Tile_X0Y2_B_EN_top
    DIRECTION OUTPUT ;
    USE SIGNAL ;
    ANTENNADIFFAREA 0.702900 ;
    PORT
      LAYER met3 ;
        RECT 0.000 986.040 0.600 986.640 ;
    END
  END Tile_X0Y2_B_EN_top
  PIN Tile_X0Y2_B_IN_top
    DIRECTION OUTPUT ;
    USE SIGNAL ;
    ANTENNADIFFAREA 0.702900 ;
    PORT
      LAYER met3 ;
        RECT 0.000 980.600 0.600 981.200 ;
    END
  END Tile_X0Y2_B_IN_top
  PIN Tile_X0Y2_B_OUT_top
    DIRECTION INPUT ;
    USE SIGNAL ;
    ANTENNAGATEAREA 0.252000 ;
    PORT
      LAYER met3 ;
        RECT 0.000 975.160 0.600 975.760 ;
    END
  END Tile_X0Y2_B_OUT_top
  PIN Tile_X0Y3_A_EN_top
    DIRECTION OUTPUT ;
    USE SIGNAL ;
    ANTENNADIFFAREA 0.702900 ;
    PORT
      LAYER met3 ;
        RECT 0.000 746.680 0.600 747.280 ;
    END
  END Tile_X0Y3_A_EN_top
  PIN Tile_X0Y3_A_IN_top
    DIRECTION OUTPUT ;
    USE SIGNAL ;
    ANTENNADIFFAREA 0.702900 ;
    PORT
      LAYER met3 ;
        RECT 0.000 741.240 0.600 741.840 ;
    END
  END Tile_X0Y3_A_IN_top
  PIN Tile_X0Y3_A_OUT_top
    DIRECTION INPUT ;
    USE SIGNAL ;
    ANTENNAGATEAREA 0.252000 ;
    PORT
      LAYER met3 ;
        RECT 0.000 735.800 0.600 736.400 ;
    END
  END Tile_X0Y3_A_OUT_top
  PIN Tile_X0Y3_B_EN_top
    DIRECTION OUTPUT ;
    USE SIGNAL ;
    ANTENNADIFFAREA 0.702900 ;
    PORT
      LAYER met3 ;
        RECT 0.000 763.000 0.600 763.600 ;
    END
  END Tile_X0Y3_B_EN_top
  PIN Tile_X0Y3_B_IN_top
    DIRECTION OUTPUT ;
    USE SIGNAL ;
    ANTENNADIFFAREA 0.702900 ;
    PORT
      LAYER met3 ;
        RECT 0.000 757.560 0.600 758.160 ;
    END
  END Tile_X0Y3_B_IN_top
  PIN Tile_X0Y3_B_OUT_top
    DIRECTION INPUT ;
    USE SIGNAL ;
    ANTENNAGATEAREA 0.252000 ;
    PORT
      LAYER met3 ;
        RECT 0.000 752.120 0.600 752.720 ;
    END
  END Tile_X0Y3_B_OUT_top
  PIN Tile_X0Y4_A_EN_top
    DIRECTION OUTPUT ;
    USE SIGNAL ;
    ANTENNADIFFAREA 0.702900 ;
    PORT
      LAYER met3 ;
        RECT 0.000 523.640 0.600 524.240 ;
    END
  END Tile_X0Y4_A_EN_top
  PIN Tile_X0Y4_A_IN_top
    DIRECTION OUTPUT ;
    USE SIGNAL ;
    ANTENNADIFFAREA 0.702900 ;
    PORT
      LAYER met3 ;
        RECT 0.000 518.200 0.600 518.800 ;
    END
  END Tile_X0Y4_A_IN_top
  PIN Tile_X0Y4_A_OUT_top
    DIRECTION INPUT ;
    USE SIGNAL ;
    ANTENNAGATEAREA 0.252000 ;
    PORT
      LAYER met3 ;
        RECT 0.000 512.760 0.600 513.360 ;
    END
  END Tile_X0Y4_A_OUT_top
  PIN Tile_X0Y4_B_EN_top
    DIRECTION OUTPUT ;
    USE SIGNAL ;
    ANTENNADIFFAREA 0.702900 ;
    PORT
      LAYER met3 ;
        RECT 0.000 539.960 0.600 540.560 ;
    END
  END Tile_X0Y4_B_EN_top
  PIN Tile_X0Y4_B_IN_top
    DIRECTION OUTPUT ;
    USE SIGNAL ;
    ANTENNADIFFAREA 0.702900 ;
    PORT
      LAYER met3 ;
        RECT 0.000 534.520 0.600 535.120 ;
    END
  END Tile_X0Y4_B_IN_top
  PIN Tile_X0Y4_B_OUT_top
    DIRECTION INPUT ;
    USE SIGNAL ;
    ANTENNAGATEAREA 0.252000 ;
    PORT
      LAYER met3 ;
        RECT 0.000 529.080 0.600 529.680 ;
    END
  END Tile_X0Y4_B_OUT_top
  PIN Tile_X0Y5_A_EN_top
    DIRECTION OUTPUT ;
    USE SIGNAL ;
    ANTENNADIFFAREA 0.702900 ;
    PORT
      LAYER met3 ;
        RECT 0.000 300.600 0.600 301.200 ;
    END
  END Tile_X0Y5_A_EN_top
  PIN Tile_X0Y5_A_IN_top
    DIRECTION OUTPUT ;
    USE SIGNAL ;
    ANTENNADIFFAREA 0.702900 ;
    PORT
      LAYER met3 ;
        RECT 0.000 295.160 0.600 295.760 ;
    END
  END Tile_X0Y5_A_IN_top
  PIN Tile_X0Y5_A_OUT_top
    DIRECTION INPUT ;
    USE SIGNAL ;
    ANTENNAGATEAREA 0.252000 ;
    PORT
      LAYER met3 ;
        RECT 0.000 289.720 0.600 290.320 ;
    END
  END Tile_X0Y5_A_OUT_top
  PIN Tile_X0Y5_B_EN_top
    DIRECTION OUTPUT ;
    USE SIGNAL ;
    ANTENNADIFFAREA 0.702900 ;
    PORT
      LAYER met3 ;
        RECT 0.000 316.920 0.600 317.520 ;
    END
  END Tile_X0Y5_B_EN_top
  PIN Tile_X0Y5_B_IN_top
    DIRECTION OUTPUT ;
    USE SIGNAL ;
    ANTENNADIFFAREA 0.702900 ;
    PORT
      LAYER met3 ;
        RECT 0.000 311.480 0.600 312.080 ;
    END
  END Tile_X0Y5_B_IN_top
  PIN Tile_X0Y5_B_OUT_top
    DIRECTION INPUT ;
    USE SIGNAL ;
    ANTENNAGATEAREA 0.252000 ;
    PORT
      LAYER met3 ;
        RECT 0.000 306.040 0.600 306.640 ;
    END
  END Tile_X0Y5_B_OUT_top
  PIN Tile_X0Y6_A_EN_top
    DIRECTION OUTPUT ;
    USE SIGNAL ;
    ANTENNADIFFAREA 0.702900 ;
    PORT
      LAYER met3 ;
        RECT 0.000 77.560 0.600 78.160 ;
    END
  END Tile_X0Y6_A_EN_top
  PIN Tile_X0Y6_A_IN_top
    DIRECTION OUTPUT ;
    USE SIGNAL ;
    ANTENNADIFFAREA 0.702900 ;
    PORT
      LAYER met3 ;
        RECT 0.000 72.120 0.600 72.720 ;
    END
  END Tile_X0Y6_A_IN_top
  PIN Tile_X0Y6_A_OUT_top
    DIRECTION INPUT ;
    USE SIGNAL ;
    ANTENNAGATEAREA 0.252000 ;
    PORT
      LAYER met3 ;
        RECT 0.000 66.680 0.600 67.280 ;
    END
  END Tile_X0Y6_A_OUT_top
  PIN Tile_X0Y6_B_EN_top
    DIRECTION OUTPUT ;
    USE SIGNAL ;
    ANTENNADIFFAREA 0.702900 ;
    PORT
      LAYER met3 ;
        RECT 0.000 93.880 0.600 94.480 ;
    END
  END Tile_X0Y6_B_EN_top
  PIN Tile_X0Y6_B_IN_top
    DIRECTION OUTPUT ;
    USE SIGNAL ;
    ANTENNADIFFAREA 0.702900 ;
    PORT
      LAYER met3 ;
        RECT 0.000 88.440 0.600 89.040 ;
    END
  END Tile_X0Y6_B_IN_top
  PIN Tile_X0Y6_B_OUT_top
    DIRECTION INPUT ;
    USE SIGNAL ;
    ANTENNAGATEAREA 0.252000 ;
    PORT
      LAYER met3 ;
        RECT 0.000 83.000 0.600 83.600 ;
    END
  END Tile_X0Y6_B_OUT_top
  PIN Tile_X0Y7_SYS_RESET_RESET_top
    DIRECTION INPUT ;
    USE SIGNAL ;
    ANTENNAGATEAREA 0.621000 ;
    PORT
      LAYER met2 ;
        RECT 4.690 0.000 4.970 0.280 ;
    END
  END Tile_X0Y7_SYS_RESET_RESET_top
  PIN Tile_X5Y1_A_EN_top
    DIRECTION OUTPUT ;
    USE SIGNAL ;
    ANTENNADIFFAREA 0.702900 ;
    PORT
      LAYER met3 ;
        RECT 954.360 1192.760 954.960 1193.360 ;
    END
  END Tile_X5Y1_A_EN_top
  PIN Tile_X5Y1_A_IN_top
    DIRECTION OUTPUT ;
    USE SIGNAL ;
    ANTENNADIFFAREA 0.702900 ;
    PORT
      LAYER met3 ;
        RECT 954.360 1187.320 954.960 1187.920 ;
    END
  END Tile_X5Y1_A_IN_top
  PIN Tile_X5Y1_A_OUT_top
    DIRECTION INPUT ;
    USE SIGNAL ;
    ANTENNAGATEAREA 0.252000 ;
    PORT
      LAYER met3 ;
        RECT 954.360 1181.880 954.960 1182.480 ;
    END
  END Tile_X5Y1_A_OUT_top
  PIN Tile_X5Y1_B_EN_top
    DIRECTION OUTPUT ;
    USE SIGNAL ;
    ANTENNADIFFAREA 0.702900 ;
    PORT
      LAYER met3 ;
        RECT 954.360 1209.080 954.960 1209.680 ;
    END
  END Tile_X5Y1_B_EN_top
  PIN Tile_X5Y1_B_IN_top
    DIRECTION OUTPUT ;
    USE SIGNAL ;
    ANTENNADIFFAREA 0.702900 ;
    PORT
      LAYER met3 ;
        RECT 954.360 1203.640 954.960 1204.240 ;
    END
  END Tile_X5Y1_B_IN_top
  PIN Tile_X5Y1_B_OUT_top
    DIRECTION INPUT ;
    USE SIGNAL ;
    ANTENNAGATEAREA 0.252000 ;
    PORT
      LAYER met3 ;
        RECT 954.360 1198.200 954.960 1198.800 ;
    END
  END Tile_X5Y1_B_OUT_top
  PIN Tile_X5Y2_A_EN_top
    DIRECTION OUTPUT ;
    USE SIGNAL ;
    ANTENNADIFFAREA 0.702900 ;
    PORT
      LAYER met3 ;
        RECT 954.360 969.720 954.960 970.320 ;
    END
  END Tile_X5Y2_A_EN_top
  PIN Tile_X5Y2_A_IN_top
    DIRECTION OUTPUT ;
    USE SIGNAL ;
    ANTENNADIFFAREA 0.702900 ;
    PORT
      LAYER met3 ;
        RECT 954.360 964.280 954.960 964.880 ;
    END
  END Tile_X5Y2_A_IN_top
  PIN Tile_X5Y2_A_OUT_top
    DIRECTION INPUT ;
    USE SIGNAL ;
    ANTENNAGATEAREA 0.252000 ;
    PORT
      LAYER met3 ;
        RECT 954.360 958.840 954.960 959.440 ;
    END
  END Tile_X5Y2_A_OUT_top
  PIN Tile_X5Y2_B_EN_top
    DIRECTION OUTPUT ;
    USE SIGNAL ;
    ANTENNADIFFAREA 0.702900 ;
    PORT
      LAYER met3 ;
        RECT 954.360 986.040 954.960 986.640 ;
    END
  END Tile_X5Y2_B_EN_top
  PIN Tile_X5Y2_B_IN_top
    DIRECTION OUTPUT ;
    USE SIGNAL ;
    ANTENNADIFFAREA 0.702900 ;
    PORT
      LAYER met3 ;
        RECT 954.360 980.600 954.960 981.200 ;
    END
  END Tile_X5Y2_B_IN_top
  PIN Tile_X5Y2_B_OUT_top
    DIRECTION INPUT ;
    USE SIGNAL ;
    ANTENNAGATEAREA 0.252000 ;
    PORT
      LAYER met3 ;
        RECT 954.360 975.160 954.960 975.760 ;
    END
  END Tile_X5Y2_B_OUT_top
  PIN Tile_X5Y3_A_EN_top
    DIRECTION OUTPUT ;
    USE SIGNAL ;
    ANTENNADIFFAREA 0.702900 ;
    PORT
      LAYER met3 ;
        RECT 954.360 746.680 954.960 747.280 ;
    END
  END Tile_X5Y3_A_EN_top
  PIN Tile_X5Y3_A_IN_top
    DIRECTION OUTPUT ;
    USE SIGNAL ;
    ANTENNADIFFAREA 0.702900 ;
    PORT
      LAYER met3 ;
        RECT 954.360 741.240 954.960 741.840 ;
    END
  END Tile_X5Y3_A_IN_top
  PIN Tile_X5Y3_A_OUT_top
    DIRECTION INPUT ;
    USE SIGNAL ;
    ANTENNAGATEAREA 0.252000 ;
    PORT
      LAYER met3 ;
        RECT 954.360 735.800 954.960 736.400 ;
    END
  END Tile_X5Y3_A_OUT_top
  PIN Tile_X5Y3_B_EN_top
    DIRECTION OUTPUT ;
    USE SIGNAL ;
    ANTENNADIFFAREA 0.702900 ;
    PORT
      LAYER met3 ;
        RECT 954.360 763.000 954.960 763.600 ;
    END
  END Tile_X5Y3_B_EN_top
  PIN Tile_X5Y3_B_IN_top
    DIRECTION OUTPUT ;
    USE SIGNAL ;
    ANTENNADIFFAREA 0.702900 ;
    PORT
      LAYER met3 ;
        RECT 954.360 757.560 954.960 758.160 ;
    END
  END Tile_X5Y3_B_IN_top
  PIN Tile_X5Y3_B_OUT_top
    DIRECTION INPUT ;
    USE SIGNAL ;
    ANTENNAGATEAREA 0.252000 ;
    PORT
      LAYER met3 ;
        RECT 954.360 752.120 954.960 752.720 ;
    END
  END Tile_X5Y3_B_OUT_top
  PIN Tile_X5Y4_A_EN_top
    DIRECTION OUTPUT ;
    USE SIGNAL ;
    ANTENNADIFFAREA 0.702900 ;
    PORT
      LAYER met3 ;
        RECT 954.360 523.640 954.960 524.240 ;
    END
  END Tile_X5Y4_A_EN_top
  PIN Tile_X5Y4_A_IN_top
    DIRECTION OUTPUT ;
    USE SIGNAL ;
    ANTENNADIFFAREA 0.702900 ;
    PORT
      LAYER met3 ;
        RECT 954.360 518.200 954.960 518.800 ;
    END
  END Tile_X5Y4_A_IN_top
  PIN Tile_X5Y4_A_OUT_top
    DIRECTION INPUT ;
    USE SIGNAL ;
    ANTENNAGATEAREA 0.252000 ;
    PORT
      LAYER met3 ;
        RECT 954.360 512.760 954.960 513.360 ;
    END
  END Tile_X5Y4_A_OUT_top
  PIN Tile_X5Y4_B_EN_top
    DIRECTION OUTPUT ;
    USE SIGNAL ;
    ANTENNADIFFAREA 0.702900 ;
    PORT
      LAYER met3 ;
        RECT 954.360 539.960 954.960 540.560 ;
    END
  END Tile_X5Y4_B_EN_top
  PIN Tile_X5Y4_B_IN_top
    DIRECTION OUTPUT ;
    USE SIGNAL ;
    ANTENNADIFFAREA 0.702900 ;
    PORT
      LAYER met3 ;
        RECT 954.360 534.520 954.960 535.120 ;
    END
  END Tile_X5Y4_B_IN_top
  PIN Tile_X5Y4_B_OUT_top
    DIRECTION INPUT ;
    USE SIGNAL ;
    ANTENNAGATEAREA 0.252000 ;
    PORT
      LAYER met3 ;
        RECT 954.360 529.080 954.960 529.680 ;
    END
  END Tile_X5Y4_B_OUT_top
  PIN Tile_X5Y5_A_EN_top
    DIRECTION OUTPUT ;
    USE SIGNAL ;
    ANTENNADIFFAREA 0.702900 ;
    PORT
      LAYER met3 ;
        RECT 954.360 300.600 954.960 301.200 ;
    END
  END Tile_X5Y5_A_EN_top
  PIN Tile_X5Y5_A_IN_top
    DIRECTION OUTPUT ;
    USE SIGNAL ;
    ANTENNADIFFAREA 0.702900 ;
    PORT
      LAYER met3 ;
        RECT 954.360 295.160 954.960 295.760 ;
    END
  END Tile_X5Y5_A_IN_top
  PIN Tile_X5Y5_A_OUT_top
    DIRECTION INPUT ;
    USE SIGNAL ;
    ANTENNAGATEAREA 0.252000 ;
    PORT
      LAYER met3 ;
        RECT 954.360 289.720 954.960 290.320 ;
    END
  END Tile_X5Y5_A_OUT_top
  PIN Tile_X5Y5_B_EN_top
    DIRECTION OUTPUT ;
    USE SIGNAL ;
    ANTENNADIFFAREA 0.702900 ;
    PORT
      LAYER met3 ;
        RECT 954.360 316.920 954.960 317.520 ;
    END
  END Tile_X5Y5_B_EN_top
  PIN Tile_X5Y5_B_IN_top
    DIRECTION OUTPUT ;
    USE SIGNAL ;
    ANTENNADIFFAREA 0.702900 ;
    PORT
      LAYER met3 ;
        RECT 954.360 311.480 954.960 312.080 ;
    END
  END Tile_X5Y5_B_IN_top
  PIN Tile_X5Y5_B_OUT_top
    DIRECTION INPUT ;
    USE SIGNAL ;
    ANTENNAGATEAREA 0.252000 ;
    PORT
      LAYER met3 ;
        RECT 954.360 306.040 954.960 306.640 ;
    END
  END Tile_X5Y5_B_OUT_top
  PIN Tile_X5Y6_A_EN_top
    DIRECTION OUTPUT ;
    USE SIGNAL ;
    ANTENNADIFFAREA 0.702900 ;
    PORT
      LAYER met3 ;
        RECT 954.360 77.560 954.960 78.160 ;
    END
  END Tile_X5Y6_A_EN_top
  PIN Tile_X5Y6_A_IN_top
    DIRECTION OUTPUT ;
    USE SIGNAL ;
    ANTENNADIFFAREA 0.702900 ;
    PORT
      LAYER met3 ;
        RECT 954.360 72.120 954.960 72.720 ;
    END
  END Tile_X5Y6_A_IN_top
  PIN Tile_X5Y6_A_OUT_top
    DIRECTION INPUT ;
    USE SIGNAL ;
    ANTENNAGATEAREA 0.252000 ;
    PORT
      LAYER met3 ;
        RECT 954.360 66.680 954.960 67.280 ;
    END
  END Tile_X5Y6_A_OUT_top
  PIN Tile_X5Y6_B_EN_top
    DIRECTION OUTPUT ;
    USE SIGNAL ;
    ANTENNADIFFAREA 0.702900 ;
    PORT
      LAYER met3 ;
        RECT 954.360 93.880 954.960 94.480 ;
    END
  END Tile_X5Y6_B_EN_top
  PIN Tile_X5Y6_B_IN_top
    DIRECTION OUTPUT ;
    USE SIGNAL ;
    ANTENNADIFFAREA 0.702900 ;
    PORT
      LAYER met3 ;
        RECT 954.360 88.440 954.960 89.040 ;
    END
  END Tile_X5Y6_B_IN_top
  PIN Tile_X5Y6_B_OUT_top
    DIRECTION INPUT ;
    USE SIGNAL ;
    ANTENNAGATEAREA 0.252000 ;
    PORT
      LAYER met3 ;
        RECT 954.360 83.000 954.960 83.600 ;
    END
  END Tile_X5Y6_B_OUT_top
  PIN VGND
    DIRECTION INOUT ;
    USE GROUND ;
    PORT
      LAYER met4 ;
        RECT 12.260 1395.360 13.860 1452.480 ;
    END
    PORT
      LAYER met4 ;
        RECT 42.260 1395.360 43.860 1452.480 ;
    END
    PORT
      LAYER met4 ;
        RECT 12.260 1172.320 13.860 1395.360 ;
    END
    PORT
      LAYER met4 ;
        RECT 42.260 1172.320 43.860 1395.360 ;
    END
    PORT
      LAYER met4 ;
        RECT 12.260 949.280 13.860 1172.320 ;
    END
    PORT
      LAYER met4 ;
        RECT 42.260 949.280 43.860 1172.320 ;
    END
    PORT
      LAYER met4 ;
        RECT 12.260 726.240 13.860 949.280 ;
    END
    PORT
      LAYER met4 ;
        RECT 42.260 726.240 43.860 949.280 ;
    END
    PORT
      LAYER met4 ;
        RECT 12.260 503.200 13.860 726.240 ;
    END
    PORT
      LAYER met4 ;
        RECT 42.260 503.200 43.860 726.240 ;
    END
    PORT
      LAYER met4 ;
        RECT 12.260 280.160 13.860 503.200 ;
    END
    PORT
      LAYER met4 ;
        RECT 42.260 280.160 43.860 503.200 ;
    END
    PORT
      LAYER met4 ;
        RECT 12.260 57.120 13.860 280.160 ;
    END
    PORT
      LAYER met4 ;
        RECT 42.260 57.120 43.860 280.160 ;
    END
    PORT
      LAYER met4 ;
        RECT 12.260 0.000 13.860 57.120 ;
    END
    PORT
      LAYER met4 ;
        RECT 42.260 0.000 43.860 57.120 ;
    END
    PORT
      LAYER met4 ;
        RECT 68.380 1395.360 69.980 1452.480 ;
    END
    PORT
      LAYER met4 ;
        RECT 98.380 1395.360 99.980 1452.480 ;
    END
    PORT
      LAYER met4 ;
        RECT 128.380 1395.360 129.980 1452.480 ;
    END
    PORT
      LAYER met4 ;
        RECT 158.380 1395.360 159.980 1452.480 ;
    END
    PORT
      LAYER met4 ;
        RECT 188.380 1395.360 189.980 1452.480 ;
    END
    PORT
      LAYER met4 ;
        RECT 218.380 1395.360 219.980 1452.480 ;
    END
    PORT
      LAYER met4 ;
        RECT 248.380 1395.360 249.980 1452.480 ;
    END
    PORT
      LAYER met4 ;
        RECT 68.380 1172.320 69.980 1395.360 ;
    END
    PORT
      LAYER met4 ;
        RECT 98.380 1172.320 99.980 1395.360 ;
    END
    PORT
      LAYER met4 ;
        RECT 128.380 1172.320 129.980 1395.360 ;
    END
    PORT
      LAYER met4 ;
        RECT 158.380 1172.320 159.980 1395.360 ;
    END
    PORT
      LAYER met4 ;
        RECT 188.380 1172.320 189.980 1395.360 ;
    END
    PORT
      LAYER met4 ;
        RECT 218.380 1172.320 219.980 1395.360 ;
    END
    PORT
      LAYER met4 ;
        RECT 248.380 1172.320 249.980 1395.360 ;
    END
    PORT
      LAYER met4 ;
        RECT 68.380 949.280 69.980 1172.320 ;
    END
    PORT
      LAYER met4 ;
        RECT 98.380 949.280 99.980 1172.320 ;
    END
    PORT
      LAYER met4 ;
        RECT 128.380 949.280 129.980 1172.320 ;
    END
    PORT
      LAYER met4 ;
        RECT 158.380 949.280 159.980 1172.320 ;
    END
    PORT
      LAYER met4 ;
        RECT 188.380 949.280 189.980 1172.320 ;
    END
    PORT
      LAYER met4 ;
        RECT 218.380 949.280 219.980 1172.320 ;
    END
    PORT
      LAYER met4 ;
        RECT 248.380 949.280 249.980 1172.320 ;
    END
    PORT
      LAYER met4 ;
        RECT 68.380 726.240 69.980 949.280 ;
    END
    PORT
      LAYER met4 ;
        RECT 98.380 726.240 99.980 949.280 ;
    END
    PORT
      LAYER met4 ;
        RECT 128.380 726.240 129.980 949.280 ;
    END
    PORT
      LAYER met4 ;
        RECT 158.380 726.240 159.980 949.280 ;
    END
    PORT
      LAYER met4 ;
        RECT 188.380 726.240 189.980 949.280 ;
    END
    PORT
      LAYER met4 ;
        RECT 218.380 726.240 219.980 949.280 ;
    END
    PORT
      LAYER met4 ;
        RECT 248.380 726.240 249.980 949.280 ;
    END
    PORT
      LAYER met4 ;
        RECT 68.380 503.200 69.980 726.240 ;
    END
    PORT
      LAYER met4 ;
        RECT 98.380 503.200 99.980 726.240 ;
    END
    PORT
      LAYER met4 ;
        RECT 128.380 503.200 129.980 726.240 ;
    END
    PORT
      LAYER met4 ;
        RECT 158.380 503.200 159.980 726.240 ;
    END
    PORT
      LAYER met4 ;
        RECT 188.380 503.200 189.980 726.240 ;
    END
    PORT
      LAYER met4 ;
        RECT 218.380 503.200 219.980 726.240 ;
    END
    PORT
      LAYER met4 ;
        RECT 248.380 503.200 249.980 726.240 ;
    END
    PORT
      LAYER met4 ;
        RECT 68.380 280.160 69.980 503.200 ;
    END
    PORT
      LAYER met4 ;
        RECT 98.380 280.160 99.980 503.200 ;
    END
    PORT
      LAYER met4 ;
        RECT 128.380 280.160 129.980 503.200 ;
    END
    PORT
      LAYER met4 ;
        RECT 158.380 280.160 159.980 503.200 ;
    END
    PORT
      LAYER met4 ;
        RECT 188.380 280.160 189.980 503.200 ;
    END
    PORT
      LAYER met4 ;
        RECT 218.380 280.160 219.980 503.200 ;
    END
    PORT
      LAYER met4 ;
        RECT 248.380 280.160 249.980 503.200 ;
    END
    PORT
      LAYER met4 ;
        RECT 68.380 57.120 69.980 280.160 ;
    END
    PORT
      LAYER met4 ;
        RECT 98.380 57.120 99.980 280.160 ;
    END
    PORT
      LAYER met4 ;
        RECT 128.380 57.120 129.980 280.160 ;
    END
    PORT
      LAYER met4 ;
        RECT 158.380 57.120 159.980 280.160 ;
    END
    PORT
      LAYER met4 ;
        RECT 188.380 57.120 189.980 280.160 ;
    END
    PORT
      LAYER met4 ;
        RECT 218.380 57.120 219.980 280.160 ;
    END
    PORT
      LAYER met4 ;
        RECT 248.380 57.120 249.980 280.160 ;
    END
    PORT
      LAYER met4 ;
        RECT 68.380 0.000 69.980 57.120 ;
    END
    PORT
      LAYER met4 ;
        RECT 98.380 0.000 99.980 57.120 ;
    END
    PORT
      LAYER met4 ;
        RECT 128.380 0.000 129.980 57.120 ;
    END
    PORT
      LAYER met4 ;
        RECT 158.380 0.000 159.980 57.120 ;
    END
    PORT
      LAYER met4 ;
        RECT 188.380 0.000 189.980 57.120 ;
    END
    PORT
      LAYER met4 ;
        RECT 218.380 0.000 219.980 57.120 ;
    END
    PORT
      LAYER met4 ;
        RECT 248.380 0.000 249.980 57.120 ;
    END
    PORT
      LAYER met4 ;
        RECT 279.060 1395.360 280.660 1452.480 ;
    END
    PORT
      LAYER met4 ;
        RECT 309.060 1395.360 310.660 1452.480 ;
    END
    PORT
      LAYER met4 ;
        RECT 339.060 1395.360 340.660 1452.480 ;
    END
    PORT
      LAYER met4 ;
        RECT 369.060 1395.360 370.660 1452.480 ;
    END
    PORT
      LAYER met4 ;
        RECT 399.060 1395.360 400.660 1452.480 ;
    END
    PORT
      LAYER met4 ;
        RECT 429.060 1395.360 430.660 1452.480 ;
    END
    PORT
      LAYER met4 ;
        RECT 459.060 1395.360 460.660 1452.480 ;
    END
    PORT
      LAYER met4 ;
        RECT 279.060 1172.320 280.660 1395.360 ;
    END
    PORT
      LAYER met4 ;
        RECT 309.060 1172.320 310.660 1395.360 ;
    END
    PORT
      LAYER met4 ;
        RECT 339.060 1172.320 340.660 1395.360 ;
    END
    PORT
      LAYER met4 ;
        RECT 369.060 1172.320 370.660 1395.360 ;
    END
    PORT
      LAYER met4 ;
        RECT 399.060 1172.320 400.660 1395.360 ;
    END
    PORT
      LAYER met4 ;
        RECT 429.060 1172.320 430.660 1395.360 ;
    END
    PORT
      LAYER met4 ;
        RECT 459.060 1172.320 460.660 1395.360 ;
    END
    PORT
      LAYER met4 ;
        RECT 279.060 949.280 280.660 1172.320 ;
    END
    PORT
      LAYER met4 ;
        RECT 309.060 949.280 310.660 1172.320 ;
    END
    PORT
      LAYER met4 ;
        RECT 339.060 949.280 340.660 1172.320 ;
    END
    PORT
      LAYER met4 ;
        RECT 369.060 949.280 370.660 1172.320 ;
    END
    PORT
      LAYER met4 ;
        RECT 399.060 949.280 400.660 1172.320 ;
    END
    PORT
      LAYER met4 ;
        RECT 429.060 949.280 430.660 1172.320 ;
    END
    PORT
      LAYER met4 ;
        RECT 459.060 949.280 460.660 1172.320 ;
    END
    PORT
      LAYER met4 ;
        RECT 279.060 726.240 280.660 949.280 ;
    END
    PORT
      LAYER met4 ;
        RECT 309.060 726.240 310.660 949.280 ;
    END
    PORT
      LAYER met4 ;
        RECT 339.060 726.240 340.660 949.280 ;
    END
    PORT
      LAYER met4 ;
        RECT 369.060 726.240 370.660 949.280 ;
    END
    PORT
      LAYER met4 ;
        RECT 399.060 726.240 400.660 949.280 ;
    END
    PORT
      LAYER met4 ;
        RECT 429.060 726.240 430.660 949.280 ;
    END
    PORT
      LAYER met4 ;
        RECT 459.060 726.240 460.660 949.280 ;
    END
    PORT
      LAYER met4 ;
        RECT 279.060 503.200 280.660 726.240 ;
    END
    PORT
      LAYER met4 ;
        RECT 309.060 503.200 310.660 726.240 ;
    END
    PORT
      LAYER met4 ;
        RECT 339.060 503.200 340.660 726.240 ;
    END
    PORT
      LAYER met4 ;
        RECT 369.060 503.200 370.660 726.240 ;
    END
    PORT
      LAYER met4 ;
        RECT 399.060 503.200 400.660 726.240 ;
    END
    PORT
      LAYER met4 ;
        RECT 429.060 503.200 430.660 726.240 ;
    END
    PORT
      LAYER met4 ;
        RECT 459.060 503.200 460.660 726.240 ;
    END
    PORT
      LAYER met4 ;
        RECT 279.060 280.160 280.660 503.200 ;
    END
    PORT
      LAYER met4 ;
        RECT 309.060 280.160 310.660 503.200 ;
    END
    PORT
      LAYER met4 ;
        RECT 339.060 280.160 340.660 503.200 ;
    END
    PORT
      LAYER met4 ;
        RECT 369.060 280.160 370.660 503.200 ;
    END
    PORT
      LAYER met4 ;
        RECT 399.060 280.160 400.660 503.200 ;
    END
    PORT
      LAYER met4 ;
        RECT 429.060 280.160 430.660 503.200 ;
    END
    PORT
      LAYER met4 ;
        RECT 459.060 280.160 460.660 503.200 ;
    END
    PORT
      LAYER met4 ;
        RECT 279.060 57.120 280.660 280.160 ;
    END
    PORT
      LAYER met4 ;
        RECT 309.060 57.120 310.660 280.160 ;
    END
    PORT
      LAYER met4 ;
        RECT 339.060 57.120 340.660 280.160 ;
    END
    PORT
      LAYER met4 ;
        RECT 369.060 57.120 370.660 280.160 ;
    END
    PORT
      LAYER met4 ;
        RECT 399.060 57.120 400.660 280.160 ;
    END
    PORT
      LAYER met4 ;
        RECT 429.060 57.120 430.660 280.160 ;
    END
    PORT
      LAYER met4 ;
        RECT 459.060 57.120 460.660 280.160 ;
    END
    PORT
      LAYER met4 ;
        RECT 279.060 0.000 280.660 57.120 ;
    END
    PORT
      LAYER met4 ;
        RECT 309.060 0.000 310.660 57.120 ;
    END
    PORT
      LAYER met4 ;
        RECT 339.060 0.000 340.660 57.120 ;
    END
    PORT
      LAYER met4 ;
        RECT 369.060 0.000 370.660 57.120 ;
    END
    PORT
      LAYER met4 ;
        RECT 399.060 0.000 400.660 57.120 ;
    END
    PORT
      LAYER met4 ;
        RECT 429.060 0.000 430.660 57.120 ;
    END
    PORT
      LAYER met4 ;
        RECT 459.060 0.000 460.660 57.120 ;
    END
    PORT
      LAYER met4 ;
        RECT 489.740 1395.360 491.340 1452.480 ;
    END
    PORT
      LAYER met4 ;
        RECT 519.740 1395.360 521.340 1452.480 ;
    END
    PORT
      LAYER met4 ;
        RECT 549.740 1395.360 551.340 1452.480 ;
    END
    PORT
      LAYER met4 ;
        RECT 579.740 1395.360 581.340 1452.480 ;
    END
    PORT
      LAYER met4 ;
        RECT 609.740 1395.360 611.340 1452.480 ;
    END
    PORT
      LAYER met4 ;
        RECT 639.740 1395.360 641.340 1452.480 ;
    END
    PORT
      LAYER met4 ;
        RECT 669.740 1395.360 671.340 1452.480 ;
    END
    PORT
      LAYER met4 ;
        RECT 489.740 1172.320 491.340 1395.360 ;
    END
    PORT
      LAYER met4 ;
        RECT 519.740 1172.320 521.340 1395.360 ;
    END
    PORT
      LAYER met4 ;
        RECT 549.740 1172.320 551.340 1395.360 ;
    END
    PORT
      LAYER met4 ;
        RECT 579.740 1172.320 581.340 1395.360 ;
    END
    PORT
      LAYER met4 ;
        RECT 609.740 1172.320 611.340 1395.360 ;
    END
    PORT
      LAYER met4 ;
        RECT 639.740 1172.320 641.340 1395.360 ;
    END
    PORT
      LAYER met4 ;
        RECT 669.740 1172.320 671.340 1395.360 ;
    END
    PORT
      LAYER met4 ;
        RECT 489.740 949.280 491.340 1172.320 ;
    END
    PORT
      LAYER met4 ;
        RECT 519.740 949.280 521.340 1172.320 ;
    END
    PORT
      LAYER met4 ;
        RECT 549.740 949.280 551.340 1172.320 ;
    END
    PORT
      LAYER met4 ;
        RECT 579.740 949.280 581.340 1172.320 ;
    END
    PORT
      LAYER met4 ;
        RECT 609.740 949.280 611.340 1172.320 ;
    END
    PORT
      LAYER met4 ;
        RECT 639.740 949.280 641.340 1172.320 ;
    END
    PORT
      LAYER met4 ;
        RECT 669.740 949.280 671.340 1172.320 ;
    END
    PORT
      LAYER met4 ;
        RECT 489.740 726.240 491.340 949.280 ;
    END
    PORT
      LAYER met4 ;
        RECT 519.740 726.240 521.340 949.280 ;
    END
    PORT
      LAYER met4 ;
        RECT 549.740 726.240 551.340 949.280 ;
    END
    PORT
      LAYER met4 ;
        RECT 579.740 726.240 581.340 949.280 ;
    END
    PORT
      LAYER met4 ;
        RECT 609.740 726.240 611.340 949.280 ;
    END
    PORT
      LAYER met4 ;
        RECT 639.740 726.240 641.340 949.280 ;
    END
    PORT
      LAYER met4 ;
        RECT 669.740 726.240 671.340 949.280 ;
    END
    PORT
      LAYER met4 ;
        RECT 489.740 503.200 491.340 726.240 ;
    END
    PORT
      LAYER met4 ;
        RECT 519.740 503.200 521.340 726.240 ;
    END
    PORT
      LAYER met4 ;
        RECT 549.740 503.200 551.340 726.240 ;
    END
    PORT
      LAYER met4 ;
        RECT 579.740 503.200 581.340 726.240 ;
    END
    PORT
      LAYER met4 ;
        RECT 609.740 503.200 611.340 726.240 ;
    END
    PORT
      LAYER met4 ;
        RECT 639.740 503.200 641.340 726.240 ;
    END
    PORT
      LAYER met4 ;
        RECT 669.740 503.200 671.340 726.240 ;
    END
    PORT
      LAYER met4 ;
        RECT 489.740 280.160 491.340 503.200 ;
    END
    PORT
      LAYER met4 ;
        RECT 519.740 280.160 521.340 503.200 ;
    END
    PORT
      LAYER met4 ;
        RECT 549.740 280.160 551.340 503.200 ;
    END
    PORT
      LAYER met4 ;
        RECT 579.740 280.160 581.340 503.200 ;
    END
    PORT
      LAYER met4 ;
        RECT 609.740 280.160 611.340 503.200 ;
    END
    PORT
      LAYER met4 ;
        RECT 639.740 280.160 641.340 503.200 ;
    END
    PORT
      LAYER met4 ;
        RECT 669.740 280.160 671.340 503.200 ;
    END
    PORT
      LAYER met4 ;
        RECT 489.740 57.120 491.340 280.160 ;
    END
    PORT
      LAYER met4 ;
        RECT 519.740 57.120 521.340 280.160 ;
    END
    PORT
      LAYER met4 ;
        RECT 549.740 57.120 551.340 280.160 ;
    END
    PORT
      LAYER met4 ;
        RECT 579.740 57.120 581.340 280.160 ;
    END
    PORT
      LAYER met4 ;
        RECT 609.740 57.120 611.340 280.160 ;
    END
    PORT
      LAYER met4 ;
        RECT 639.740 57.120 641.340 280.160 ;
    END
    PORT
      LAYER met4 ;
        RECT 669.740 57.120 671.340 280.160 ;
    END
    PORT
      LAYER met4 ;
        RECT 489.740 0.000 491.340 57.120 ;
    END
    PORT
      LAYER met4 ;
        RECT 519.740 0.000 521.340 57.120 ;
    END
    PORT
      LAYER met4 ;
        RECT 549.740 0.000 551.340 57.120 ;
    END
    PORT
      LAYER met4 ;
        RECT 579.740 0.000 581.340 57.120 ;
    END
    PORT
      LAYER met4 ;
        RECT 609.740 0.000 611.340 57.120 ;
    END
    PORT
      LAYER met4 ;
        RECT 639.740 0.000 641.340 57.120 ;
    END
    PORT
      LAYER met4 ;
        RECT 669.740 0.000 671.340 57.120 ;
    END
    PORT
      LAYER met4 ;
        RECT 700.420 1395.360 702.020 1452.480 ;
    END
    PORT
      LAYER met4 ;
        RECT 730.420 1395.360 732.020 1452.480 ;
    END
    PORT
      LAYER met4 ;
        RECT 760.420 1395.360 762.020 1452.480 ;
    END
    PORT
      LAYER met4 ;
        RECT 790.420 1395.360 792.020 1452.480 ;
    END
    PORT
      LAYER met4 ;
        RECT 820.420 1395.360 822.020 1452.480 ;
    END
    PORT
      LAYER met4 ;
        RECT 850.420 1395.360 852.020 1452.480 ;
    END
    PORT
      LAYER met4 ;
        RECT 880.420 1395.360 882.020 1452.480 ;
    END
    PORT
      LAYER met4 ;
        RECT 700.420 1172.320 702.020 1395.360 ;
    END
    PORT
      LAYER met4 ;
        RECT 730.420 1172.320 732.020 1395.360 ;
    END
    PORT
      LAYER met4 ;
        RECT 760.420 1172.320 762.020 1395.360 ;
    END
    PORT
      LAYER met4 ;
        RECT 790.420 1172.320 792.020 1395.360 ;
    END
    PORT
      LAYER met4 ;
        RECT 820.420 1172.320 822.020 1395.360 ;
    END
    PORT
      LAYER met4 ;
        RECT 850.420 1172.320 852.020 1395.360 ;
    END
    PORT
      LAYER met4 ;
        RECT 880.420 1172.320 882.020 1395.360 ;
    END
    PORT
      LAYER met4 ;
        RECT 700.420 949.280 702.020 1172.320 ;
    END
    PORT
      LAYER met4 ;
        RECT 730.420 949.280 732.020 1172.320 ;
    END
    PORT
      LAYER met4 ;
        RECT 760.420 949.280 762.020 1172.320 ;
    END
    PORT
      LAYER met4 ;
        RECT 790.420 949.280 792.020 1172.320 ;
    END
    PORT
      LAYER met4 ;
        RECT 820.420 949.280 822.020 1172.320 ;
    END
    PORT
      LAYER met4 ;
        RECT 850.420 949.280 852.020 1172.320 ;
    END
    PORT
      LAYER met4 ;
        RECT 880.420 949.280 882.020 1172.320 ;
    END
    PORT
      LAYER met4 ;
        RECT 700.420 726.240 702.020 949.280 ;
    END
    PORT
      LAYER met4 ;
        RECT 730.420 726.240 732.020 949.280 ;
    END
    PORT
      LAYER met4 ;
        RECT 760.420 726.240 762.020 949.280 ;
    END
    PORT
      LAYER met4 ;
        RECT 790.420 726.240 792.020 949.280 ;
    END
    PORT
      LAYER met4 ;
        RECT 820.420 726.240 822.020 949.280 ;
    END
    PORT
      LAYER met4 ;
        RECT 850.420 726.240 852.020 949.280 ;
    END
    PORT
      LAYER met4 ;
        RECT 880.420 726.240 882.020 949.280 ;
    END
    PORT
      LAYER met4 ;
        RECT 700.420 503.200 702.020 726.240 ;
    END
    PORT
      LAYER met4 ;
        RECT 730.420 503.200 732.020 726.240 ;
    END
    PORT
      LAYER met4 ;
        RECT 760.420 503.200 762.020 726.240 ;
    END
    PORT
      LAYER met4 ;
        RECT 790.420 503.200 792.020 726.240 ;
    END
    PORT
      LAYER met4 ;
        RECT 820.420 503.200 822.020 726.240 ;
    END
    PORT
      LAYER met4 ;
        RECT 850.420 503.200 852.020 726.240 ;
    END
    PORT
      LAYER met4 ;
        RECT 880.420 503.200 882.020 726.240 ;
    END
    PORT
      LAYER met4 ;
        RECT 700.420 280.160 702.020 503.200 ;
    END
    PORT
      LAYER met4 ;
        RECT 730.420 280.160 732.020 503.200 ;
    END
    PORT
      LAYER met4 ;
        RECT 760.420 280.160 762.020 503.200 ;
    END
    PORT
      LAYER met4 ;
        RECT 790.420 280.160 792.020 503.200 ;
    END
    PORT
      LAYER met4 ;
        RECT 820.420 280.160 822.020 503.200 ;
    END
    PORT
      LAYER met4 ;
        RECT 850.420 280.160 852.020 503.200 ;
    END
    PORT
      LAYER met4 ;
        RECT 880.420 280.160 882.020 503.200 ;
    END
    PORT
      LAYER met4 ;
        RECT 700.420 57.120 702.020 280.160 ;
    END
    PORT
      LAYER met4 ;
        RECT 730.420 57.120 732.020 280.160 ;
    END
    PORT
      LAYER met4 ;
        RECT 760.420 57.120 762.020 280.160 ;
    END
    PORT
      LAYER met4 ;
        RECT 790.420 57.120 792.020 280.160 ;
    END
    PORT
      LAYER met4 ;
        RECT 820.420 57.120 822.020 280.160 ;
    END
    PORT
      LAYER met4 ;
        RECT 850.420 57.120 852.020 280.160 ;
    END
    PORT
      LAYER met4 ;
        RECT 880.420 57.120 882.020 280.160 ;
    END
    PORT
      LAYER met4 ;
        RECT 700.420 0.000 702.020 57.120 ;
    END
    PORT
      LAYER met4 ;
        RECT 730.420 0.000 732.020 57.120 ;
    END
    PORT
      LAYER met4 ;
        RECT 760.420 0.000 762.020 57.120 ;
    END
    PORT
      LAYER met4 ;
        RECT 790.420 0.000 792.020 57.120 ;
    END
    PORT
      LAYER met4 ;
        RECT 820.420 0.000 822.020 57.120 ;
    END
    PORT
      LAYER met4 ;
        RECT 850.420 0.000 852.020 57.120 ;
    END
    PORT
      LAYER met4 ;
        RECT 880.420 0.000 882.020 57.120 ;
    END
    PORT
      LAYER met4 ;
        RECT 911.100 1395.360 912.700 1452.480 ;
    END
    PORT
      LAYER met4 ;
        RECT 941.100 1395.360 942.700 1452.480 ;
    END
    PORT
      LAYER met4 ;
        RECT 911.100 1172.320 912.700 1395.360 ;
    END
    PORT
      LAYER met4 ;
        RECT 941.100 1172.320 942.700 1395.360 ;
    END
    PORT
      LAYER met4 ;
        RECT 911.100 949.280 912.700 1172.320 ;
    END
    PORT
      LAYER met4 ;
        RECT 941.100 949.280 942.700 1172.320 ;
    END
    PORT
      LAYER met4 ;
        RECT 911.100 726.240 912.700 949.280 ;
    END
    PORT
      LAYER met4 ;
        RECT 941.100 726.240 942.700 949.280 ;
    END
    PORT
      LAYER met4 ;
        RECT 911.100 503.200 912.700 726.240 ;
    END
    PORT
      LAYER met4 ;
        RECT 941.100 503.200 942.700 726.240 ;
    END
    PORT
      LAYER met4 ;
        RECT 911.100 280.160 912.700 503.200 ;
    END
    PORT
      LAYER met4 ;
        RECT 941.100 280.160 942.700 503.200 ;
    END
    PORT
      LAYER met4 ;
        RECT 911.100 57.120 912.700 280.160 ;
    END
    PORT
      LAYER met4 ;
        RECT 941.100 57.120 942.700 280.160 ;
    END
    PORT
      LAYER met4 ;
        RECT 911.100 0.000 912.700 57.120 ;
    END
    PORT
      LAYER met4 ;
        RECT 941.100 0.000 942.700 57.120 ;
    END
  END VGND
  PIN VPWR
    DIRECTION INOUT ;
    USE POWER ;
    PORT
      LAYER met4 ;
        RECT 6.960 1395.360 8.560 1452.480 ;
    END
    PORT
      LAYER met4 ;
        RECT 36.960 1395.360 38.560 1452.480 ;
    END
    PORT
      LAYER met4 ;
        RECT 6.960 1172.320 8.560 1395.360 ;
    END
    PORT
      LAYER met4 ;
        RECT 36.960 1172.320 38.560 1395.360 ;
    END
    PORT
      LAYER met4 ;
        RECT 6.960 949.280 8.560 1172.320 ;
    END
    PORT
      LAYER met4 ;
        RECT 36.960 949.280 38.560 1172.320 ;
    END
    PORT
      LAYER met4 ;
        RECT 6.960 726.240 8.560 949.280 ;
    END
    PORT
      LAYER met4 ;
        RECT 36.960 726.240 38.560 949.280 ;
    END
    PORT
      LAYER met4 ;
        RECT 6.960 503.200 8.560 726.240 ;
    END
    PORT
      LAYER met4 ;
        RECT 36.960 503.200 38.560 726.240 ;
    END
    PORT
      LAYER met4 ;
        RECT 6.960 280.160 8.560 503.200 ;
    END
    PORT
      LAYER met4 ;
        RECT 36.960 280.160 38.560 503.200 ;
    END
    PORT
      LAYER met4 ;
        RECT 6.960 57.120 8.560 280.160 ;
    END
    PORT
      LAYER met4 ;
        RECT 36.960 57.120 38.560 280.160 ;
    END
    PORT
      LAYER met4 ;
        RECT 6.960 0.000 8.560 57.120 ;
    END
    PORT
      LAYER met4 ;
        RECT 36.960 0.000 38.560 57.120 ;
    END
    PORT
      LAYER met4 ;
        RECT 63.080 1395.360 64.680 1452.480 ;
    END
    PORT
      LAYER met4 ;
        RECT 93.080 1395.360 94.680 1452.480 ;
    END
    PORT
      LAYER met4 ;
        RECT 123.080 1395.360 124.680 1452.480 ;
    END
    PORT
      LAYER met4 ;
        RECT 153.080 1395.360 154.680 1452.480 ;
    END
    PORT
      LAYER met4 ;
        RECT 183.080 1395.360 184.680 1452.480 ;
    END
    PORT
      LAYER met4 ;
        RECT 213.080 1395.360 214.680 1452.480 ;
    END
    PORT
      LAYER met4 ;
        RECT 243.080 1395.360 244.680 1452.480 ;
    END
    PORT
      LAYER met4 ;
        RECT 63.080 1172.320 64.680 1395.360 ;
    END
    PORT
      LAYER met4 ;
        RECT 93.080 1172.320 94.680 1395.360 ;
    END
    PORT
      LAYER met4 ;
        RECT 123.080 1172.320 124.680 1395.360 ;
    END
    PORT
      LAYER met4 ;
        RECT 153.080 1172.320 154.680 1395.360 ;
    END
    PORT
      LAYER met4 ;
        RECT 183.080 1172.320 184.680 1395.360 ;
    END
    PORT
      LAYER met4 ;
        RECT 213.080 1172.320 214.680 1395.360 ;
    END
    PORT
      LAYER met4 ;
        RECT 243.080 1172.320 244.680 1395.360 ;
    END
    PORT
      LAYER met4 ;
        RECT 63.080 949.280 64.680 1172.320 ;
    END
    PORT
      LAYER met4 ;
        RECT 93.080 949.280 94.680 1172.320 ;
    END
    PORT
      LAYER met4 ;
        RECT 123.080 949.280 124.680 1172.320 ;
    END
    PORT
      LAYER met4 ;
        RECT 153.080 949.280 154.680 1172.320 ;
    END
    PORT
      LAYER met4 ;
        RECT 183.080 949.280 184.680 1172.320 ;
    END
    PORT
      LAYER met4 ;
        RECT 213.080 949.280 214.680 1172.320 ;
    END
    PORT
      LAYER met4 ;
        RECT 243.080 949.280 244.680 1172.320 ;
    END
    PORT
      LAYER met4 ;
        RECT 63.080 726.240 64.680 949.280 ;
    END
    PORT
      LAYER met4 ;
        RECT 93.080 726.240 94.680 949.280 ;
    END
    PORT
      LAYER met4 ;
        RECT 123.080 726.240 124.680 949.280 ;
    END
    PORT
      LAYER met4 ;
        RECT 153.080 726.240 154.680 949.280 ;
    END
    PORT
      LAYER met4 ;
        RECT 183.080 726.240 184.680 949.280 ;
    END
    PORT
      LAYER met4 ;
        RECT 213.080 726.240 214.680 949.280 ;
    END
    PORT
      LAYER met4 ;
        RECT 243.080 726.240 244.680 949.280 ;
    END
    PORT
      LAYER met4 ;
        RECT 63.080 503.200 64.680 726.240 ;
    END
    PORT
      LAYER met4 ;
        RECT 93.080 503.200 94.680 726.240 ;
    END
    PORT
      LAYER met4 ;
        RECT 123.080 503.200 124.680 726.240 ;
    END
    PORT
      LAYER met4 ;
        RECT 153.080 503.200 154.680 726.240 ;
    END
    PORT
      LAYER met4 ;
        RECT 183.080 503.200 184.680 726.240 ;
    END
    PORT
      LAYER met4 ;
        RECT 213.080 503.200 214.680 726.240 ;
    END
    PORT
      LAYER met4 ;
        RECT 243.080 503.200 244.680 726.240 ;
    END
    PORT
      LAYER met4 ;
        RECT 63.080 280.160 64.680 503.200 ;
    END
    PORT
      LAYER met4 ;
        RECT 93.080 280.160 94.680 503.200 ;
    END
    PORT
      LAYER met4 ;
        RECT 123.080 280.160 124.680 503.200 ;
    END
    PORT
      LAYER met4 ;
        RECT 153.080 280.160 154.680 503.200 ;
    END
    PORT
      LAYER met4 ;
        RECT 183.080 280.160 184.680 503.200 ;
    END
    PORT
      LAYER met4 ;
        RECT 213.080 280.160 214.680 503.200 ;
    END
    PORT
      LAYER met4 ;
        RECT 243.080 280.160 244.680 503.200 ;
    END
    PORT
      LAYER met4 ;
        RECT 63.080 57.120 64.680 280.160 ;
    END
    PORT
      LAYER met4 ;
        RECT 93.080 57.120 94.680 280.160 ;
    END
    PORT
      LAYER met4 ;
        RECT 123.080 57.120 124.680 280.160 ;
    END
    PORT
      LAYER met4 ;
        RECT 153.080 57.120 154.680 280.160 ;
    END
    PORT
      LAYER met4 ;
        RECT 183.080 57.120 184.680 280.160 ;
    END
    PORT
      LAYER met4 ;
        RECT 213.080 57.120 214.680 280.160 ;
    END
    PORT
      LAYER met4 ;
        RECT 243.080 57.120 244.680 280.160 ;
    END
    PORT
      LAYER met4 ;
        RECT 63.080 0.000 64.680 57.120 ;
    END
    PORT
      LAYER met4 ;
        RECT 93.080 0.000 94.680 57.120 ;
    END
    PORT
      LAYER met4 ;
        RECT 123.080 0.000 124.680 57.120 ;
    END
    PORT
      LAYER met4 ;
        RECT 153.080 0.000 154.680 57.120 ;
    END
    PORT
      LAYER met4 ;
        RECT 183.080 0.000 184.680 57.120 ;
    END
    PORT
      LAYER met4 ;
        RECT 213.080 0.000 214.680 57.120 ;
    END
    PORT
      LAYER met4 ;
        RECT 243.080 0.000 244.680 57.120 ;
    END
    PORT
      LAYER met4 ;
        RECT 273.760 1395.360 275.360 1452.480 ;
    END
    PORT
      LAYER met4 ;
        RECT 303.760 1395.360 305.360 1452.480 ;
    END
    PORT
      LAYER met4 ;
        RECT 333.760 1395.360 335.360 1452.480 ;
    END
    PORT
      LAYER met4 ;
        RECT 363.760 1395.360 365.360 1452.480 ;
    END
    PORT
      LAYER met4 ;
        RECT 393.760 1395.360 395.360 1452.480 ;
    END
    PORT
      LAYER met4 ;
        RECT 423.760 1395.360 425.360 1452.480 ;
    END
    PORT
      LAYER met4 ;
        RECT 453.760 1395.360 455.360 1452.480 ;
    END
    PORT
      LAYER met4 ;
        RECT 273.760 1172.320 275.360 1395.360 ;
    END
    PORT
      LAYER met4 ;
        RECT 303.760 1172.320 305.360 1395.360 ;
    END
    PORT
      LAYER met4 ;
        RECT 333.760 1172.320 335.360 1395.360 ;
    END
    PORT
      LAYER met4 ;
        RECT 363.760 1172.320 365.360 1395.360 ;
    END
    PORT
      LAYER met4 ;
        RECT 393.760 1172.320 395.360 1395.360 ;
    END
    PORT
      LAYER met4 ;
        RECT 423.760 1172.320 425.360 1395.360 ;
    END
    PORT
      LAYER met4 ;
        RECT 453.760 1172.320 455.360 1395.360 ;
    END
    PORT
      LAYER met4 ;
        RECT 273.760 949.280 275.360 1172.320 ;
    END
    PORT
      LAYER met4 ;
        RECT 303.760 949.280 305.360 1172.320 ;
    END
    PORT
      LAYER met4 ;
        RECT 333.760 949.280 335.360 1172.320 ;
    END
    PORT
      LAYER met4 ;
        RECT 363.760 949.280 365.360 1172.320 ;
    END
    PORT
      LAYER met4 ;
        RECT 393.760 949.280 395.360 1172.320 ;
    END
    PORT
      LAYER met4 ;
        RECT 423.760 949.280 425.360 1172.320 ;
    END
    PORT
      LAYER met4 ;
        RECT 453.760 949.280 455.360 1172.320 ;
    END
    PORT
      LAYER met4 ;
        RECT 273.760 726.240 275.360 949.280 ;
    END
    PORT
      LAYER met4 ;
        RECT 303.760 726.240 305.360 949.280 ;
    END
    PORT
      LAYER met4 ;
        RECT 333.760 726.240 335.360 949.280 ;
    END
    PORT
      LAYER met4 ;
        RECT 363.760 726.240 365.360 949.280 ;
    END
    PORT
      LAYER met4 ;
        RECT 393.760 726.240 395.360 949.280 ;
    END
    PORT
      LAYER met4 ;
        RECT 423.760 726.240 425.360 949.280 ;
    END
    PORT
      LAYER met4 ;
        RECT 453.760 726.240 455.360 949.280 ;
    END
    PORT
      LAYER met4 ;
        RECT 273.760 503.200 275.360 726.240 ;
    END
    PORT
      LAYER met4 ;
        RECT 303.760 503.200 305.360 726.240 ;
    END
    PORT
      LAYER met4 ;
        RECT 333.760 503.200 335.360 726.240 ;
    END
    PORT
      LAYER met4 ;
        RECT 363.760 503.200 365.360 726.240 ;
    END
    PORT
      LAYER met4 ;
        RECT 393.760 503.200 395.360 726.240 ;
    END
    PORT
      LAYER met4 ;
        RECT 423.760 503.200 425.360 726.240 ;
    END
    PORT
      LAYER met4 ;
        RECT 453.760 503.200 455.360 726.240 ;
    END
    PORT
      LAYER met4 ;
        RECT 273.760 280.160 275.360 503.200 ;
    END
    PORT
      LAYER met4 ;
        RECT 303.760 280.160 305.360 503.200 ;
    END
    PORT
      LAYER met4 ;
        RECT 333.760 280.160 335.360 503.200 ;
    END
    PORT
      LAYER met4 ;
        RECT 363.760 280.160 365.360 503.200 ;
    END
    PORT
      LAYER met4 ;
        RECT 393.760 280.160 395.360 503.200 ;
    END
    PORT
      LAYER met4 ;
        RECT 423.760 280.160 425.360 503.200 ;
    END
    PORT
      LAYER met4 ;
        RECT 453.760 280.160 455.360 503.200 ;
    END
    PORT
      LAYER met4 ;
        RECT 273.760 57.120 275.360 280.160 ;
    END
    PORT
      LAYER met4 ;
        RECT 303.760 57.120 305.360 280.160 ;
    END
    PORT
      LAYER met4 ;
        RECT 333.760 57.120 335.360 280.160 ;
    END
    PORT
      LAYER met4 ;
        RECT 363.760 57.120 365.360 280.160 ;
    END
    PORT
      LAYER met4 ;
        RECT 393.760 57.120 395.360 280.160 ;
    END
    PORT
      LAYER met4 ;
        RECT 423.760 57.120 425.360 280.160 ;
    END
    PORT
      LAYER met4 ;
        RECT 453.760 57.120 455.360 280.160 ;
    END
    PORT
      LAYER met4 ;
        RECT 273.760 0.000 275.360 57.120 ;
    END
    PORT
      LAYER met4 ;
        RECT 303.760 0.000 305.360 57.120 ;
    END
    PORT
      LAYER met4 ;
        RECT 333.760 0.000 335.360 57.120 ;
    END
    PORT
      LAYER met4 ;
        RECT 363.760 0.000 365.360 57.120 ;
    END
    PORT
      LAYER met4 ;
        RECT 393.760 0.000 395.360 57.120 ;
    END
    PORT
      LAYER met4 ;
        RECT 423.760 0.000 425.360 57.120 ;
    END
    PORT
      LAYER met4 ;
        RECT 453.760 0.000 455.360 57.120 ;
    END
    PORT
      LAYER met4 ;
        RECT 484.440 1395.360 486.040 1452.480 ;
    END
    PORT
      LAYER met4 ;
        RECT 514.440 1395.360 516.040 1452.480 ;
    END
    PORT
      LAYER met4 ;
        RECT 544.440 1395.360 546.040 1452.480 ;
    END
    PORT
      LAYER met4 ;
        RECT 574.440 1395.360 576.040 1452.480 ;
    END
    PORT
      LAYER met4 ;
        RECT 604.440 1395.360 606.040 1452.480 ;
    END
    PORT
      LAYER met4 ;
        RECT 634.440 1395.360 636.040 1452.480 ;
    END
    PORT
      LAYER met4 ;
        RECT 664.440 1395.360 666.040 1452.480 ;
    END
    PORT
      LAYER met4 ;
        RECT 484.440 1172.320 486.040 1395.360 ;
    END
    PORT
      LAYER met4 ;
        RECT 514.440 1172.320 516.040 1395.360 ;
    END
    PORT
      LAYER met4 ;
        RECT 544.440 1172.320 546.040 1395.360 ;
    END
    PORT
      LAYER met4 ;
        RECT 574.440 1172.320 576.040 1395.360 ;
    END
    PORT
      LAYER met4 ;
        RECT 604.440 1172.320 606.040 1395.360 ;
    END
    PORT
      LAYER met4 ;
        RECT 634.440 1172.320 636.040 1395.360 ;
    END
    PORT
      LAYER met4 ;
        RECT 664.440 1172.320 666.040 1395.360 ;
    END
    PORT
      LAYER met4 ;
        RECT 484.440 949.280 486.040 1172.320 ;
    END
    PORT
      LAYER met4 ;
        RECT 514.440 949.280 516.040 1172.320 ;
    END
    PORT
      LAYER met4 ;
        RECT 544.440 949.280 546.040 1172.320 ;
    END
    PORT
      LAYER met4 ;
        RECT 574.440 949.280 576.040 1172.320 ;
    END
    PORT
      LAYER met4 ;
        RECT 604.440 949.280 606.040 1172.320 ;
    END
    PORT
      LAYER met4 ;
        RECT 634.440 949.280 636.040 1172.320 ;
    END
    PORT
      LAYER met4 ;
        RECT 664.440 949.280 666.040 1172.320 ;
    END
    PORT
      LAYER met4 ;
        RECT 484.440 726.240 486.040 949.280 ;
    END
    PORT
      LAYER met4 ;
        RECT 514.440 726.240 516.040 949.280 ;
    END
    PORT
      LAYER met4 ;
        RECT 544.440 726.240 546.040 949.280 ;
    END
    PORT
      LAYER met4 ;
        RECT 574.440 726.240 576.040 949.280 ;
    END
    PORT
      LAYER met4 ;
        RECT 604.440 726.240 606.040 949.280 ;
    END
    PORT
      LAYER met4 ;
        RECT 634.440 726.240 636.040 949.280 ;
    END
    PORT
      LAYER met4 ;
        RECT 664.440 726.240 666.040 949.280 ;
    END
    PORT
      LAYER met4 ;
        RECT 484.440 503.200 486.040 726.240 ;
    END
    PORT
      LAYER met4 ;
        RECT 514.440 503.200 516.040 726.240 ;
    END
    PORT
      LAYER met4 ;
        RECT 544.440 503.200 546.040 726.240 ;
    END
    PORT
      LAYER met4 ;
        RECT 574.440 503.200 576.040 726.240 ;
    END
    PORT
      LAYER met4 ;
        RECT 604.440 503.200 606.040 726.240 ;
    END
    PORT
      LAYER met4 ;
        RECT 634.440 503.200 636.040 726.240 ;
    END
    PORT
      LAYER met4 ;
        RECT 664.440 503.200 666.040 726.240 ;
    END
    PORT
      LAYER met4 ;
        RECT 484.440 280.160 486.040 503.200 ;
    END
    PORT
      LAYER met4 ;
        RECT 514.440 280.160 516.040 503.200 ;
    END
    PORT
      LAYER met4 ;
        RECT 544.440 280.160 546.040 503.200 ;
    END
    PORT
      LAYER met4 ;
        RECT 574.440 280.160 576.040 503.200 ;
    END
    PORT
      LAYER met4 ;
        RECT 604.440 280.160 606.040 503.200 ;
    END
    PORT
      LAYER met4 ;
        RECT 634.440 280.160 636.040 503.200 ;
    END
    PORT
      LAYER met4 ;
        RECT 664.440 280.160 666.040 503.200 ;
    END
    PORT
      LAYER met4 ;
        RECT 484.440 57.120 486.040 280.160 ;
    END
    PORT
      LAYER met4 ;
        RECT 514.440 57.120 516.040 280.160 ;
    END
    PORT
      LAYER met4 ;
        RECT 544.440 57.120 546.040 280.160 ;
    END
    PORT
      LAYER met4 ;
        RECT 574.440 57.120 576.040 280.160 ;
    END
    PORT
      LAYER met4 ;
        RECT 604.440 57.120 606.040 280.160 ;
    END
    PORT
      LAYER met4 ;
        RECT 634.440 57.120 636.040 280.160 ;
    END
    PORT
      LAYER met4 ;
        RECT 664.440 57.120 666.040 280.160 ;
    END
    PORT
      LAYER met4 ;
        RECT 484.440 0.000 486.040 57.120 ;
    END
    PORT
      LAYER met4 ;
        RECT 514.440 0.000 516.040 57.120 ;
    END
    PORT
      LAYER met4 ;
        RECT 544.440 0.000 546.040 57.120 ;
    END
    PORT
      LAYER met4 ;
        RECT 574.440 0.000 576.040 57.120 ;
    END
    PORT
      LAYER met4 ;
        RECT 604.440 0.000 606.040 57.120 ;
    END
    PORT
      LAYER met4 ;
        RECT 634.440 0.000 636.040 57.120 ;
    END
    PORT
      LAYER met4 ;
        RECT 664.440 0.000 666.040 57.120 ;
    END
    PORT
      LAYER met4 ;
        RECT 695.120 1395.360 696.720 1452.480 ;
    END
    PORT
      LAYER met4 ;
        RECT 725.120 1395.360 726.720 1452.480 ;
    END
    PORT
      LAYER met4 ;
        RECT 755.120 1395.360 756.720 1452.480 ;
    END
    PORT
      LAYER met4 ;
        RECT 785.120 1395.360 786.720 1452.480 ;
    END
    PORT
      LAYER met4 ;
        RECT 815.120 1395.360 816.720 1452.480 ;
    END
    PORT
      LAYER met4 ;
        RECT 845.120 1395.360 846.720 1452.480 ;
    END
    PORT
      LAYER met4 ;
        RECT 875.120 1395.360 876.720 1452.480 ;
    END
    PORT
      LAYER met4 ;
        RECT 695.120 1172.320 696.720 1395.360 ;
    END
    PORT
      LAYER met4 ;
        RECT 725.120 1172.320 726.720 1395.360 ;
    END
    PORT
      LAYER met4 ;
        RECT 755.120 1172.320 756.720 1395.360 ;
    END
    PORT
      LAYER met4 ;
        RECT 785.120 1172.320 786.720 1395.360 ;
    END
    PORT
      LAYER met4 ;
        RECT 815.120 1172.320 816.720 1395.360 ;
    END
    PORT
      LAYER met4 ;
        RECT 845.120 1172.320 846.720 1395.360 ;
    END
    PORT
      LAYER met4 ;
        RECT 875.120 1172.320 876.720 1395.360 ;
    END
    PORT
      LAYER met4 ;
        RECT 695.120 949.280 696.720 1172.320 ;
    END
    PORT
      LAYER met4 ;
        RECT 725.120 949.280 726.720 1172.320 ;
    END
    PORT
      LAYER met4 ;
        RECT 755.120 949.280 756.720 1172.320 ;
    END
    PORT
      LAYER met4 ;
        RECT 785.120 949.280 786.720 1172.320 ;
    END
    PORT
      LAYER met4 ;
        RECT 815.120 949.280 816.720 1172.320 ;
    END
    PORT
      LAYER met4 ;
        RECT 845.120 949.280 846.720 1172.320 ;
    END
    PORT
      LAYER met4 ;
        RECT 875.120 949.280 876.720 1172.320 ;
    END
    PORT
      LAYER met4 ;
        RECT 695.120 726.240 696.720 949.280 ;
    END
    PORT
      LAYER met4 ;
        RECT 725.120 726.240 726.720 949.280 ;
    END
    PORT
      LAYER met4 ;
        RECT 755.120 726.240 756.720 949.280 ;
    END
    PORT
      LAYER met4 ;
        RECT 785.120 726.240 786.720 949.280 ;
    END
    PORT
      LAYER met4 ;
        RECT 815.120 726.240 816.720 949.280 ;
    END
    PORT
      LAYER met4 ;
        RECT 845.120 726.240 846.720 949.280 ;
    END
    PORT
      LAYER met4 ;
        RECT 875.120 726.240 876.720 949.280 ;
    END
    PORT
      LAYER met4 ;
        RECT 695.120 503.200 696.720 726.240 ;
    END
    PORT
      LAYER met4 ;
        RECT 725.120 503.200 726.720 726.240 ;
    END
    PORT
      LAYER met4 ;
        RECT 755.120 503.200 756.720 726.240 ;
    END
    PORT
      LAYER met4 ;
        RECT 785.120 503.200 786.720 726.240 ;
    END
    PORT
      LAYER met4 ;
        RECT 815.120 503.200 816.720 726.240 ;
    END
    PORT
      LAYER met4 ;
        RECT 845.120 503.200 846.720 726.240 ;
    END
    PORT
      LAYER met4 ;
        RECT 875.120 503.200 876.720 726.240 ;
    END
    PORT
      LAYER met4 ;
        RECT 695.120 280.160 696.720 503.200 ;
    END
    PORT
      LAYER met4 ;
        RECT 725.120 280.160 726.720 503.200 ;
    END
    PORT
      LAYER met4 ;
        RECT 755.120 280.160 756.720 503.200 ;
    END
    PORT
      LAYER met4 ;
        RECT 785.120 280.160 786.720 503.200 ;
    END
    PORT
      LAYER met4 ;
        RECT 815.120 280.160 816.720 503.200 ;
    END
    PORT
      LAYER met4 ;
        RECT 845.120 280.160 846.720 503.200 ;
    END
    PORT
      LAYER met4 ;
        RECT 875.120 280.160 876.720 503.200 ;
    END
    PORT
      LAYER met4 ;
        RECT 695.120 57.120 696.720 280.160 ;
    END
    PORT
      LAYER met4 ;
        RECT 725.120 57.120 726.720 280.160 ;
    END
    PORT
      LAYER met4 ;
        RECT 755.120 57.120 756.720 280.160 ;
    END
    PORT
      LAYER met4 ;
        RECT 785.120 57.120 786.720 280.160 ;
    END
    PORT
      LAYER met4 ;
        RECT 815.120 57.120 816.720 280.160 ;
    END
    PORT
      LAYER met4 ;
        RECT 845.120 57.120 846.720 280.160 ;
    END
    PORT
      LAYER met4 ;
        RECT 875.120 57.120 876.720 280.160 ;
    END
    PORT
      LAYER met4 ;
        RECT 695.120 0.000 696.720 57.120 ;
    END
    PORT
      LAYER met4 ;
        RECT 725.120 0.000 726.720 57.120 ;
    END
    PORT
      LAYER met4 ;
        RECT 755.120 0.000 756.720 57.120 ;
    END
    PORT
      LAYER met4 ;
        RECT 785.120 0.000 786.720 57.120 ;
    END
    PORT
      LAYER met4 ;
        RECT 815.120 0.000 816.720 57.120 ;
    END
    PORT
      LAYER met4 ;
        RECT 845.120 0.000 846.720 57.120 ;
    END
    PORT
      LAYER met4 ;
        RECT 875.120 0.000 876.720 57.120 ;
    END
    PORT
      LAYER met4 ;
        RECT 905.800 1395.360 907.400 1452.480 ;
    END
    PORT
      LAYER met4 ;
        RECT 935.800 1395.360 937.400 1452.480 ;
    END
    PORT
      LAYER met4 ;
        RECT 905.800 1172.320 907.400 1395.360 ;
    END
    PORT
      LAYER met4 ;
        RECT 935.800 1172.320 937.400 1395.360 ;
    END
    PORT
      LAYER met4 ;
        RECT 905.800 949.280 907.400 1172.320 ;
    END
    PORT
      LAYER met4 ;
        RECT 935.800 949.280 937.400 1172.320 ;
    END
    PORT
      LAYER met4 ;
        RECT 905.800 726.240 907.400 949.280 ;
    END
    PORT
      LAYER met4 ;
        RECT 935.800 726.240 937.400 949.280 ;
    END
    PORT
      LAYER met4 ;
        RECT 905.800 503.200 907.400 726.240 ;
    END
    PORT
      LAYER met4 ;
        RECT 935.800 503.200 937.400 726.240 ;
    END
    PORT
      LAYER met4 ;
        RECT 905.800 280.160 907.400 503.200 ;
    END
    PORT
      LAYER met4 ;
        RECT 935.800 280.160 937.400 503.200 ;
    END
    PORT
      LAYER met4 ;
        RECT 905.800 57.120 907.400 280.160 ;
    END
    PORT
      LAYER met4 ;
        RECT 935.800 57.120 937.400 280.160 ;
    END
    PORT
      LAYER met4 ;
        RECT 905.800 0.000 907.400 57.120 ;
    END
    PORT
      LAYER met4 ;
        RECT 935.800 0.000 937.400 57.120 ;
    END
  END VPWR
  OBS
      LAYER nwell ;
        RECT 2.570 2.635 952.390 1449.950 ;
      LAYER li1 ;
        RECT 2.760 2.635 952.200 1449.845 ;
      LAYER met1 ;
        RECT 0.530 0.380 953.510 1450.400 ;
      LAYER met2 ;
        RECT 0.160 0.560 953.490 1452.480 ;
        RECT 0.160 0.270 4.410 0.560 ;
        RECT 5.250 0.270 6.710 0.560 ;
        RECT 7.550 0.270 9.010 0.560 ;
        RECT 9.850 0.270 11.310 0.560 ;
        RECT 12.150 0.270 13.610 0.560 ;
        RECT 14.450 0.270 15.910 0.560 ;
        RECT 16.750 0.270 18.210 0.560 ;
        RECT 19.050 0.270 20.510 0.560 ;
        RECT 21.350 0.270 22.810 0.560 ;
        RECT 23.650 0.270 25.110 0.560 ;
        RECT 25.950 0.270 27.410 0.560 ;
        RECT 28.250 0.270 29.710 0.560 ;
        RECT 30.550 0.270 32.010 0.560 ;
        RECT 32.850 0.270 34.310 0.560 ;
        RECT 35.150 0.270 36.610 0.560 ;
        RECT 37.450 0.270 38.910 0.560 ;
        RECT 39.750 0.270 41.210 0.560 ;
        RECT 42.050 0.270 43.510 0.560 ;
        RECT 44.350 0.270 45.810 0.560 ;
        RECT 46.650 0.270 48.110 0.560 ;
        RECT 48.950 0.270 50.410 0.560 ;
        RECT 51.250 0.270 64.670 0.560 ;
        RECT 65.510 0.270 74.790 0.560 ;
        RECT 75.630 0.270 84.910 0.560 ;
        RECT 85.750 0.270 95.030 0.560 ;
        RECT 95.870 0.270 105.150 0.560 ;
        RECT 105.990 0.270 115.270 0.560 ;
        RECT 116.110 0.270 125.390 0.560 ;
        RECT 126.230 0.270 135.510 0.560 ;
        RECT 136.350 0.270 145.630 0.560 ;
        RECT 146.470 0.270 155.750 0.560 ;
        RECT 156.590 0.270 165.870 0.560 ;
        RECT 166.710 0.270 175.990 0.560 ;
        RECT 176.830 0.270 186.110 0.560 ;
        RECT 186.950 0.270 196.230 0.560 ;
        RECT 197.070 0.270 206.350 0.560 ;
        RECT 207.190 0.270 216.470 0.560 ;
        RECT 217.310 0.270 226.590 0.560 ;
        RECT 227.430 0.270 236.710 0.560 ;
        RECT 237.550 0.270 246.830 0.560 ;
        RECT 247.670 0.270 256.950 0.560 ;
        RECT 257.790 0.270 275.350 0.560 ;
        RECT 276.190 0.270 285.470 0.560 ;
        RECT 286.310 0.270 295.590 0.560 ;
        RECT 296.430 0.270 305.710 0.560 ;
        RECT 306.550 0.270 315.830 0.560 ;
        RECT 316.670 0.270 325.950 0.560 ;
        RECT 326.790 0.270 336.070 0.560 ;
        RECT 336.910 0.270 346.190 0.560 ;
        RECT 347.030 0.270 356.310 0.560 ;
        RECT 357.150 0.270 366.430 0.560 ;
        RECT 367.270 0.270 376.550 0.560 ;
        RECT 377.390 0.270 386.670 0.560 ;
        RECT 387.510 0.270 396.790 0.560 ;
        RECT 397.630 0.270 406.910 0.560 ;
        RECT 407.750 0.270 417.030 0.560 ;
        RECT 417.870 0.270 427.150 0.560 ;
        RECT 427.990 0.270 437.270 0.560 ;
        RECT 438.110 0.270 447.390 0.560 ;
        RECT 448.230 0.270 457.510 0.560 ;
        RECT 458.350 0.270 467.630 0.560 ;
        RECT 468.470 0.270 486.030 0.560 ;
        RECT 486.870 0.270 496.150 0.560 ;
        RECT 496.990 0.270 506.270 0.560 ;
        RECT 507.110 0.270 516.390 0.560 ;
        RECT 517.230 0.270 526.510 0.560 ;
        RECT 527.350 0.270 536.630 0.560 ;
        RECT 537.470 0.270 546.750 0.560 ;
        RECT 547.590 0.270 556.870 0.560 ;
        RECT 557.710 0.270 566.990 0.560 ;
        RECT 567.830 0.270 577.110 0.560 ;
        RECT 577.950 0.270 587.230 0.560 ;
        RECT 588.070 0.270 597.350 0.560 ;
        RECT 598.190 0.270 607.470 0.560 ;
        RECT 608.310 0.270 617.590 0.560 ;
        RECT 618.430 0.270 627.710 0.560 ;
        RECT 628.550 0.270 637.830 0.560 ;
        RECT 638.670 0.270 647.950 0.560 ;
        RECT 648.790 0.270 658.070 0.560 ;
        RECT 658.910 0.270 668.190 0.560 ;
        RECT 669.030 0.270 678.310 0.560 ;
        RECT 679.150 0.270 696.710 0.560 ;
        RECT 697.550 0.270 706.830 0.560 ;
        RECT 707.670 0.270 716.950 0.560 ;
        RECT 717.790 0.270 727.070 0.560 ;
        RECT 727.910 0.270 737.190 0.560 ;
        RECT 738.030 0.270 747.310 0.560 ;
        RECT 748.150 0.270 757.430 0.560 ;
        RECT 758.270 0.270 767.550 0.560 ;
        RECT 768.390 0.270 777.670 0.560 ;
        RECT 778.510 0.270 787.790 0.560 ;
        RECT 788.630 0.270 797.910 0.560 ;
        RECT 798.750 0.270 808.030 0.560 ;
        RECT 808.870 0.270 818.150 0.560 ;
        RECT 818.990 0.270 828.270 0.560 ;
        RECT 829.110 0.270 838.390 0.560 ;
        RECT 839.230 0.270 848.510 0.560 ;
        RECT 849.350 0.270 858.630 0.560 ;
        RECT 859.470 0.270 868.750 0.560 ;
        RECT 869.590 0.270 878.870 0.560 ;
        RECT 879.710 0.270 888.990 0.560 ;
        RECT 889.830 0.270 900.030 0.560 ;
        RECT 900.870 0.270 902.790 0.560 ;
        RECT 903.630 0.270 905.550 0.560 ;
        RECT 906.390 0.270 908.310 0.560 ;
        RECT 909.150 0.270 911.070 0.560 ;
        RECT 911.910 0.270 913.830 0.560 ;
        RECT 914.670 0.270 916.590 0.560 ;
        RECT 917.430 0.270 919.350 0.560 ;
        RECT 920.190 0.270 922.110 0.560 ;
        RECT 922.950 0.270 924.870 0.560 ;
        RECT 925.710 0.270 927.630 0.560 ;
        RECT 928.470 0.270 930.390 0.560 ;
        RECT 931.230 0.270 933.150 0.560 ;
        RECT 933.990 0.270 935.910 0.560 ;
        RECT 936.750 0.270 938.670 0.560 ;
        RECT 939.510 0.270 941.430 0.560 ;
        RECT 942.270 0.270 944.190 0.560 ;
        RECT 945.030 0.270 946.950 0.560 ;
        RECT 947.790 0.270 949.710 0.560 ;
        RECT 950.550 0.270 952.470 0.560 ;
        RECT 953.310 0.270 953.490 0.560 ;
      LAYER met3 ;
        RECT 0.600 1445.360 954.960 1449.925 ;
        RECT 1.000 1401.800 954.960 1445.360 ;
        RECT 0.600 1384.160 954.960 1401.800 ;
        RECT 1.000 1382.760 954.960 1384.160 ;
        RECT 0.600 1378.720 954.960 1382.760 ;
        RECT 1.000 1377.320 954.960 1378.720 ;
        RECT 0.600 1373.280 954.960 1377.320 ;
        RECT 1.000 1371.880 954.960 1373.280 ;
        RECT 0.600 1367.840 954.960 1371.880 ;
        RECT 1.000 1366.440 954.960 1367.840 ;
        RECT 0.600 1362.400 954.960 1366.440 ;
        RECT 1.000 1361.000 954.960 1362.400 ;
        RECT 0.600 1356.960 954.960 1361.000 ;
        RECT 1.000 1355.560 954.960 1356.960 ;
        RECT 0.600 1351.520 954.960 1355.560 ;
        RECT 1.000 1350.120 954.960 1351.520 ;
        RECT 0.600 1346.080 954.960 1350.120 ;
        RECT 1.000 1344.680 954.960 1346.080 ;
        RECT 0.600 1340.640 954.960 1344.680 ;
        RECT 1.000 1339.240 954.960 1340.640 ;
        RECT 0.600 1335.200 954.960 1339.240 ;
        RECT 1.000 1333.800 954.960 1335.200 ;
        RECT 0.600 1329.760 954.960 1333.800 ;
        RECT 1.000 1328.360 954.960 1329.760 ;
        RECT 0.600 1324.320 954.960 1328.360 ;
        RECT 1.000 1322.920 954.960 1324.320 ;
        RECT 0.600 1318.880 954.960 1322.920 ;
        RECT 1.000 1317.480 954.960 1318.880 ;
        RECT 0.600 1313.440 954.960 1317.480 ;
        RECT 1.000 1312.040 954.960 1313.440 ;
        RECT 0.600 1308.000 954.960 1312.040 ;
        RECT 1.000 1306.600 954.960 1308.000 ;
        RECT 0.600 1302.560 954.960 1306.600 ;
        RECT 1.000 1301.160 954.960 1302.560 ;
        RECT 0.600 1297.120 954.960 1301.160 ;
        RECT 1.000 1295.720 954.960 1297.120 ;
        RECT 0.600 1291.680 954.960 1295.720 ;
        RECT 1.000 1290.280 954.960 1291.680 ;
        RECT 0.600 1286.240 954.960 1290.280 ;
        RECT 1.000 1284.840 954.960 1286.240 ;
        RECT 0.600 1280.800 954.960 1284.840 ;
        RECT 1.000 1279.400 954.960 1280.800 ;
        RECT 0.600 1275.360 954.960 1279.400 ;
        RECT 1.000 1273.960 954.960 1275.360 ;
        RECT 0.600 1269.920 954.960 1273.960 ;
        RECT 1.000 1268.520 954.960 1269.920 ;
        RECT 0.600 1264.480 954.960 1268.520 ;
        RECT 1.000 1263.080 954.960 1264.480 ;
        RECT 0.600 1259.040 954.960 1263.080 ;
        RECT 1.000 1257.640 954.960 1259.040 ;
        RECT 0.600 1253.600 954.960 1257.640 ;
        RECT 1.000 1252.200 954.960 1253.600 ;
        RECT 0.600 1248.160 954.960 1252.200 ;
        RECT 1.000 1246.760 954.960 1248.160 ;
        RECT 0.600 1242.720 954.960 1246.760 ;
        RECT 1.000 1241.320 954.960 1242.720 ;
        RECT 0.600 1237.280 954.960 1241.320 ;
        RECT 1.000 1235.880 954.960 1237.280 ;
        RECT 0.600 1231.840 954.960 1235.880 ;
        RECT 1.000 1230.440 954.960 1231.840 ;
        RECT 0.600 1226.400 954.960 1230.440 ;
        RECT 1.000 1225.000 954.960 1226.400 ;
        RECT 0.600 1220.960 954.960 1225.000 ;
        RECT 1.000 1219.560 954.960 1220.960 ;
        RECT 0.600 1215.520 954.960 1219.560 ;
        RECT 1.000 1214.120 954.960 1215.520 ;
        RECT 0.600 1210.080 954.960 1214.120 ;
        RECT 1.000 1208.680 953.960 1210.080 ;
        RECT 0.600 1204.640 954.960 1208.680 ;
        RECT 1.000 1203.240 953.960 1204.640 ;
        RECT 0.600 1199.200 954.960 1203.240 ;
        RECT 1.000 1197.800 953.960 1199.200 ;
        RECT 0.600 1193.760 954.960 1197.800 ;
        RECT 1.000 1192.360 953.960 1193.760 ;
        RECT 0.600 1188.320 954.960 1192.360 ;
        RECT 1.000 1186.920 953.960 1188.320 ;
        RECT 0.600 1182.880 954.960 1186.920 ;
        RECT 1.000 1181.480 953.960 1182.880 ;
        RECT 0.600 1161.120 954.960 1181.480 ;
        RECT 1.000 1159.720 954.960 1161.120 ;
        RECT 0.600 1155.680 954.960 1159.720 ;
        RECT 1.000 1154.280 954.960 1155.680 ;
        RECT 0.600 1150.240 954.960 1154.280 ;
        RECT 1.000 1148.840 954.960 1150.240 ;
        RECT 0.600 1144.800 954.960 1148.840 ;
        RECT 1.000 1143.400 954.960 1144.800 ;
        RECT 0.600 1139.360 954.960 1143.400 ;
        RECT 1.000 1137.960 954.960 1139.360 ;
        RECT 0.600 1133.920 954.960 1137.960 ;
        RECT 1.000 1132.520 954.960 1133.920 ;
        RECT 0.600 1128.480 954.960 1132.520 ;
        RECT 1.000 1127.080 954.960 1128.480 ;
        RECT 0.600 1123.040 954.960 1127.080 ;
        RECT 1.000 1121.640 954.960 1123.040 ;
        RECT 0.600 1117.600 954.960 1121.640 ;
        RECT 1.000 1116.200 954.960 1117.600 ;
        RECT 0.600 1112.160 954.960 1116.200 ;
        RECT 1.000 1110.760 954.960 1112.160 ;
        RECT 0.600 1106.720 954.960 1110.760 ;
        RECT 1.000 1105.320 954.960 1106.720 ;
        RECT 0.600 1101.280 954.960 1105.320 ;
        RECT 1.000 1099.880 954.960 1101.280 ;
        RECT 0.600 1095.840 954.960 1099.880 ;
        RECT 1.000 1094.440 954.960 1095.840 ;
        RECT 0.600 1090.400 954.960 1094.440 ;
        RECT 1.000 1089.000 954.960 1090.400 ;
        RECT 0.600 1084.960 954.960 1089.000 ;
        RECT 1.000 1083.560 954.960 1084.960 ;
        RECT 0.600 1079.520 954.960 1083.560 ;
        RECT 1.000 1078.120 954.960 1079.520 ;
        RECT 0.600 1074.080 954.960 1078.120 ;
        RECT 1.000 1072.680 954.960 1074.080 ;
        RECT 0.600 1068.640 954.960 1072.680 ;
        RECT 1.000 1067.240 954.960 1068.640 ;
        RECT 0.600 1063.200 954.960 1067.240 ;
        RECT 1.000 1061.800 954.960 1063.200 ;
        RECT 0.600 1057.760 954.960 1061.800 ;
        RECT 1.000 1056.360 954.960 1057.760 ;
        RECT 0.600 1052.320 954.960 1056.360 ;
        RECT 1.000 1050.920 954.960 1052.320 ;
        RECT 0.600 1046.880 954.960 1050.920 ;
        RECT 1.000 1045.480 954.960 1046.880 ;
        RECT 0.600 1041.440 954.960 1045.480 ;
        RECT 1.000 1040.040 954.960 1041.440 ;
        RECT 0.600 1036.000 954.960 1040.040 ;
        RECT 1.000 1034.600 954.960 1036.000 ;
        RECT 0.600 1030.560 954.960 1034.600 ;
        RECT 1.000 1029.160 954.960 1030.560 ;
        RECT 0.600 1025.120 954.960 1029.160 ;
        RECT 1.000 1023.720 954.960 1025.120 ;
        RECT 0.600 1019.680 954.960 1023.720 ;
        RECT 1.000 1018.280 954.960 1019.680 ;
        RECT 0.600 1014.240 954.960 1018.280 ;
        RECT 1.000 1012.840 954.960 1014.240 ;
        RECT 0.600 1008.800 954.960 1012.840 ;
        RECT 1.000 1007.400 954.960 1008.800 ;
        RECT 0.600 1003.360 954.960 1007.400 ;
        RECT 1.000 1001.960 954.960 1003.360 ;
        RECT 0.600 997.920 954.960 1001.960 ;
        RECT 1.000 996.520 954.960 997.920 ;
        RECT 0.600 992.480 954.960 996.520 ;
        RECT 1.000 991.080 954.960 992.480 ;
        RECT 0.600 987.040 954.960 991.080 ;
        RECT 1.000 985.640 953.960 987.040 ;
        RECT 0.600 981.600 954.960 985.640 ;
        RECT 1.000 980.200 953.960 981.600 ;
        RECT 0.600 976.160 954.960 980.200 ;
        RECT 1.000 974.760 953.960 976.160 ;
        RECT 0.600 970.720 954.960 974.760 ;
        RECT 1.000 969.320 953.960 970.720 ;
        RECT 0.600 965.280 954.960 969.320 ;
        RECT 1.000 963.880 953.960 965.280 ;
        RECT 0.600 959.840 954.960 963.880 ;
        RECT 1.000 958.440 953.960 959.840 ;
        RECT 0.600 938.080 954.960 958.440 ;
        RECT 1.000 936.680 954.960 938.080 ;
        RECT 0.600 932.640 954.960 936.680 ;
        RECT 1.000 931.240 954.960 932.640 ;
        RECT 0.600 927.200 954.960 931.240 ;
        RECT 1.000 925.800 954.960 927.200 ;
        RECT 0.600 921.760 954.960 925.800 ;
        RECT 1.000 920.360 954.960 921.760 ;
        RECT 0.600 916.320 954.960 920.360 ;
        RECT 1.000 914.920 954.960 916.320 ;
        RECT 0.600 910.880 954.960 914.920 ;
        RECT 1.000 909.480 954.960 910.880 ;
        RECT 0.600 905.440 954.960 909.480 ;
        RECT 1.000 904.040 954.960 905.440 ;
        RECT 0.600 900.000 954.960 904.040 ;
        RECT 1.000 898.600 954.960 900.000 ;
        RECT 0.600 894.560 954.960 898.600 ;
        RECT 1.000 893.160 954.960 894.560 ;
        RECT 0.600 889.120 954.960 893.160 ;
        RECT 1.000 887.720 954.960 889.120 ;
        RECT 0.600 883.680 954.960 887.720 ;
        RECT 1.000 882.280 954.960 883.680 ;
        RECT 0.600 878.240 954.960 882.280 ;
        RECT 1.000 876.840 954.960 878.240 ;
        RECT 0.600 872.800 954.960 876.840 ;
        RECT 1.000 871.400 954.960 872.800 ;
        RECT 0.600 867.360 954.960 871.400 ;
        RECT 1.000 865.960 954.960 867.360 ;
        RECT 0.600 861.920 954.960 865.960 ;
        RECT 1.000 860.520 954.960 861.920 ;
        RECT 0.600 856.480 954.960 860.520 ;
        RECT 1.000 855.080 954.960 856.480 ;
        RECT 0.600 851.040 954.960 855.080 ;
        RECT 1.000 849.640 954.960 851.040 ;
        RECT 0.600 845.600 954.960 849.640 ;
        RECT 1.000 844.200 954.960 845.600 ;
        RECT 0.600 840.160 954.960 844.200 ;
        RECT 1.000 838.760 954.960 840.160 ;
        RECT 0.600 834.720 954.960 838.760 ;
        RECT 1.000 833.320 954.960 834.720 ;
        RECT 0.600 829.280 954.960 833.320 ;
        RECT 1.000 827.880 954.960 829.280 ;
        RECT 0.600 823.840 954.960 827.880 ;
        RECT 1.000 822.440 954.960 823.840 ;
        RECT 0.600 818.400 954.960 822.440 ;
        RECT 1.000 817.000 954.960 818.400 ;
        RECT 0.600 812.960 954.960 817.000 ;
        RECT 1.000 811.560 954.960 812.960 ;
        RECT 0.600 807.520 954.960 811.560 ;
        RECT 1.000 806.120 954.960 807.520 ;
        RECT 0.600 802.080 954.960 806.120 ;
        RECT 1.000 800.680 954.960 802.080 ;
        RECT 0.600 796.640 954.960 800.680 ;
        RECT 1.000 795.240 954.960 796.640 ;
        RECT 0.600 791.200 954.960 795.240 ;
        RECT 1.000 789.800 954.960 791.200 ;
        RECT 0.600 785.760 954.960 789.800 ;
        RECT 1.000 784.360 954.960 785.760 ;
        RECT 0.600 780.320 954.960 784.360 ;
        RECT 1.000 778.920 954.960 780.320 ;
        RECT 0.600 774.880 954.960 778.920 ;
        RECT 1.000 773.480 954.960 774.880 ;
        RECT 0.600 769.440 954.960 773.480 ;
        RECT 1.000 768.040 954.960 769.440 ;
        RECT 0.600 764.000 954.960 768.040 ;
        RECT 1.000 762.600 953.960 764.000 ;
        RECT 0.600 758.560 954.960 762.600 ;
        RECT 1.000 757.160 953.960 758.560 ;
        RECT 0.600 753.120 954.960 757.160 ;
        RECT 1.000 751.720 953.960 753.120 ;
        RECT 0.600 747.680 954.960 751.720 ;
        RECT 1.000 746.280 953.960 747.680 ;
        RECT 0.600 742.240 954.960 746.280 ;
        RECT 1.000 740.840 953.960 742.240 ;
        RECT 0.600 736.800 954.960 740.840 ;
        RECT 1.000 735.400 953.960 736.800 ;
        RECT 0.600 715.040 954.960 735.400 ;
        RECT 1.000 713.640 954.960 715.040 ;
        RECT 0.600 709.600 954.960 713.640 ;
        RECT 1.000 708.200 954.960 709.600 ;
        RECT 0.600 704.160 954.960 708.200 ;
        RECT 1.000 702.760 954.960 704.160 ;
        RECT 0.600 698.720 954.960 702.760 ;
        RECT 1.000 697.320 954.960 698.720 ;
        RECT 0.600 693.280 954.960 697.320 ;
        RECT 1.000 691.880 954.960 693.280 ;
        RECT 0.600 687.840 954.960 691.880 ;
        RECT 1.000 686.440 954.960 687.840 ;
        RECT 0.600 682.400 954.960 686.440 ;
        RECT 1.000 681.000 954.960 682.400 ;
        RECT 0.600 676.960 954.960 681.000 ;
        RECT 1.000 675.560 954.960 676.960 ;
        RECT 0.600 671.520 954.960 675.560 ;
        RECT 1.000 670.120 954.960 671.520 ;
        RECT 0.600 666.080 954.960 670.120 ;
        RECT 1.000 664.680 954.960 666.080 ;
        RECT 0.600 660.640 954.960 664.680 ;
        RECT 1.000 659.240 954.960 660.640 ;
        RECT 0.600 655.200 954.960 659.240 ;
        RECT 1.000 653.800 954.960 655.200 ;
        RECT 0.600 649.760 954.960 653.800 ;
        RECT 1.000 648.360 954.960 649.760 ;
        RECT 0.600 644.320 954.960 648.360 ;
        RECT 1.000 642.920 954.960 644.320 ;
        RECT 0.600 638.880 954.960 642.920 ;
        RECT 1.000 637.480 954.960 638.880 ;
        RECT 0.600 633.440 954.960 637.480 ;
        RECT 1.000 632.040 954.960 633.440 ;
        RECT 0.600 628.000 954.960 632.040 ;
        RECT 1.000 626.600 954.960 628.000 ;
        RECT 0.600 622.560 954.960 626.600 ;
        RECT 1.000 621.160 954.960 622.560 ;
        RECT 0.600 617.120 954.960 621.160 ;
        RECT 1.000 615.720 954.960 617.120 ;
        RECT 0.600 611.680 954.960 615.720 ;
        RECT 1.000 610.280 954.960 611.680 ;
        RECT 0.600 606.240 954.960 610.280 ;
        RECT 1.000 604.840 954.960 606.240 ;
        RECT 0.600 600.800 954.960 604.840 ;
        RECT 1.000 599.400 954.960 600.800 ;
        RECT 0.600 595.360 954.960 599.400 ;
        RECT 1.000 593.960 954.960 595.360 ;
        RECT 0.600 589.920 954.960 593.960 ;
        RECT 1.000 588.520 954.960 589.920 ;
        RECT 0.600 584.480 954.960 588.520 ;
        RECT 1.000 583.080 954.960 584.480 ;
        RECT 0.600 579.040 954.960 583.080 ;
        RECT 1.000 577.640 954.960 579.040 ;
        RECT 0.600 573.600 954.960 577.640 ;
        RECT 1.000 572.200 954.960 573.600 ;
        RECT 0.600 568.160 954.960 572.200 ;
        RECT 1.000 566.760 954.960 568.160 ;
        RECT 0.600 562.720 954.960 566.760 ;
        RECT 1.000 561.320 954.960 562.720 ;
        RECT 0.600 557.280 954.960 561.320 ;
        RECT 1.000 555.880 954.960 557.280 ;
        RECT 0.600 551.840 954.960 555.880 ;
        RECT 1.000 550.440 954.960 551.840 ;
        RECT 0.600 546.400 954.960 550.440 ;
        RECT 1.000 545.000 954.960 546.400 ;
        RECT 0.600 540.960 954.960 545.000 ;
        RECT 1.000 539.560 953.960 540.960 ;
        RECT 0.600 535.520 954.960 539.560 ;
        RECT 1.000 534.120 953.960 535.520 ;
        RECT 0.600 530.080 954.960 534.120 ;
        RECT 1.000 528.680 953.960 530.080 ;
        RECT 0.600 524.640 954.960 528.680 ;
        RECT 1.000 523.240 953.960 524.640 ;
        RECT 0.600 519.200 954.960 523.240 ;
        RECT 1.000 517.800 953.960 519.200 ;
        RECT 0.600 513.760 954.960 517.800 ;
        RECT 1.000 512.360 953.960 513.760 ;
        RECT 0.600 492.000 954.960 512.360 ;
        RECT 1.000 490.600 954.960 492.000 ;
        RECT 0.600 486.560 954.960 490.600 ;
        RECT 1.000 485.160 954.960 486.560 ;
        RECT 0.600 481.120 954.960 485.160 ;
        RECT 1.000 479.720 954.960 481.120 ;
        RECT 0.600 475.680 954.960 479.720 ;
        RECT 1.000 474.280 954.960 475.680 ;
        RECT 0.600 470.240 954.960 474.280 ;
        RECT 1.000 468.840 954.960 470.240 ;
        RECT 0.600 464.800 954.960 468.840 ;
        RECT 1.000 463.400 954.960 464.800 ;
        RECT 0.600 459.360 954.960 463.400 ;
        RECT 1.000 457.960 954.960 459.360 ;
        RECT 0.600 453.920 954.960 457.960 ;
        RECT 1.000 452.520 954.960 453.920 ;
        RECT 0.600 448.480 954.960 452.520 ;
        RECT 1.000 447.080 954.960 448.480 ;
        RECT 0.600 443.040 954.960 447.080 ;
        RECT 1.000 441.640 954.960 443.040 ;
        RECT 0.600 437.600 954.960 441.640 ;
        RECT 1.000 436.200 954.960 437.600 ;
        RECT 0.600 432.160 954.960 436.200 ;
        RECT 1.000 430.760 954.960 432.160 ;
        RECT 0.600 426.720 954.960 430.760 ;
        RECT 1.000 425.320 954.960 426.720 ;
        RECT 0.600 421.280 954.960 425.320 ;
        RECT 1.000 419.880 954.960 421.280 ;
        RECT 0.600 415.840 954.960 419.880 ;
        RECT 1.000 414.440 954.960 415.840 ;
        RECT 0.600 410.400 954.960 414.440 ;
        RECT 1.000 409.000 954.960 410.400 ;
        RECT 0.600 404.960 954.960 409.000 ;
        RECT 1.000 403.560 954.960 404.960 ;
        RECT 0.600 399.520 954.960 403.560 ;
        RECT 1.000 398.120 954.960 399.520 ;
        RECT 0.600 394.080 954.960 398.120 ;
        RECT 1.000 392.680 954.960 394.080 ;
        RECT 0.600 388.640 954.960 392.680 ;
        RECT 1.000 387.240 954.960 388.640 ;
        RECT 0.600 383.200 954.960 387.240 ;
        RECT 1.000 381.800 954.960 383.200 ;
        RECT 0.600 377.760 954.960 381.800 ;
        RECT 1.000 376.360 954.960 377.760 ;
        RECT 0.600 372.320 954.960 376.360 ;
        RECT 1.000 370.920 954.960 372.320 ;
        RECT 0.600 366.880 954.960 370.920 ;
        RECT 1.000 365.480 954.960 366.880 ;
        RECT 0.600 361.440 954.960 365.480 ;
        RECT 1.000 360.040 954.960 361.440 ;
        RECT 0.600 356.000 954.960 360.040 ;
        RECT 1.000 354.600 954.960 356.000 ;
        RECT 0.600 350.560 954.960 354.600 ;
        RECT 1.000 349.160 954.960 350.560 ;
        RECT 0.600 345.120 954.960 349.160 ;
        RECT 1.000 343.720 954.960 345.120 ;
        RECT 0.600 339.680 954.960 343.720 ;
        RECT 1.000 338.280 954.960 339.680 ;
        RECT 0.600 334.240 954.960 338.280 ;
        RECT 1.000 332.840 954.960 334.240 ;
        RECT 0.600 328.800 954.960 332.840 ;
        RECT 1.000 327.400 954.960 328.800 ;
        RECT 0.600 323.360 954.960 327.400 ;
        RECT 1.000 321.960 954.960 323.360 ;
        RECT 0.600 317.920 954.960 321.960 ;
        RECT 1.000 316.520 953.960 317.920 ;
        RECT 0.600 312.480 954.960 316.520 ;
        RECT 1.000 311.080 953.960 312.480 ;
        RECT 0.600 307.040 954.960 311.080 ;
        RECT 1.000 305.640 953.960 307.040 ;
        RECT 0.600 301.600 954.960 305.640 ;
        RECT 1.000 300.200 953.960 301.600 ;
        RECT 0.600 296.160 954.960 300.200 ;
        RECT 1.000 294.760 953.960 296.160 ;
        RECT 0.600 290.720 954.960 294.760 ;
        RECT 1.000 289.320 953.960 290.720 ;
        RECT 0.600 268.960 954.960 289.320 ;
        RECT 1.000 267.560 954.960 268.960 ;
        RECT 0.600 263.520 954.960 267.560 ;
        RECT 1.000 262.120 954.960 263.520 ;
        RECT 0.600 258.080 954.960 262.120 ;
        RECT 1.000 256.680 954.960 258.080 ;
        RECT 0.600 252.640 954.960 256.680 ;
        RECT 1.000 251.240 954.960 252.640 ;
        RECT 0.600 247.200 954.960 251.240 ;
        RECT 1.000 245.800 954.960 247.200 ;
        RECT 0.600 241.760 954.960 245.800 ;
        RECT 1.000 240.360 954.960 241.760 ;
        RECT 0.600 236.320 954.960 240.360 ;
        RECT 1.000 234.920 954.960 236.320 ;
        RECT 0.600 230.880 954.960 234.920 ;
        RECT 1.000 229.480 954.960 230.880 ;
        RECT 0.600 225.440 954.960 229.480 ;
        RECT 1.000 224.040 954.960 225.440 ;
        RECT 0.600 220.000 954.960 224.040 ;
        RECT 1.000 218.600 954.960 220.000 ;
        RECT 0.600 214.560 954.960 218.600 ;
        RECT 1.000 213.160 954.960 214.560 ;
        RECT 0.600 209.120 954.960 213.160 ;
        RECT 1.000 207.720 954.960 209.120 ;
        RECT 0.600 203.680 954.960 207.720 ;
        RECT 1.000 202.280 954.960 203.680 ;
        RECT 0.600 198.240 954.960 202.280 ;
        RECT 1.000 196.840 954.960 198.240 ;
        RECT 0.600 192.800 954.960 196.840 ;
        RECT 1.000 191.400 954.960 192.800 ;
        RECT 0.600 187.360 954.960 191.400 ;
        RECT 1.000 185.960 954.960 187.360 ;
        RECT 0.600 181.920 954.960 185.960 ;
        RECT 1.000 180.520 954.960 181.920 ;
        RECT 0.600 176.480 954.960 180.520 ;
        RECT 1.000 175.080 954.960 176.480 ;
        RECT 0.600 171.040 954.960 175.080 ;
        RECT 1.000 169.640 954.960 171.040 ;
        RECT 0.600 165.600 954.960 169.640 ;
        RECT 1.000 164.200 954.960 165.600 ;
        RECT 0.600 160.160 954.960 164.200 ;
        RECT 1.000 158.760 954.960 160.160 ;
        RECT 0.600 154.720 954.960 158.760 ;
        RECT 1.000 153.320 954.960 154.720 ;
        RECT 0.600 149.280 954.960 153.320 ;
        RECT 1.000 147.880 954.960 149.280 ;
        RECT 0.600 143.840 954.960 147.880 ;
        RECT 1.000 142.440 954.960 143.840 ;
        RECT 0.600 138.400 954.960 142.440 ;
        RECT 1.000 137.000 954.960 138.400 ;
        RECT 0.600 132.960 954.960 137.000 ;
        RECT 1.000 131.560 954.960 132.960 ;
        RECT 0.600 127.520 954.960 131.560 ;
        RECT 1.000 126.120 954.960 127.520 ;
        RECT 0.600 122.080 954.960 126.120 ;
        RECT 1.000 120.680 954.960 122.080 ;
        RECT 0.600 116.640 954.960 120.680 ;
        RECT 1.000 115.240 954.960 116.640 ;
        RECT 0.600 111.200 954.960 115.240 ;
        RECT 1.000 109.800 954.960 111.200 ;
        RECT 0.600 105.760 954.960 109.800 ;
        RECT 1.000 104.360 954.960 105.760 ;
        RECT 0.600 100.320 954.960 104.360 ;
        RECT 1.000 98.920 954.960 100.320 ;
        RECT 0.600 94.880 954.960 98.920 ;
        RECT 1.000 93.480 953.960 94.880 ;
        RECT 0.600 89.440 954.960 93.480 ;
        RECT 1.000 88.040 953.960 89.440 ;
        RECT 0.600 84.000 954.960 88.040 ;
        RECT 1.000 82.600 953.960 84.000 ;
        RECT 0.600 78.560 954.960 82.600 ;
        RECT 1.000 77.160 953.960 78.560 ;
        RECT 0.600 73.120 954.960 77.160 ;
        RECT 1.000 71.720 953.960 73.120 ;
        RECT 0.600 67.680 954.960 71.720 ;
        RECT 1.000 66.280 953.960 67.680 ;
        RECT 0.600 50.000 954.960 66.280 ;
        RECT 1.000 6.440 954.960 50.000 ;
        RECT 0.600 0.855 954.960 6.440 ;
      LAYER met4 ;
        RECT 0.310 4.935 6.560 1394.505 ;
        RECT 8.960 4.935 11.860 1394.505 ;
        RECT 14.260 4.935 36.560 1394.505 ;
        RECT 38.960 4.935 41.860 1394.505 ;
        RECT 44.260 4.935 62.680 1394.505 ;
        RECT 65.080 4.935 67.980 1394.505 ;
        RECT 70.380 4.935 92.680 1394.505 ;
        RECT 95.080 4.935 97.980 1394.505 ;
        RECT 100.380 4.935 122.680 1394.505 ;
        RECT 125.080 4.935 127.980 1394.505 ;
        RECT 130.380 4.935 152.680 1394.505 ;
        RECT 155.080 4.935 157.980 1394.505 ;
        RECT 160.380 4.935 182.680 1394.505 ;
        RECT 185.080 4.935 187.980 1394.505 ;
        RECT 190.380 4.935 212.680 1394.505 ;
        RECT 215.080 4.935 217.980 1394.505 ;
        RECT 220.380 4.935 242.680 1394.505 ;
        RECT 245.080 4.935 247.980 1394.505 ;
        RECT 250.380 4.935 273.360 1394.505 ;
        RECT 275.760 4.935 278.660 1394.505 ;
        RECT 281.060 4.935 303.360 1394.505 ;
        RECT 305.760 4.935 308.660 1394.505 ;
        RECT 311.060 4.935 333.360 1394.505 ;
        RECT 335.760 4.935 338.660 1394.505 ;
        RECT 341.060 4.935 363.360 1394.505 ;
        RECT 365.760 4.935 368.660 1394.505 ;
        RECT 371.060 4.935 393.360 1394.505 ;
        RECT 395.760 4.935 398.660 1394.505 ;
        RECT 401.060 4.935 423.360 1394.505 ;
        RECT 425.760 4.935 428.660 1394.505 ;
        RECT 431.060 4.935 453.360 1394.505 ;
        RECT 455.760 4.935 458.660 1394.505 ;
        RECT 461.060 4.935 484.040 1394.505 ;
        RECT 486.440 4.935 489.340 1394.505 ;
        RECT 491.740 4.935 514.040 1394.505 ;
        RECT 516.440 4.935 519.340 1394.505 ;
        RECT 521.740 4.935 544.040 1394.505 ;
        RECT 546.440 4.935 549.340 1394.505 ;
        RECT 551.740 4.935 574.040 1394.505 ;
        RECT 576.440 4.935 579.340 1394.505 ;
        RECT 581.740 4.935 604.040 1394.505 ;
        RECT 606.440 4.935 609.340 1394.505 ;
        RECT 611.740 4.935 634.040 1394.505 ;
        RECT 636.440 4.935 639.340 1394.505 ;
        RECT 641.740 4.935 664.040 1394.505 ;
        RECT 666.440 4.935 669.340 1394.505 ;
        RECT 671.740 4.935 694.720 1394.505 ;
        RECT 697.120 4.935 700.020 1394.505 ;
        RECT 702.420 4.935 724.720 1394.505 ;
        RECT 727.120 4.935 730.020 1394.505 ;
        RECT 732.420 4.935 754.720 1394.505 ;
        RECT 757.120 4.935 760.020 1394.505 ;
        RECT 762.420 4.935 784.720 1394.505 ;
        RECT 787.120 4.935 790.020 1394.505 ;
        RECT 792.420 4.935 814.720 1394.505 ;
        RECT 817.120 4.935 820.020 1394.505 ;
        RECT 822.420 4.935 844.720 1394.505 ;
        RECT 847.120 4.935 850.020 1394.505 ;
        RECT 852.420 4.935 874.720 1394.505 ;
        RECT 877.120 4.935 880.020 1394.505 ;
        RECT 882.420 4.935 905.400 1394.505 ;
        RECT 907.800 4.935 910.700 1394.505 ;
        RECT 913.100 4.935 935.400 1394.505 ;
        RECT 937.800 4.935 940.700 1394.505 ;
        RECT 943.100 4.935 951.905 1394.505 ;
  END
END classic_fabric_chipfoundry_small
END LIBRARY

